### Tool : gds2rh
### RedHawk Version : 19.1.7p1 RHEL6
### Vendor : Apache Design, Inc. A Subsidiary of ANSYS, Inc. 
### Date : Mar 02 2019, 00:03:14 

### Date generated : Wed Sep 14 16:24:09 2022
 
### Command : gds2rh /nfs/an/disks/an_mos_scratch01/mos/prod/runs/c224uhdlpsprf-ext-version-r1-0-1/r641703_00_00/r641703_00_00/avm/rv_avm/gds2rh_options_powerup.txt

VERSION 5.5 ;
NAMESCASESENSITIVE ON ;
DIVIDERCHAR "/" ;
BUSBITCHARS "[]" ;
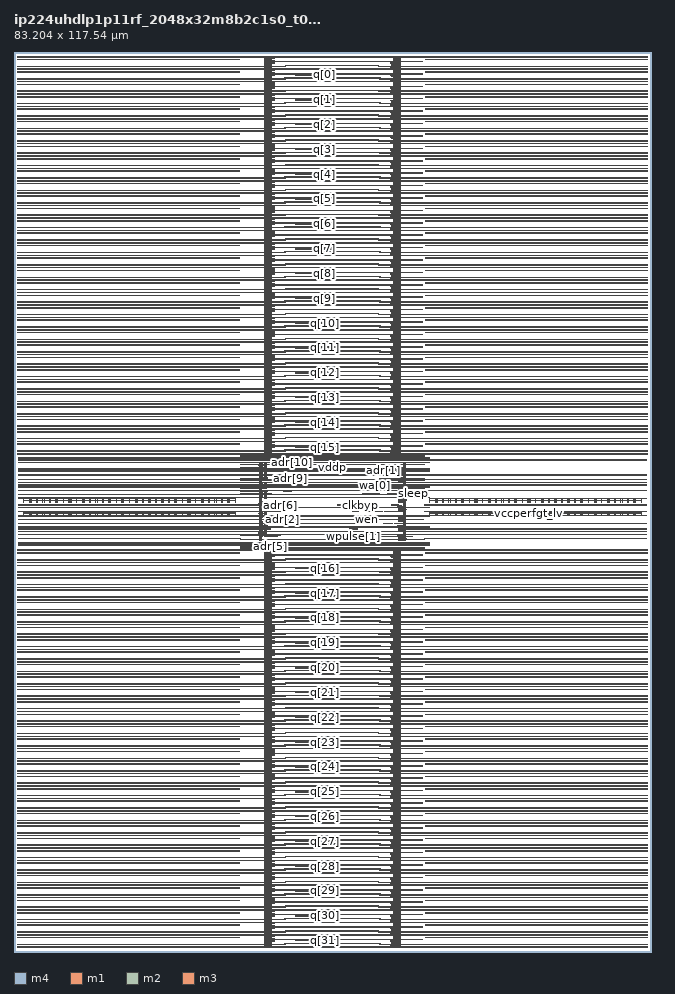
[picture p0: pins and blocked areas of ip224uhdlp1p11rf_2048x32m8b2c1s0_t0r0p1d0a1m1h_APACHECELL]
MACRO ip224uhdlp1p11rf_2048x32m8b2c1s0_t0r0p1d0a1m1h_APACHECELL
 ORIGIN 0.000000 0.000000 ;
 SIZE 83.204000 BY 117.540000 ;
 PIN adr[0]
 DIRECTION INPUT ;
 USE SIGNAL ;
 PORT
 LAYER m4 ;
 RECT 48.159500 62.924000 49.349500 63.000000 ;
 END
 END adr[0]
 PIN adr[10]
 DIRECTION INPUT ;
 USE SIGNAL ;
 PORT
 LAYER m4 ;
 RECT 35.707000 62.924000 36.837000 63.000000 ;
 END
 END adr[10]
 PIN adr[1]
 DIRECTION INPUT ;
 USE SIGNAL ;
 PORT
 LAYER m4 ;
 RECT 47.764500 61.804000 48.751500 61.880000 ;
 END
 END adr[1]
 PIN adr[2]
 DIRECTION INPUT ;
 USE SIGNAL ;
 PORT
 LAYER m4 ;
 RECT 34.445500 57.490000 35.597000 57.546000 ;
 END
 END adr[2]
 PIN adr[3]
 DIRECTION INPUT ;
 USE SIGNAL ;
 PORT
 LAYER m4 ;
 RECT 47.590000 60.848000 48.764000 60.924000 ;
 END
 END adr[3]
 PIN adr[4]
 DIRECTION INPUT ;
 USE SIGNAL ;
 PORT
 LAYER m4 ;
 RECT 48.844000 60.848000 50.006000 60.924000 ;
 END
 END adr[4]
 PIN adr[5]
 DIRECTION INPUT ;
 USE SIGNAL ;
 PORT
 LAYER m4 ;
 RECT 33.045000 52.960000 34.002000 53.036000 ;
 END
 END adr[5]
 PIN adr[6]
 DIRECTION INPUT ;
 USE SIGNAL ;
 PORT
 LAYER m4 ;
 RECT 34.326500 58.326000 35.266000 58.382000 ;
 END
 END adr[6]
 PIN adr[7]
 DIRECTION INPUT ;
 USE SIGNAL ;
 PORT
 LAYER m4 ;
 RECT 33.008000 54.226000 34.389000 54.302000 ;
 END
 END adr[7]
 PIN adr[8]
 DIRECTION INPUT ;
 USE SIGNAL ;
 PORT
 LAYER m4 ;
 RECT 33.432500 54.376000 34.741000 54.452000 ;
 END
 END adr[8]
 PIN adr[9]
 DIRECTION INPUT ;
 USE SIGNAL ;
 PORT
 LAYER m4 ;
 RECT 35.695000 61.804000 36.619500 61.880000 ;
 END
 END adr[9]
 PIN bc1
 DIRECTION INPUT ;
 USE SIGNAL ;
 PORT
 LAYER m4 ;
 RECT 47.844500 61.540000 48.908500 61.616000 ;
 END
 END bc1
 PIN bc2
 DIRECTION INPUT ;
 USE SIGNAL ;
 PORT
 LAYER m4 ;
 RECT 48.764000 59.858000 49.903500 59.914000 ;
 END
 END bc2
 PIN clkbyp
 DIRECTION INPUT ;
 USE SIGNAL ;
 PORT
 LAYER m4 ;
 RECT 44.767000 58.326000 45.619500 58.382000 ;
 END
 END clkbyp
 PIN deepslp
 DIRECTION INPUT ;
 USE SIGNAL ;
 PORT
 LAYER m4 ;
 RECT 49.268000 58.326000 50.262000 58.382000 ;
 END
 END deepslp
 PIN din[0]
 DIRECTION INPUT ;
 USE SIGNAL ;
 PORT
 LAYER m4 ;
 RECT 36.766000 114.488000 39.618000 114.596000 ;
 END
 END din[0]
 PIN din[10]
 DIRECTION INPUT ;
 USE SIGNAL ;
 PORT
 LAYER m4 ;
 RECT 36.766000 82.088000 39.618000 82.196000 ;
 END
 END din[10]
 PIN din[11]
 DIRECTION INPUT ;
 USE SIGNAL ;
 PORT
 LAYER m4 ;
 RECT 36.766000 78.848000 39.618000 78.956000 ;
 END
 END din[11]
 PIN din[12]
 DIRECTION INPUT ;
 USE SIGNAL ;
 PORT
 LAYER m4 ;
 RECT 36.766000 75.608000 39.618000 75.716000 ;
 END
 END din[12]
 PIN din[13]
 DIRECTION INPUT ;
 USE SIGNAL ;
 PORT
 LAYER m4 ;
 RECT 36.766000 72.368000 39.618000 72.476000 ;
 END
 END din[13]
 PIN din[14]
 DIRECTION INPUT ;
 USE SIGNAL ;
 PORT
 LAYER m4 ;
 RECT 36.766000 69.128000 39.618000 69.236000 ;
 END
 END din[14]
 PIN din[15]
 DIRECTION INPUT ;
 USE SIGNAL ;
 PORT
 LAYER m4 ;
 RECT 36.766000 65.888000 39.618000 65.996000 ;
 END
 END din[15]
 PIN din[16]
 DIRECTION INPUT ;
 USE SIGNAL ;
 PORT
 LAYER m4 ;
 RECT 36.766000 50.048000 39.618000 50.156000 ;
 END
 END din[16]
 PIN din[17]
 DIRECTION INPUT ;
 USE SIGNAL ;
 PORT
 LAYER m4 ;
 RECT 36.766000 46.808000 39.618000 46.916000 ;
 END
 END din[17]
 PIN din[18]
 DIRECTION INPUT ;
 USE SIGNAL ;
 PORT
 LAYER m4 ;
 RECT 36.766000 43.568000 39.618000 43.676000 ;
 END
 END din[18]
 PIN din[19]
 DIRECTION INPUT ;
 USE SIGNAL ;
 PORT
 LAYER m4 ;
 RECT 36.766000 40.328000 39.618000 40.436000 ;
 END
 END din[19]
 PIN din[1]
 DIRECTION INPUT ;
 USE SIGNAL ;
 PORT
 LAYER m4 ;
 RECT 36.766000 111.248000 39.618000 111.356000 ;
 END
 END din[1]
 PIN din[20]
 DIRECTION INPUT ;
 USE SIGNAL ;
 PORT
 LAYER m4 ;
 RECT 36.766000 37.088000 39.618000 37.196000 ;
 END
 END din[20]
 PIN din[21]
 DIRECTION INPUT ;
 USE SIGNAL ;
 PORT
 LAYER m4 ;
 RECT 36.766000 33.848000 39.618000 33.956000 ;
 END
 END din[21]
 PIN din[22]
 DIRECTION INPUT ;
 USE SIGNAL ;
 PORT
 LAYER m4 ;
 RECT 36.766000 30.608000 39.618000 30.716000 ;
 END
 END din[22]
 PIN din[23]
 DIRECTION INPUT ;
 USE SIGNAL ;
 PORT
 LAYER m4 ;
 RECT 36.766000 27.368000 39.618000 27.476000 ;
 END
 END din[23]
 PIN din[24]
 DIRECTION INPUT ;
 USE SIGNAL ;
 PORT
 LAYER m4 ;
 RECT 36.766000 24.128000 39.618000 24.236000 ;
 END
 END din[24]
 PIN din[25]
 DIRECTION INPUT ;
 USE SIGNAL ;
 PORT
 LAYER m4 ;
 RECT 36.766000 20.888000 39.618000 20.996000 ;
 END
 END din[25]
 PIN din[26]
 DIRECTION INPUT ;
 USE SIGNAL ;
 PORT
 LAYER m4 ;
 RECT 36.766000 17.648000 39.618000 17.756000 ;
 END
 END din[26]
 PIN din[27]
 DIRECTION INPUT ;
 USE SIGNAL ;
 PORT
 LAYER m4 ;
 RECT 36.766000 14.408000 39.618000 14.516000 ;
 END
 END din[27]
 PIN din[28]
 DIRECTION INPUT ;
 USE SIGNAL ;
 PORT
 LAYER m4 ;
 RECT 36.766000 11.168000 39.618000 11.276000 ;
 END
 END din[28]
 PIN din[29]
 DIRECTION INPUT ;
 USE SIGNAL ;
 PORT
 LAYER m4 ;
 RECT 36.766000 7.928000 39.618000 8.036000 ;
 END
 END din[29]
 PIN din[2]
 DIRECTION INPUT ;
 USE SIGNAL ;
 PORT
 LAYER m4 ;
 RECT 36.766000 108.008000 39.618000 108.116000 ;
 END
 END din[2]
 PIN din[30]
 DIRECTION INPUT ;
 USE SIGNAL ;
 PORT
 LAYER m4 ;
 RECT 36.766000 4.688000 39.618000 4.796000 ;
 END
 END din[30]
 PIN din[31]
 DIRECTION INPUT ;
 USE SIGNAL ;
 PORT
 LAYER m4 ;
 RECT 36.766000 1.448000 39.618000 1.556000 ;
 END
 END din[31]
 PIN din[3]
 DIRECTION INPUT ;
 USE SIGNAL ;
 PORT
 LAYER m4 ;
 RECT 36.766000 104.768000 39.618000 104.876000 ;
 END
 END din[3]
 PIN din[4]
 DIRECTION INPUT ;
 USE SIGNAL ;
 PORT
 LAYER m4 ;
 RECT 36.766000 101.528000 39.618000 101.636000 ;
 END
 END din[4]
 PIN din[5]
 DIRECTION INPUT ;
 USE SIGNAL ;
 PORT
 LAYER m4 ;
 RECT 36.766000 98.288000 39.618000 98.396000 ;
 END
 END din[5]
 PIN din[6]
 DIRECTION INPUT ;
 USE SIGNAL ;
 PORT
 LAYER m4 ;
 RECT 36.766000 95.048000 39.618000 95.156000 ;
 END
 END din[6]
 PIN din[7]
 DIRECTION INPUT ;
 USE SIGNAL ;
 PORT
 LAYER m4 ;
 RECT 36.766000 91.808000 39.618000 91.916000 ;
 END
 END din[7]
 PIN din[8]
 DIRECTION INPUT ;
 USE SIGNAL ;
 PORT
 LAYER m4 ;
 RECT 36.766000 88.568000 39.618000 88.676000 ;
 END
 END din[8]
 PIN din[9]
 DIRECTION INPUT ;
 USE SIGNAL ;
 PORT
 LAYER m4 ;
 RECT 36.766000 85.328000 39.618000 85.436000 ;
 END
 END din[9]
 PIN fwen
 DIRECTION INPUT ;
 USE SIGNAL ;
 PORT
 LAYER m4 ;
 RECT 48.419500 57.490000 49.374000 57.546000 ;
 END
 END fwen
 PIN mc[0]
 DIRECTION INPUT ;
 USE SIGNAL ;
 PORT
 LAYER m4 ;
 RECT 35.244000 60.124000 36.283000 60.200000 ;
 END
 END mc[0]
 PIN mc[1]
 DIRECTION INPUT ;
 USE SIGNAL ;
 PORT
 LAYER m4 ;
 RECT 33.024000 61.540000 34.252000 61.616000 ;
 END
 END mc[1]
 PIN mc[2]
 DIRECTION INPUT ;
 USE SIGNAL ;
 PORT
 LAYER m4 ;
 RECT 34.383000 61.540000 35.525000 61.616000 ;
 END
 END mc[2]
 PIN mcen
 DIRECTION INPUT ;
 USE SIGNAL ;
 PORT
 LAYER m4 ;
 RECT 34.480500 61.804000 35.417000 61.880000 ;
 END
 END mcen
 PIN mpr
 DIRECTION OUTPUT ;
 USE SIGNAL ;
 PORT
 LAYER m4 ;
 RECT 47.125000 57.490000 48.061000 57.546000 ;
 END
 END mpr
 PIN q[0]
 DIRECTION OUTPUT ;
 USE SIGNAL ;
 PORT
 LAYER m4 ;
 RECT 39.698000 114.488000 41.423000 114.596000 ;
 END
 END q[0]
 PIN q[10]
 DIRECTION OUTPUT ;
 USE SIGNAL ;
 PORT
 LAYER m4 ;
 RECT 39.698000 82.088000 41.423000 82.196000 ;
 END
 END q[10]
 PIN q[11]
 DIRECTION OUTPUT ;
 USE SIGNAL ;
 PORT
 LAYER m4 ;
 RECT 39.698000 78.848000 41.423000 78.956000 ;
 END
 END q[11]
 PIN q[12]
 DIRECTION OUTPUT ;
 USE SIGNAL ;
 PORT
 LAYER m4 ;
 RECT 39.698000 75.608000 41.423000 75.716000 ;
 END
 END q[12]
 PIN q[13]
 DIRECTION OUTPUT ;
 USE SIGNAL ;
 PORT
 LAYER m4 ;
 RECT 39.698000 72.368000 41.423000 72.476000 ;
 END
 END q[13]
 PIN q[14]
 DIRECTION OUTPUT ;
 USE SIGNAL ;
 PORT
 LAYER m4 ;
 RECT 39.698000 69.128000 41.423000 69.236000 ;
 END
 END q[14]
 PIN q[15]
 DIRECTION OUTPUT ;
 USE SIGNAL ;
 PORT
 LAYER m4 ;
 RECT 39.698000 65.888000 41.423000 65.996000 ;
 END
 END q[15]
 PIN q[16]
 DIRECTION OUTPUT ;
 USE SIGNAL ;
 PORT
 LAYER m4 ;
 RECT 39.698000 50.048000 41.423000 50.156000 ;
 END
 END q[16]
 PIN q[17]
 DIRECTION OUTPUT ;
 USE SIGNAL ;
 PORT
 LAYER m4 ;
 RECT 39.698000 46.808000 41.423000 46.916000 ;
 END
 END q[17]
 PIN q[18]
 DIRECTION OUTPUT ;
 USE SIGNAL ;
 PORT
 LAYER m4 ;
 RECT 39.698000 43.568000 41.423000 43.676000 ;
 END
 END q[18]
 PIN q[19]
 DIRECTION OUTPUT ;
 USE SIGNAL ;
 PORT
 LAYER m4 ;
 RECT 39.698000 40.328000 41.423000 40.436000 ;
 END
 END q[19]
 PIN q[1]
 DIRECTION OUTPUT ;
 USE SIGNAL ;
 PORT
 LAYER m4 ;
 RECT 39.698000 111.248000 41.423000 111.356000 ;
 END
 END q[1]
 PIN q[20]
 DIRECTION OUTPUT ;
 USE SIGNAL ;
 PORT
 LAYER m4 ;
 RECT 39.698000 37.088000 41.423000 37.196000 ;
 END
 END q[20]
 PIN q[21]
 DIRECTION OUTPUT ;
 USE SIGNAL ;
 PORT
 LAYER m4 ;
 RECT 39.698000 33.848000 41.423000 33.956000 ;
 END
 END q[21]
 PIN q[22]
 DIRECTION OUTPUT ;
 USE SIGNAL ;
 PORT
 LAYER m4 ;
 RECT 39.698000 30.608000 41.423000 30.716000 ;
 END
 END q[22]
 PIN q[23]
 DIRECTION OUTPUT ;
 USE SIGNAL ;
 PORT
 LAYER m4 ;
 RECT 39.698000 27.368000 41.423000 27.476000 ;
 END
 END q[23]
 PIN q[24]
 DIRECTION OUTPUT ;
 USE SIGNAL ;
 PORT
 LAYER m4 ;
 RECT 39.698000 24.128000 41.423000 24.236000 ;
 END
 END q[24]
 PIN q[25]
 DIRECTION OUTPUT ;
 USE SIGNAL ;
 PORT
 LAYER m4 ;
 RECT 39.698000 20.888000 41.423000 20.996000 ;
 END
 END q[25]
 PIN q[26]
 DIRECTION OUTPUT ;
 USE SIGNAL ;
 PORT
 LAYER m4 ;
 RECT 39.698000 17.648000 41.423000 17.756000 ;
 END
 END q[26]
 PIN q[27]
 DIRECTION OUTPUT ;
 USE SIGNAL ;
 PORT
 LAYER m4 ;
 RECT 39.698000 14.408000 41.423000 14.516000 ;
 END
 END q[27]
 PIN q[28]
 DIRECTION OUTPUT ;
 USE SIGNAL ;
 PORT
 LAYER m4 ;
 RECT 39.698000 11.168000 41.423000 11.276000 ;
 END
 END q[28]
 PIN q[29]
 DIRECTION OUTPUT ;
 USE SIGNAL ;
 PORT
 LAYER m4 ;
 RECT 39.698000 7.928000 41.423000 8.036000 ;
 END
 END q[29]
 PIN q[2]
 DIRECTION OUTPUT ;
 USE SIGNAL ;
 PORT
 LAYER m4 ;
 RECT 39.698000 108.008000 41.423000 108.116000 ;
 END
 END q[2]
 PIN q[30]
 DIRECTION OUTPUT ;
 USE SIGNAL ;
 PORT
 LAYER m4 ;
 RECT 39.698000 4.688000 41.423000 4.796000 ;
 END
 END q[30]
 PIN q[31]
 DIRECTION OUTPUT ;
 USE SIGNAL ;
 PORT
 LAYER m4 ;
 RECT 39.698000 1.448000 41.423000 1.556000 ;
 END
 END q[31]
 PIN q[3]
 DIRECTION OUTPUT ;
 USE SIGNAL ;
 PORT
 LAYER m4 ;
 RECT 39.698000 104.768000 41.423000 104.876000 ;
 END
 END q[3]
 PIN q[4]
 DIRECTION OUTPUT ;
 USE SIGNAL ;
 PORT
 LAYER m4 ;
 RECT 39.698000 101.528000 41.423000 101.636000 ;
 END
 END q[4]
 PIN q[5]
 DIRECTION OUTPUT ;
 USE SIGNAL ;
 PORT
 LAYER m4 ;
 RECT 39.698000 98.288000 41.423000 98.396000 ;
 END
 END q[5]
 PIN q[6]
 DIRECTION OUTPUT ;
 USE SIGNAL ;
 PORT
 LAYER m4 ;
 RECT 39.698000 95.048000 41.423000 95.156000 ;
 END
 END q[6]
 PIN q[7]
 DIRECTION OUTPUT ;
 USE SIGNAL ;
 PORT
 LAYER m4 ;
 RECT 39.698000 91.808000 41.423000 91.916000 ;
 END
 END q[7]
 PIN q[8]
 DIRECTION OUTPUT ;
 USE SIGNAL ;
 PORT
 LAYER m4 ;
 RECT 39.698000 88.568000 41.423000 88.676000 ;
 END
 END q[8]
 PIN q[9]
 DIRECTION OUTPUT ;
 USE SIGNAL ;
 PORT
 LAYER m4 ;
 RECT 39.698000 85.328000 41.423000 85.436000 ;
 END
 END q[9]
 PIN ren
 DIRECTION INPUT ;
 USE SIGNAL ;
 PORT
 LAYER m4 ;
 RECT 44.150000 57.490000 45.055500 57.546000 ;
 END
 END ren
 PIN shutoff
 DIRECTION INPUT ;
 USE SIGNAL ;
 PORT
 LAYER m4 ;
 RECT 49.596000 57.490000 50.517500 57.546000 ;
 END
 END shutoff
 PIN sleep
 DIRECTION INPUT ;
 USE SIGNAL ;
 PORT
 LAYER m4 ;
 RECT 51.755500 59.858000 52.678500 59.914000 ;
 END
 END sleep
 PIN wa[0]
 DIRECTION INPUT ;
 USE SIGNAL ;
 PORT
 LAYER m4 ;
 RECT 46.712000 59.858000 47.676500 59.914000 ;
 END
 END wa[0]
 PIN wa[1]
 DIRECTION INPUT ;
 USE SIGNAL ;
 PORT
 LAYER m4 ;
 RECT 45.499500 59.858000 46.530000 59.914000 ;
 END
 END wa[1]
 PIN wen
 DIRECTION INPUT ;
 USE SIGNAL ;
 PORT
 LAYER m4 ;
 RECT 45.614000 57.490000 46.502000 57.546000 ;
 END
 END wen
 PIN wpulse[0]
 DIRECTION INPUT ;
 USE SIGNAL ;
 PORT
 LAYER m4 ;
 RECT 48.239000 55.924000 49.496000 56.000000 ;
 END
 END wpulse[0]
 PIN wpulse[1]
 DIRECTION INPUT ;
 USE SIGNAL ;
 PORT
 LAYER m4 ;
 RECT 43.758500 55.200000 44.802000 55.276000 ;
 END
 END wpulse[1]
 PIN wpulseen
 DIRECTION INPUT ;
 USE SIGNAL ;
 PORT
 LAYER m4 ;
 RECT 44.564500 55.924000 45.451000 56.000000 ;
 END
 END wpulseen
 PIN clk
 DIRECTION INPUT ;
 USE CLOCK ;
 PORT
 LAYER m4 ;
 RECT 42.224500 58.326000 43.256500 58.382000 ;
 END
 END clk
 PIN vddp
 DIRECTION INPUT ;
 USE POWER ;
 PORT
 LAYER m4 ;
 RECT 0.480000 0.958000 35.401000 1.034000 ;
 RECT 0.480000 1.846000 29.388000 1.922000 ;
 RECT 0.480000 10.678000 35.401000 10.754000 ;
 RECT 0.480000 100.306000 29.388000 100.382000 ;
 RECT 0.480000 101.038000 35.401000 101.114000 ;
 RECT 0.480000 101.926000 29.388000 102.002000 ;
 RECT 0.480000 102.658000 35.487000 102.734000 ;
 RECT 0.480000 103.546000 29.388000 103.622000 ;
 RECT 0.480000 104.278000 35.401000 104.354000 ;
 RECT 0.480000 105.166000 29.388000 105.242000 ;
 RECT 0.480000 105.898000 35.487000 105.974000 ;
 RECT 0.480000 106.786000 29.388000 106.862000 ;
 RECT 0.480000 107.518000 35.401000 107.594000 ;
 RECT 0.480000 108.406000 29.388000 108.482000 ;
 RECT 0.480000 109.138000 35.487000 109.214000 ;
 RECT 0.480000 11.566000 29.388000 11.642000 ;
 RECT 0.480000 110.026000 29.388000 110.102000 ;
 RECT 0.480000 110.758000 35.401000 110.834000 ;
 RECT 0.480000 111.646000 29.388000 111.722000 ;
 RECT 0.480000 112.378000 35.487000 112.454000 ;
 RECT 0.480000 113.266000 29.388000 113.342000 ;
 RECT 0.480000 113.998000 35.401000 114.074000 ;
 RECT 0.480000 114.886000 29.388000 114.962000 ;
 RECT 0.480000 115.618000 35.487000 115.694000 ;
 RECT 0.480000 116.506000 29.388000 116.582000 ;
 RECT 0.480000 12.298000 35.487000 12.374000 ;
 RECT 0.480000 13.186000 29.388000 13.262000 ;
 RECT 0.480000 13.918000 35.401000 13.994000 ;
 RECT 0.480000 14.806000 29.388000 14.882000 ;
 RECT 0.480000 15.538000 35.487000 15.614000 ;
 RECT 0.480000 16.426000 29.388000 16.502000 ;
 RECT 0.480000 17.158000 35.401000 17.234000 ;
 RECT 0.480000 18.046000 29.388000 18.122000 ;
 RECT 0.480000 18.778000 35.487000 18.854000 ;
 RECT 0.480000 19.666000 29.388000 19.742000 ;
 RECT 0.480000 2.578000 35.487000 2.654000 ;
 RECT 0.480000 20.398000 35.401000 20.474000 ;
 RECT 0.480000 21.286000 29.388000 21.362000 ;
 RECT 0.480000 22.018000 35.487000 22.094000 ;
 RECT 0.480000 22.906000 29.388000 22.982000 ;
 RECT 0.480000 23.638000 35.401000 23.714000 ;
 RECT 0.480000 24.526000 29.388000 24.602000 ;
 RECT 0.480000 25.258000 35.487000 25.334000 ;
 RECT 0.480000 26.146000 29.388000 26.222000 ;
 RECT 0.480000 26.878000 35.401000 26.954000 ;
 RECT 0.480000 27.766000 29.388000 27.842000 ;
 RECT 0.480000 28.498000 35.487000 28.574000 ;
 RECT 0.480000 29.386000 29.388000 29.462000 ;
 RECT 0.480000 3.466000 29.388000 3.542000 ;
 RECT 0.480000 30.118000 35.401000 30.194000 ;
 RECT 0.480000 31.006000 29.388000 31.082000 ;
 RECT 0.480000 31.738000 35.487000 31.814000 ;
 RECT 0.480000 32.626000 29.388000 32.702000 ;
 RECT 0.480000 33.358000 35.401000 33.434000 ;
 RECT 0.480000 34.246000 29.388000 34.322000 ;
 RECT 0.480000 34.978000 35.487000 35.054000 ;
 RECT 0.480000 35.866000 29.388000 35.942000 ;
 RECT 0.480000 36.598000 35.401000 36.674000 ;
 RECT 0.480000 37.486000 29.388000 37.562000 ;
 RECT 0.480000 38.218000 35.487000 38.294000 ;
 RECT 0.480000 39.106000 29.388000 39.182000 ;
 RECT 0.480000 39.838000 35.401000 39.914000 ;
 RECT 0.480000 4.198000 35.401000 4.274000 ;
 RECT 0.480000 40.726000 29.388000 40.802000 ;
 RECT 0.480000 41.458000 35.487000 41.534000 ;
 RECT 0.480000 42.346000 29.388000 42.422000 ;
 RECT 0.480000 43.078000 35.401000 43.154000 ;
 RECT 0.480000 43.966000 29.388000 44.042000 ;
 RECT 0.480000 44.698000 35.487000 44.774000 ;
 RECT 0.480000 45.586000 29.388000 45.662000 ;
 RECT 0.480000 46.318000 35.401000 46.394000 ;
 RECT 0.480000 47.206000 29.388000 47.282000 ;
 RECT 0.480000 47.938000 35.487000 48.014000 ;
 RECT 0.480000 48.826000 29.388000 48.902000 ;
 RECT 0.480000 49.558000 35.401000 49.634000 ;
 RECT 0.480000 5.086000 29.388000 5.162000 ;
 RECT 0.480000 5.818000 35.487000 5.894000 ;
 RECT 0.480000 50.446000 29.388000 50.522000 ;
 RECT 0.480000 51.178000 35.487000 51.254000 ;
 RECT 0.480000 52.066000 29.388000 52.142000 ;
 RECT 0.480000 6.706000 29.388000 6.782000 ;
 RECT 0.480000 65.398000 35.401000 65.474000 ;
 RECT 0.480000 66.286000 29.388000 66.362000 ;
 RECT 0.480000 67.018000 35.487000 67.094000 ;
 RECT 0.480000 67.906000 29.388000 67.982000 ;
 RECT 0.480000 68.638000 35.401000 68.714000 ;
 RECT 0.480000 69.526000 29.388000 69.602000 ;
 RECT 0.480000 7.438000 35.401000 7.514000 ;
 RECT 0.480000 70.258000 35.487000 70.334000 ;
 RECT 0.480000 71.146000 29.388000 71.222000 ;
 RECT 0.480000 71.878000 35.401000 71.954000 ;
 RECT 0.480000 72.766000 29.388000 72.842000 ;
 RECT 0.480000 73.498000 35.487000 73.574000 ;
 RECT 0.480000 74.386000 29.388000 74.462000 ;
 RECT 0.480000 75.118000 35.401000 75.194000 ;
 RECT 0.480000 76.006000 29.388000 76.082000 ;
 RECT 0.480000 76.738000 35.487000 76.814000 ;
 RECT 0.480000 77.626000 29.388000 77.702000 ;
 RECT 0.480000 78.358000 35.401000 78.434000 ;
 RECT 0.480000 79.246000 29.388000 79.322000 ;
 RECT 0.480000 79.978000 35.487000 80.054000 ;
 RECT 0.480000 8.326000 29.388000 8.402000 ;
 RECT 0.480000 80.866000 29.388000 80.942000 ;
 RECT 0.480000 81.598000 35.401000 81.674000 ;
 RECT 0.480000 82.486000 29.388000 82.562000 ;
 RECT 0.480000 83.218000 35.487000 83.294000 ;
 RECT 0.480000 84.106000 29.388000 84.182000 ;
 RECT 0.480000 84.838000 35.401000 84.914000 ;
 RECT 0.480000 85.726000 29.388000 85.802000 ;
 RECT 0.480000 86.458000 35.487000 86.534000 ;
 RECT 0.480000 87.346000 29.388000 87.422000 ;
 RECT 0.480000 88.078000 35.401000 88.154000 ;
 RECT 0.480000 88.966000 29.388000 89.042000 ;
 RECT 0.480000 89.698000 35.487000 89.774000 ;
 RECT 0.480000 9.058000 35.487000 9.134000 ;
 RECT 0.480000 9.946000 29.388000 10.022000 ;
 RECT 0.480000 90.586000 29.388000 90.662000 ;
 RECT 0.480000 91.318000 35.401000 91.394000 ;
 RECT 0.480000 92.206000 29.388000 92.282000 ;
 RECT 0.480000 92.938000 35.487000 93.014000 ;
 RECT 0.480000 93.826000 29.388000 93.902000 ;
 RECT 0.480000 94.558000 35.401000 94.634000 ;
 RECT 0.480000 95.446000 29.388000 95.522000 ;
 RECT 0.480000 96.178000 35.487000 96.254000 ;
 RECT 0.480000 97.066000 29.388000 97.142000 ;
 RECT 0.480000 97.798000 35.401000 97.874000 ;
 RECT 0.480000 98.686000 29.388000 98.762000 ;
 RECT 0.480000 99.418000 35.487000 99.494000 ;
 RECT 0.616000 53.948000 29.560000 54.024000 ;
 RECT 0.616000 54.508000 82.588000 54.584000 ;
 RECT 0.616000 54.904000 82.588000 54.980000 ;
 RECT 0.616000 55.200000 29.560000 55.276000 ;
 RECT 0.616000 55.924000 29.560000 56.000000 ;
 RECT 0.616000 56.992000 28.912000 57.036000 ;
 RECT 0.616000 57.490000 29.560000 57.546000 ;
 RECT 0.616000 58.326000 29.560000 58.382000 ;
 RECT 0.616000 59.244000 28.912000 59.288000 ;
 RECT 0.616000 60.256000 82.588000 60.332000 ;
 RECT 0.616000 60.980000 82.588000 61.056000 ;
 RECT 0.616000 61.276000 82.588000 61.352000 ;
 RECT 0.616000 61.672000 82.588000 61.748000 ;
 RECT 0.616000 62.232000 82.588000 62.308000 ;
 RECT 0.616000 64.176000 82.588000 64.284000 ;
 RECT 29.600000 52.564000 53.604000 52.640000 ;
 RECT 29.600000 52.696000 53.604000 52.772000 ;
 RECT 29.600000 52.960000 32.965000 53.036000 ;
 RECT 29.600000 53.816000 53.604000 53.892000 ;
 RECT 29.600000 54.376000 33.352500 54.452000 ;
 RECT 29.600000 63.616000 53.604000 63.692000 ;
 RECT 29.600000 64.636000 53.604000 64.712000 ;
 RECT 29.600000 64.900000 53.604000 64.976000 ;
 RECT 29.608500 59.858000 33.602500 59.914000 ;
 RECT 29.608500 60.124000 33.168500 60.200000 ;
 RECT 29.608500 60.552000 32.918500 60.628000 ;
 RECT 29.608500 61.540000 32.918500 61.616000 ;
 RECT 29.608500 61.804000 32.918500 61.880000 ;
 RECT 29.608500 62.924000 32.918500 63.000000 ;
 RECT 29.608500 63.220000 32.918500 63.296000 ;
 RECT 29.651000 58.326000 34.101500 58.382000 ;
 RECT 29.654000 57.490000 34.365500 57.546000 ;
 RECT 29.669000 55.924000 44.484500 56.000000 ;
 RECT 29.732000 55.200000 33.564000 55.276000 ;
 RECT 35.325000 1.080000 47.814000 1.156000 ;
 RECT 35.325000 10.800000 47.814000 10.876000 ;
 RECT 35.325000 101.160000 47.814000 101.236000 ;
 RECT 35.325000 104.400000 47.814000 104.476000 ;
 RECT 35.325000 107.640000 47.814000 107.716000 ;
 RECT 35.325000 110.880000 47.814000 110.956000 ;
 RECT 35.325000 114.120000 47.814000 114.196000 ;
 RECT 35.325000 14.040000 47.814000 14.116000 ;
 RECT 35.325000 17.280000 47.814000 17.356000 ;
 RECT 35.325000 20.520000 47.814000 20.596000 ;
 RECT 35.325000 23.760000 47.814000 23.836000 ;
 RECT 35.325000 27.000000 47.814000 27.076000 ;
 RECT 35.325000 30.240000 47.814000 30.316000 ;
 RECT 35.325000 33.480000 47.814000 33.556000 ;
 RECT 35.325000 36.720000 47.814000 36.796000 ;
 RECT 35.325000 39.960000 47.814000 40.036000 ;
 RECT 35.325000 4.320000 47.814000 4.396000 ;
 RECT 35.325000 43.200000 47.814000 43.276000 ;
 RECT 35.325000 46.440000 47.814000 46.516000 ;
 RECT 35.325000 49.680000 47.814000 49.756000 ;
 RECT 35.325000 65.520000 47.814000 65.596000 ;
 RECT 35.325000 68.760000 47.814000 68.836000 ;
 RECT 35.325000 7.560000 47.814000 7.636000 ;
 RECT 35.325000 72.000000 47.814000 72.076000 ;
 RECT 35.325000 75.240000 47.814000 75.316000 ;
 RECT 35.325000 78.480000 47.814000 78.556000 ;
 RECT 35.325000 81.720000 47.814000 81.796000 ;
 RECT 35.325000 84.960000 47.814000 85.036000 ;
 RECT 35.325000 88.200000 47.814000 88.276000 ;
 RECT 35.325000 91.440000 47.814000 91.516000 ;
 RECT 35.325000 94.680000 47.814000 94.756000 ;
 RECT 35.325000 97.920000 47.814000 97.996000 ;
 RECT 35.487000 102.780000 47.657500 102.856000 ;
 RECT 35.487000 106.020000 47.657500 106.096000 ;
 RECT 35.487000 109.260000 47.657500 109.336000 ;
 RECT 35.487000 112.500000 47.657500 112.576000 ;
 RECT 35.487000 115.740000 47.657500 115.816000 ;
 RECT 35.487000 12.420000 47.657500 12.496000 ;
 RECT 35.487000 15.660000 47.657500 15.736000 ;
 RECT 35.487000 18.900000 47.657500 18.976000 ;
 RECT 35.487000 2.700000 47.657500 2.776000 ;
 RECT 35.487000 22.140000 47.657500 22.216000 ;
 RECT 35.487000 25.380000 47.657500 25.456000 ;
 RECT 35.487000 28.620000 47.657500 28.696000 ;
 RECT 35.487000 31.860000 47.657500 31.936000 ;
 RECT 35.487000 35.100000 47.657500 35.176000 ;
 RECT 35.487000 38.340000 47.657500 38.416000 ;
 RECT 35.487000 41.580000 47.657500 41.656000 ;
 RECT 35.487000 44.820000 47.657500 44.896000 ;
 RECT 35.487000 48.060000 47.657500 48.136000 ;
 RECT 35.487000 5.940000 47.657500 6.016000 ;
 RECT 35.487000 51.300000 47.657500 51.376000 ;
 RECT 35.487000 67.140000 47.657500 67.216000 ;
 RECT 35.487000 70.380000 47.657500 70.456000 ;
 RECT 35.487000 73.620000 47.657500 73.696000 ;
 RECT 35.487000 76.860000 47.657500 76.936000 ;
 RECT 35.487000 80.100000 47.657500 80.176000 ;
 RECT 35.487000 83.340000 47.657500 83.416000 ;
 RECT 35.487000 86.580000 47.657500 86.656000 ;
 RECT 35.487000 89.820000 47.657500 89.896000 ;
 RECT 35.487000 9.180000 47.657500 9.256000 ;
 RECT 35.487000 93.060000 47.657500 93.136000 ;
 RECT 35.487000 96.300000 47.657500 96.376000 ;
 RECT 35.487000 99.540000 47.657500 99.616000 ;
 RECT 46.038000 60.552000 53.557500 60.608000 ;
 RECT 47.581500 102.658000 82.724000 102.734000 ;
 RECT 47.581500 105.898000 82.724000 105.974000 ;
 RECT 47.581500 109.138000 82.724000 109.214000 ;
 RECT 47.581500 112.378000 82.724000 112.454000 ;
 RECT 47.581500 115.618000 82.724000 115.694000 ;
 RECT 47.581500 12.298000 82.724000 12.374000 ;
 RECT 47.581500 15.538000 82.724000 15.614000 ;
 RECT 47.581500 18.778000 82.724000 18.854000 ;
 RECT 47.581500 2.578000 82.724000 2.654000 ;
 RECT 47.581500 22.018000 82.724000 22.094000 ;
 RECT 47.581500 25.258000 82.724000 25.334000 ;
 RECT 47.581500 28.498000 82.724000 28.574000 ;
 RECT 47.581500 31.738000 82.724000 31.814000 ;
 RECT 47.581500 34.978000 82.724000 35.054000 ;
 RECT 47.581500 38.218000 82.724000 38.294000 ;
 RECT 47.581500 41.458000 82.724000 41.534000 ;
 RECT 47.581500 44.698000 82.724000 44.774000 ;
 RECT 47.581500 47.938000 82.724000 48.014000 ;
 RECT 47.581500 5.818000 82.724000 5.894000 ;
 RECT 47.581500 51.178000 82.724000 51.254000 ;
 RECT 47.581500 67.018000 82.724000 67.094000 ;
 RECT 47.581500 70.258000 82.724000 70.334000 ;
 RECT 47.581500 73.498000 82.724000 73.574000 ;
 RECT 47.581500 76.738000 82.724000 76.814000 ;
 RECT 47.581500 79.978000 82.724000 80.054000 ;
 RECT 47.581500 83.218000 82.724000 83.294000 ;
 RECT 47.581500 86.458000 82.724000 86.534000 ;
 RECT 47.581500 89.698000 82.724000 89.774000 ;
 RECT 47.581500 9.058000 82.724000 9.134000 ;
 RECT 47.581500 92.938000 82.724000 93.014000 ;
 RECT 47.581500 96.178000 82.724000 96.254000 ;
 RECT 47.581500 99.418000 82.724000 99.494000 ;
 RECT 47.738000 0.958000 82.724000 1.034000 ;
 RECT 47.738000 10.678000 82.724000 10.754000 ;
 RECT 47.738000 101.038000 82.724000 101.114000 ;
 RECT 47.738000 104.278000 82.724000 104.354000 ;
 RECT 47.738000 107.518000 82.724000 107.594000 ;
 RECT 47.738000 110.758000 82.724000 110.834000 ;
 RECT 47.738000 113.998000 82.724000 114.074000 ;
 RECT 47.738000 13.918000 82.724000 13.994000 ;
 RECT 47.738000 17.158000 82.724000 17.234000 ;
 RECT 47.738000 20.398000 82.724000 20.474000 ;
 RECT 47.738000 23.638000 82.724000 23.714000 ;
 RECT 47.738000 26.878000 82.724000 26.954000 ;
 RECT 47.738000 30.118000 82.724000 30.194000 ;
 RECT 47.738000 33.358000 82.724000 33.434000 ;
 RECT 47.738000 36.598000 82.724000 36.674000 ;
 RECT 47.738000 39.838000 82.724000 39.914000 ;
 RECT 47.738000 4.198000 82.724000 4.274000 ;
 RECT 47.738000 43.078000 82.724000 43.154000 ;
 RECT 47.738000 46.318000 82.724000 46.394000 ;
 RECT 47.738000 49.558000 82.724000 49.634000 ;
 RECT 47.738000 65.398000 82.724000 65.474000 ;
 RECT 47.738000 68.638000 82.724000 68.714000 ;
 RECT 47.738000 7.438000 82.724000 7.514000 ;
 RECT 47.738000 71.878000 82.724000 71.954000 ;
 RECT 47.738000 75.118000 82.724000 75.194000 ;
 RECT 47.738000 78.358000 82.724000 78.434000 ;
 RECT 47.738000 81.598000 82.724000 81.674000 ;
 RECT 47.738000 84.838000 82.724000 84.914000 ;
 RECT 47.738000 88.078000 82.724000 88.154000 ;
 RECT 47.738000 91.318000 82.724000 91.394000 ;
 RECT 47.738000 94.558000 82.724000 94.634000 ;
 RECT 47.738000 97.798000 82.724000 97.874000 ;
 RECT 47.983000 54.212000 52.092000 54.320000 ;
 RECT 48.831500 61.804000 53.604000 61.880000 ;
 RECT 48.988500 61.540000 53.604000 61.616000 ;
 RECT 49.429500 62.924000 53.604000 63.000000 ;
 RECT 49.686500 55.924000 53.464500 56.000000 ;
 RECT 50.211000 55.200000 53.604000 55.276000 ;
 RECT 50.369500 60.848000 53.604500 60.924000 ;
 RECT 53.644000 53.948000 82.588000 54.024000 ;
 RECT 53.644000 55.924000 82.588000 56.000000 ;
 RECT 53.644000 57.490000 82.588000 57.546000 ;
 RECT 53.644000 58.326000 82.588000 58.382000 ;
 RECT 53.684000 55.200000 82.588000 55.276000 ;
 RECT 53.749000 1.846000 82.724000 1.922000 ;
 RECT 53.749000 100.306000 82.724000 100.382000 ;
 RECT 53.749000 101.926000 82.724000 102.002000 ;
 RECT 53.749000 103.546000 82.724000 103.622000 ;
 RECT 53.749000 105.166000 82.724000 105.242000 ;
 RECT 53.749000 106.786000 82.724000 106.862000 ;
 RECT 53.749000 108.406000 82.724000 108.482000 ;
 RECT 53.749000 11.566000 82.724000 11.642000 ;
 RECT 53.749000 110.026000 82.724000 110.102000 ;
 RECT 53.749000 111.646000 82.724000 111.722000 ;
 RECT 53.749000 113.266000 82.724000 113.342000 ;
 RECT 53.749000 114.886000 82.724000 114.962000 ;
 RECT 53.749000 116.506000 82.724000 116.582000 ;
 RECT 53.749000 13.186000 82.724000 13.262000 ;
 RECT 53.749000 14.806000 82.724000 14.882000 ;
 RECT 53.749000 16.426000 82.724000 16.502000 ;
 RECT 53.749000 18.046000 82.724000 18.122000 ;
 RECT 53.749000 19.666000 82.724000 19.742000 ;
 RECT 53.749000 21.286000 82.724000 21.362000 ;
 RECT 53.749000 22.906000 82.724000 22.982000 ;
 RECT 53.749000 24.526000 82.724000 24.602000 ;
 RECT 53.749000 26.146000 82.724000 26.222000 ;
 RECT 53.749000 27.766000 82.724000 27.842000 ;
 RECT 53.749000 29.386000 82.724000 29.462000 ;
 RECT 53.749000 3.466000 82.724000 3.542000 ;
 RECT 53.749000 31.006000 82.724000 31.082000 ;
 RECT 53.749000 32.626000 82.724000 32.702000 ;
 RECT 53.749000 34.246000 82.724000 34.322000 ;
 RECT 53.749000 35.866000 82.724000 35.942000 ;
 RECT 53.749000 37.486000 82.724000 37.562000 ;
 RECT 53.749000 39.106000 82.724000 39.182000 ;
 RECT 53.749000 40.726000 82.724000 40.802000 ;
 RECT 53.749000 42.346000 82.724000 42.422000 ;
 RECT 53.749000 43.966000 82.724000 44.042000 ;
 RECT 53.749000 45.586000 82.724000 45.662000 ;
 RECT 53.749000 47.206000 82.724000 47.282000 ;
 RECT 53.749000 48.826000 82.724000 48.902000 ;
 RECT 53.749000 5.086000 82.724000 5.162000 ;
 RECT 53.749000 50.446000 82.724000 50.522000 ;
 RECT 53.749000 52.066000 82.724000 52.142000 ;
 RECT 53.749000 6.706000 82.724000 6.782000 ;
 RECT 53.749000 66.286000 82.724000 66.362000 ;
 RECT 53.749000 67.906000 82.724000 67.982000 ;
 RECT 53.749000 69.526000 82.724000 69.602000 ;
 RECT 53.749000 71.146000 82.724000 71.222000 ;
 RECT 53.749000 72.766000 82.724000 72.842000 ;
 RECT 53.749000 74.386000 82.724000 74.462000 ;
 RECT 53.749000 76.006000 82.724000 76.082000 ;
 RECT 53.749000 77.626000 82.724000 77.702000 ;
 RECT 53.749000 79.246000 82.724000 79.322000 ;
 RECT 53.749000 8.326000 82.724000 8.402000 ;
 RECT 53.749000 80.866000 82.724000 80.942000 ;
 RECT 53.749000 82.486000 82.724000 82.562000 ;
 RECT 53.749000 84.106000 82.724000 84.182000 ;
 RECT 53.749000 85.726000 82.724000 85.802000 ;
 RECT 53.749000 87.346000 82.724000 87.422000 ;
 RECT 53.749000 88.966000 82.724000 89.042000 ;
 RECT 53.749000 9.946000 82.724000 10.022000 ;
 RECT 53.749000 90.586000 82.724000 90.662000 ;
 RECT 53.749000 92.206000 82.724000 92.282000 ;
 RECT 53.749000 93.826000 82.724000 93.902000 ;
 RECT 53.749000 95.446000 82.724000 95.522000 ;
 RECT 53.749000 97.066000 82.724000 97.142000 ;
 RECT 53.749000 98.686000 82.724000 98.762000 ;
 RECT 54.292000 56.992000 82.588000 57.036000 ;
 RECT 54.292000 59.244000 82.588000 59.288000 ;
 END
 END vddp
 PIN vss
 DIRECTION INOUT ;
 USE GROUND ;
 PORT
 LAYER m4 ;
 RECT 0.480000 0.592000 82.724000 0.668000 ;
 RECT 0.480000 10.312000 82.724000 10.388000 ;
 RECT 0.480000 100.672000 82.724000 100.748000 ;
 RECT 0.480000 102.292000 82.724000 102.368000 ;
 RECT 0.480000 103.912000 82.724000 103.988000 ;
 RECT 0.480000 105.532000 82.724000 105.608000 ;
 RECT 0.480000 107.152000 82.724000 107.228000 ;
 RECT 0.480000 108.772000 82.724000 108.848000 ;
 RECT 0.480000 11.932000 82.724000 12.008000 ;
 RECT 0.480000 110.392000 82.724000 110.468000 ;
 RECT 0.480000 112.012000 82.724000 112.088000 ;
 RECT 0.480000 113.632000 82.724000 113.708000 ;
 RECT 0.480000 115.252000 82.724000 115.328000 ;
 RECT 0.480000 116.872000 82.724000 116.948000 ;
 RECT 0.480000 13.552000 82.724000 13.628000 ;
 RECT 0.480000 15.172000 82.724000 15.248000 ;
 RECT 0.480000 16.792000 82.724000 16.868000 ;
 RECT 0.480000 18.412000 82.724000 18.488000 ;
 RECT 0.480000 2.212000 82.724000 2.288000 ;
 RECT 0.480000 20.032000 82.724000 20.108000 ;
 RECT 0.480000 21.652000 82.724000 21.728000 ;
 RECT 0.480000 23.272000 82.724000 23.348000 ;
 RECT 0.480000 24.892000 82.724000 24.968000 ;
 RECT 0.480000 26.512000 82.724000 26.588000 ;
 RECT 0.480000 28.132000 82.724000 28.208000 ;
 RECT 0.480000 29.752000 82.724000 29.828000 ;
 RECT 0.480000 3.832000 82.724000 3.908000 ;
 RECT 0.480000 31.372000 82.724000 31.448000 ;
 RECT 0.480000 32.992000 82.724000 33.068000 ;
 RECT 0.480000 34.612000 82.724000 34.688000 ;
 RECT 0.480000 36.232000 82.724000 36.308000 ;
 RECT 0.480000 37.852000 82.724000 37.928000 ;
 RECT 0.480000 39.472000 82.724000 39.548000 ;
 RECT 0.480000 41.092000 82.724000 41.168000 ;
 RECT 0.480000 42.712000 82.724000 42.788000 ;
 RECT 0.480000 44.332000 82.724000 44.408000 ;
 RECT 0.480000 45.952000 82.724000 46.028000 ;
 RECT 0.480000 47.572000 82.724000 47.648000 ;
 RECT 0.480000 49.192000 82.724000 49.268000 ;
 RECT 0.480000 5.452000 82.724000 5.528000 ;
 RECT 0.480000 50.812000 82.724000 50.888000 ;
 RECT 0.480000 52.432000 82.724000 52.508000 ;
 RECT 0.480000 65.032000 82.724000 65.108000 ;
 RECT 0.480000 66.652000 82.724000 66.728000 ;
 RECT 0.480000 68.272000 82.724000 68.348000 ;
 RECT 0.480000 69.892000 82.724000 69.968000 ;
 RECT 0.480000 7.072000 82.724000 7.148000 ;
 RECT 0.480000 71.512000 82.724000 71.588000 ;
 RECT 0.480000 73.132000 82.724000 73.208000 ;
 RECT 0.480000 74.752000 82.724000 74.828000 ;
 RECT 0.480000 76.372000 82.724000 76.448000 ;
 RECT 0.480000 77.992000 82.724000 78.068000 ;
 RECT 0.480000 79.612000 82.724000 79.688000 ;
 RECT 0.480000 8.692000 82.724000 8.768000 ;
 RECT 0.480000 81.232000 82.724000 81.308000 ;
 RECT 0.480000 82.852000 82.724000 82.928000 ;
 RECT 0.480000 84.472000 82.724000 84.548000 ;
 RECT 0.480000 86.092000 82.724000 86.168000 ;
 RECT 0.480000 87.712000 82.724000 87.788000 ;
 RECT 0.480000 89.332000 82.724000 89.408000 ;
 RECT 0.480000 90.952000 82.724000 91.028000 ;
 RECT 0.480000 92.572000 82.724000 92.648000 ;
 RECT 0.480000 94.192000 82.724000 94.268000 ;
 RECT 0.480000 95.812000 82.724000 95.888000 ;
 RECT 0.480000 97.432000 82.724000 97.508000 ;
 RECT 0.480000 99.052000 82.724000 99.128000 ;
 RECT 0.616000 53.092000 54.292000 53.200000 ;
 RECT 0.616000 53.388000 54.292000 53.496000 ;
 RECT 0.616000 55.464000 54.292000 55.572000 ;
 RECT 0.616000 56.486000 29.560000 56.530000 ;
 RECT 0.616000 56.902000 54.292000 56.946000 ;
 RECT 0.616000 58.000000 54.292000 58.076000 ;
 RECT 0.616000 59.334000 54.292000 59.378000 ;
 RECT 0.616000 59.750000 29.560000 59.794000 ;
 RECT 0.616000 60.684000 54.292000 60.792000 ;
 RECT 0.616000 62.760000 54.292000 62.868000 ;
 RECT 0.616000 63.056000 54.292000 63.164000 ;
 RECT 0.616000 63.880000 54.292000 63.988000 ;
 RECT 0.616000 64.472000 54.292000 64.580000 ;
 RECT 29.687500 56.474000 53.479500 56.530000 ;
 RECT 29.718500 59.756000 53.563500 59.812000 ;
 RECT 32.813500 1.602000 53.388000 1.678000 ;
 RECT 32.813500 100.062000 53.360000 100.138000 ;
 RECT 32.813500 101.682000 53.388000 101.758000 ;
 RECT 32.813500 103.302000 53.360000 103.378000 ;
 RECT 32.813500 104.922000 53.388000 104.998000 ;
 RECT 32.813500 106.542000 53.360000 106.618000 ;
 RECT 32.813500 108.162000 53.388000 108.238000 ;
 RECT 32.813500 109.782000 53.360000 109.858000 ;
 RECT 32.813500 11.322000 53.388000 11.398000 ;
 RECT 32.813500 111.402000 53.388000 111.478000 ;
 RECT 32.813500 113.022000 53.360000 113.098000 ;
 RECT 32.813500 114.642000 53.388000 114.718000 ;
 RECT 32.813500 116.262000 53.360000 116.338000 ;
 RECT 32.813500 12.942000 53.360000 13.018000 ;
 RECT 32.813500 14.562000 53.388000 14.638000 ;
 RECT 32.813500 16.182000 53.360000 16.258000 ;
 RECT 32.813500 17.802000 53.388000 17.878000 ;
 RECT 32.813500 19.422000 53.360000 19.498000 ;
 RECT 32.813500 21.042000 53.388000 21.118000 ;
 RECT 32.813500 22.662000 53.360000 22.738000 ;
 RECT 32.813500 24.282000 53.388000 24.358000 ;
 RECT 32.813500 25.902000 53.360000 25.978000 ;
 RECT 32.813500 27.522000 53.388000 27.598000 ;
 RECT 32.813500 29.142000 53.360000 29.218000 ;
 RECT 32.813500 3.222000 53.360000 3.298000 ;
 RECT 32.813500 30.762000 53.388000 30.838000 ;
 RECT 32.813500 32.382000 53.360000 32.458000 ;
 RECT 32.813500 34.002000 53.388000 34.078000 ;
 RECT 32.813500 35.622000 53.360000 35.698000 ;
 RECT 32.813500 37.242000 53.388000 37.318000 ;
 RECT 32.813500 38.862000 53.360000 38.938000 ;
 RECT 32.813500 4.842000 53.388000 4.918000 ;
 RECT 32.813500 40.482000 53.388000 40.558000 ;
 RECT 32.813500 42.102000 53.360000 42.178000 ;
 RECT 32.813500 43.722000 53.388000 43.798000 ;
 RECT 32.813500 45.342000 53.360000 45.418000 ;
 RECT 32.813500 46.962000 53.388000 47.038000 ;
 RECT 32.813500 48.582000 53.360000 48.658000 ;
 RECT 32.813500 50.202000 53.388000 50.278000 ;
 RECT 32.813500 51.822000 53.360000 51.898000 ;
 RECT 32.813500 6.462000 53.360000 6.538000 ;
 RECT 32.813500 66.042000 53.388000 66.118000 ;
 RECT 32.813500 67.662000 53.360000 67.738000 ;
 RECT 32.813500 69.282000 53.388000 69.358000 ;
 RECT 32.813500 70.902000 53.360000 70.978000 ;
 RECT 32.813500 72.522000 53.388000 72.598000 ;
 RECT 32.813500 74.142000 53.360000 74.218000 ;
 RECT 32.813500 75.762000 53.388000 75.838000 ;
 RECT 32.813500 77.382000 53.360000 77.458000 ;
 RECT 32.813500 79.002000 53.388000 79.078000 ;
 RECT 32.813500 8.082000 53.388000 8.158000 ;
 RECT 32.813500 80.622000 53.360000 80.698000 ;
 RECT 32.813500 82.242000 53.388000 82.318000 ;
 RECT 32.813500 83.862000 53.360000 83.938000 ;
 RECT 32.813500 85.482000 53.388000 85.558000 ;
 RECT 32.813500 87.102000 53.360000 87.178000 ;
 RECT 32.813500 88.722000 53.388000 88.798000 ;
 RECT 32.813500 9.702000 53.360000 9.778000 ;
 RECT 32.813500 90.342000 53.360000 90.418000 ;
 RECT 32.813500 91.962000 53.388000 92.038000 ;
 RECT 32.813500 93.582000 53.360000 93.658000 ;
 RECT 32.813500 95.202000 53.388000 95.278000 ;
 RECT 32.813500 96.822000 53.360000 96.898000 ;
 RECT 32.813500 98.442000 53.388000 98.518000 ;
 END
 END vss
 PIN vccperfgt_lv
 DIRECTION INOUT ;
 USE POWER ;
 PORT
 LAYER m1 ;
 RECT 32.874000 13.658000 32.942000 15.142000 ;
 RECT 33.090000 13.658000 33.158000 15.142000 ;
 RECT 33.306000 14.288000 33.374000 15.142000 ;
 RECT 33.522000 14.288000 33.590000 15.142000 ;
 RECT 49.614000 68.378000 49.682000 69.232000 ;
 RECT 49.830000 68.378000 49.898000 69.232000 ;
 RECT 50.046000 68.378000 50.114000 69.862000 ;
 RECT 50.262000 68.378000 50.330000 69.862000 ;
 RECT 49.614000 69.998000 49.682000 70.852000 ;
 RECT 49.830000 69.998000 49.898000 70.852000 ;
 RECT 50.046000 69.998000 50.114000 71.482000 ;
 RECT 50.262000 69.998000 50.330000 71.482000 ;
 RECT 49.614000 71.618000 49.682000 72.472000 ;
 RECT 49.830000 71.618000 49.898000 72.472000 ;
 RECT 50.046000 71.618000 50.114000 73.102000 ;
 RECT 50.262000 71.618000 50.330000 73.102000 ;
 RECT 49.614000 73.238000 49.682000 74.092000 ;
 RECT 49.830000 73.238000 49.898000 74.092000 ;
 RECT 50.046000 73.238000 50.114000 74.722000 ;
 RECT 50.262000 73.238000 50.330000 74.722000 ;
 RECT 49.614000 74.858000 49.682000 75.712000 ;
 RECT 49.830000 74.858000 49.898000 75.712000 ;
 RECT 50.046000 74.858000 50.114000 76.342000 ;
 RECT 50.262000 74.858000 50.330000 76.342000 ;
 RECT 49.614000 76.478000 49.682000 77.332000 ;
 RECT 49.830000 76.478000 49.898000 77.332000 ;
 RECT 50.046000 76.478000 50.114000 77.962000 ;
 RECT 50.262000 76.478000 50.330000 77.962000 ;
 RECT 49.614000 78.098000 49.682000 78.952000 ;
 RECT 49.830000 78.098000 49.898000 78.952000 ;
 RECT 50.046000 78.098000 50.114000 79.582000 ;
 RECT 50.262000 78.098000 50.330000 79.582000 ;
 RECT 49.614000 79.718000 49.682000 80.572000 ;
 RECT 49.830000 79.718000 49.898000 80.572000 ;
 RECT 50.046000 79.718000 50.114000 81.202000 ;
 RECT 50.262000 79.718000 50.330000 81.202000 ;
 RECT 49.614000 81.338000 49.682000 82.192000 ;
 RECT 49.830000 81.338000 49.898000 82.192000 ;
 RECT 50.046000 81.338000 50.114000 82.822000 ;
 RECT 50.262000 81.338000 50.330000 82.822000 ;
 RECT 49.614000 82.958000 49.682000 83.812000 ;
 RECT 49.830000 82.958000 49.898000 83.812000 ;
 RECT 50.046000 82.958000 50.114000 84.442000 ;
 RECT 50.262000 82.958000 50.330000 84.442000 ;
 RECT 32.874000 15.278000 32.942000 16.762000 ;
 RECT 33.090000 15.278000 33.158000 16.762000 ;
 RECT 33.306000 15.908000 33.374000 16.762000 ;
 RECT 33.522000 15.908000 33.590000 16.762000 ;
 RECT 49.614000 84.578000 49.682000 85.432000 ;
 RECT 49.830000 84.578000 49.898000 85.432000 ;
 RECT 50.046000 84.578000 50.114000 86.062000 ;
 RECT 50.262000 84.578000 50.330000 86.062000 ;
 RECT 49.614000 86.198000 49.682000 87.052000 ;
 RECT 49.830000 86.198000 49.898000 87.052000 ;
 RECT 50.046000 86.198000 50.114000 87.682000 ;
 RECT 50.262000 86.198000 50.330000 87.682000 ;
 RECT 49.614000 87.818000 49.682000 88.672000 ;
 RECT 49.830000 87.818000 49.898000 88.672000 ;
 RECT 50.046000 87.818000 50.114000 89.302000 ;
 RECT 50.262000 87.818000 50.330000 89.302000 ;
 RECT 49.614000 89.438000 49.682000 90.292000 ;
 RECT 49.830000 89.438000 49.898000 90.292000 ;
 RECT 50.046000 89.438000 50.114000 90.922000 ;
 RECT 50.262000 89.438000 50.330000 90.922000 ;
 RECT 49.614000 91.058000 49.682000 91.912000 ;
 RECT 49.830000 91.058000 49.898000 91.912000 ;
 RECT 50.046000 91.058000 50.114000 92.542000 ;
 RECT 50.262000 91.058000 50.330000 92.542000 ;
 RECT 49.614000 92.678000 49.682000 93.532000 ;
 RECT 49.830000 92.678000 49.898000 93.532000 ;
 RECT 50.046000 92.678000 50.114000 94.162000 ;
 RECT 50.262000 92.678000 50.330000 94.162000 ;
 RECT 49.614000 94.298000 49.682000 95.152000 ;
 RECT 49.830000 94.298000 49.898000 95.152000 ;
 RECT 50.046000 94.298000 50.114000 95.782000 ;
 RECT 50.262000 94.298000 50.330000 95.782000 ;
 RECT 49.614000 95.918000 49.682000 96.772000 ;
 RECT 49.830000 95.918000 49.898000 96.772000 ;
 RECT 50.046000 95.918000 50.114000 97.402000 ;
 RECT 50.262000 95.918000 50.330000 97.402000 ;
 RECT 49.614000 97.538000 49.682000 98.392000 ;
 RECT 49.830000 97.538000 49.898000 98.392000 ;
 RECT 50.046000 97.538000 50.114000 99.022000 ;
 RECT 50.262000 97.538000 50.330000 99.022000 ;
 RECT 49.614000 99.158000 49.682000 100.012000 ;
 RECT 49.830000 99.158000 49.898000 100.012000 ;
 RECT 50.046000 99.158000 50.114000 100.642000 ;
 RECT 50.262000 99.158000 50.330000 100.642000 ;
 RECT 32.874000 16.898000 32.942000 18.382000 ;
 RECT 33.090000 16.898000 33.158000 18.382000 ;
 RECT 33.306000 17.528000 33.374000 18.382000 ;
 RECT 33.522000 17.528000 33.590000 18.382000 ;
 RECT 49.614000 100.778000 49.682000 101.632000 ;
 RECT 49.830000 100.778000 49.898000 101.632000 ;
 RECT 50.046000 100.778000 50.114000 102.262000 ;
 RECT 50.262000 100.778000 50.330000 102.262000 ;
 RECT 49.614000 102.398000 49.682000 103.252000 ;
 RECT 49.830000 102.398000 49.898000 103.252000 ;
 RECT 50.046000 102.398000 50.114000 103.882000 ;
 RECT 50.262000 102.398000 50.330000 103.882000 ;
 RECT 49.614000 104.018000 49.682000 104.872000 ;
 RECT 49.830000 104.018000 49.898000 104.872000 ;
 RECT 50.046000 104.018000 50.114000 105.502000 ;
 RECT 50.262000 104.018000 50.330000 105.502000 ;
 RECT 49.614000 105.638000 49.682000 106.492000 ;
 RECT 49.830000 105.638000 49.898000 106.492000 ;
 RECT 50.046000 105.638000 50.114000 107.122000 ;
 RECT 50.262000 105.638000 50.330000 107.122000 ;
 RECT 49.614000 107.258000 49.682000 108.112000 ;
 RECT 49.830000 107.258000 49.898000 108.112000 ;
 RECT 50.046000 107.258000 50.114000 108.742000 ;
 RECT 50.262000 107.258000 50.330000 108.742000 ;
 RECT 49.614000 108.878000 49.682000 109.732000 ;
 RECT 49.830000 108.878000 49.898000 109.732000 ;
 RECT 50.046000 108.878000 50.114000 110.362000 ;
 RECT 50.262000 108.878000 50.330000 110.362000 ;
 RECT 49.614000 110.498000 49.682000 111.352000 ;
 RECT 49.830000 110.498000 49.898000 111.352000 ;
 RECT 50.046000 110.498000 50.114000 111.982000 ;
 RECT 50.262000 110.498000 50.330000 111.982000 ;
 RECT 49.614000 112.118000 49.682000 112.972000 ;
 RECT 49.830000 112.118000 49.898000 112.972000 ;
 RECT 50.046000 112.118000 50.114000 113.602000 ;
 RECT 50.262000 112.118000 50.330000 113.602000 ;
 RECT 49.614000 113.738000 49.682000 114.592000 ;
 RECT 49.830000 113.738000 49.898000 114.592000 ;
 RECT 50.046000 113.738000 50.114000 115.222000 ;
 RECT 50.262000 113.738000 50.330000 115.222000 ;
 RECT 49.614000 115.358000 49.682000 116.212000 ;
 RECT 49.830000 115.358000 49.898000 116.212000 ;
 RECT 50.046000 115.358000 50.114000 116.842000 ;
 RECT 50.262000 115.358000 50.330000 116.842000 ;
 RECT 32.874000 18.518000 32.942000 20.002000 ;
 RECT 33.090000 18.518000 33.158000 20.002000 ;
 RECT 33.306000 19.148000 33.374000 20.002000 ;
 RECT 33.522000 19.148000 33.590000 20.002000 ;
 RECT 1.230000 57.037000 1.298000 57.555000 ;
 RECT 1.986000 57.083000 2.054000 57.577000 ;
 RECT 2.202000 57.083000 2.270000 57.577000 ;
 RECT 2.958000 57.037000 3.026000 57.555000 ;
 RECT 1.230000 58.725000 1.298000 59.243000 ;
 RECT 1.986000 58.703000 2.054000 59.197000 ;
 RECT 2.202000 58.703000 2.270000 59.197000 ;
 RECT 2.958000 58.725000 3.026000 59.243000 ;
 RECT 2.958000 57.037000 3.026000 57.555000 ;
 RECT 3.714000 57.083000 3.782000 57.577000 ;
 RECT 3.930000 57.083000 3.998000 57.577000 ;
 RECT 4.686000 57.037000 4.754000 57.555000 ;
 RECT 2.958000 58.725000 3.026000 59.243000 ;
 RECT 3.714000 58.703000 3.782000 59.197000 ;
 RECT 3.930000 58.703000 3.998000 59.197000 ;
 RECT 4.686000 58.725000 4.754000 59.243000 ;
 RECT 4.686000 57.037000 4.754000 57.555000 ;
 RECT 5.442000 57.083000 5.510000 57.577000 ;
 RECT 5.658000 57.083000 5.726000 57.577000 ;
 RECT 6.414000 57.037000 6.482000 57.555000 ;
 RECT 4.686000 58.725000 4.754000 59.243000 ;
 RECT 5.442000 58.703000 5.510000 59.197000 ;
 RECT 5.658000 58.703000 5.726000 59.197000 ;
 RECT 6.414000 58.725000 6.482000 59.243000 ;
 RECT 6.414000 57.037000 6.482000 57.555000 ;
 RECT 7.170000 57.083000 7.238000 57.577000 ;
 RECT 7.386000 57.083000 7.454000 57.577000 ;
 RECT 8.142000 57.037000 8.210000 57.555000 ;
 RECT 6.414000 58.725000 6.482000 59.243000 ;
 RECT 7.170000 58.703000 7.238000 59.197000 ;
 RECT 7.386000 58.703000 7.454000 59.197000 ;
 RECT 8.142000 58.725000 8.210000 59.243000 ;
 RECT 8.142000 57.037000 8.210000 57.555000 ;
 RECT 8.898000 57.083000 8.966000 57.577000 ;
 RECT 9.114000 57.083000 9.182000 57.577000 ;
 RECT 9.870000 57.037000 9.938000 57.555000 ;
 RECT 8.142000 58.725000 8.210000 59.243000 ;
 RECT 8.898000 58.703000 8.966000 59.197000 ;
 RECT 9.114000 58.703000 9.182000 59.197000 ;
 RECT 9.870000 58.725000 9.938000 59.243000 ;
 RECT 32.874000 20.138000 32.942000 21.622000 ;
 RECT 33.090000 20.138000 33.158000 21.622000 ;
 RECT 33.306000 20.768000 33.374000 21.622000 ;
 RECT 33.522000 20.768000 33.590000 21.622000 ;
 RECT 9.870000 57.037000 9.938000 57.555000 ;
 RECT 10.626000 57.083000 10.694000 57.577000 ;
 RECT 10.842000 57.083000 10.910000 57.577000 ;
 RECT 11.598000 57.037000 11.666000 57.555000 ;
 RECT 9.870000 58.725000 9.938000 59.243000 ;
 RECT 10.626000 58.703000 10.694000 59.197000 ;
 RECT 10.842000 58.703000 10.910000 59.197000 ;
 RECT 11.598000 58.725000 11.666000 59.243000 ;
 RECT 11.598000 57.037000 11.666000 57.555000 ;
 RECT 12.354000 57.083000 12.422000 57.577000 ;
 RECT 12.570000 57.083000 12.638000 57.577000 ;
 RECT 13.326000 57.037000 13.394000 57.555000 ;
 RECT 11.598000 58.725000 11.666000 59.243000 ;
 RECT 12.354000 58.703000 12.422000 59.197000 ;
 RECT 12.570000 58.703000 12.638000 59.197000 ;
 RECT 13.326000 58.725000 13.394000 59.243000 ;
 RECT 13.326000 57.037000 13.394000 57.555000 ;
 RECT 14.082000 57.083000 14.150000 57.577000 ;
 RECT 14.298000 57.083000 14.366000 57.577000 ;
 RECT 15.054000 57.037000 15.122000 57.555000 ;
 RECT 13.326000 58.725000 13.394000 59.243000 ;
 RECT 14.082000 58.703000 14.150000 59.197000 ;
 RECT 14.298000 58.703000 14.366000 59.197000 ;
 RECT 15.054000 58.725000 15.122000 59.243000 ;
 RECT 15.054000 57.037000 15.122000 57.555000 ;
 RECT 15.810000 57.083000 15.878000 57.577000 ;
 RECT 16.026000 57.083000 16.094000 57.577000 ;
 RECT 16.782000 57.037000 16.850000 57.555000 ;
 RECT 15.054000 58.725000 15.122000 59.243000 ;
 RECT 15.810000 58.703000 15.878000 59.197000 ;
 RECT 16.026000 58.703000 16.094000 59.197000 ;
 RECT 16.782000 58.725000 16.850000 59.243000 ;
 RECT 16.782000 57.037000 16.850000 57.555000 ;
 RECT 17.538000 57.083000 17.606000 57.577000 ;
 RECT 17.754000 57.083000 17.822000 57.577000 ;
 RECT 18.510000 57.037000 18.578000 57.555000 ;
 RECT 16.782000 58.725000 16.850000 59.243000 ;
 RECT 17.538000 58.703000 17.606000 59.197000 ;
 RECT 17.754000 58.703000 17.822000 59.197000 ;
 RECT 18.510000 58.725000 18.578000 59.243000 ;
 RECT 32.874000 21.758000 32.942000 23.242000 ;
 RECT 33.090000 21.758000 33.158000 23.242000 ;
 RECT 33.306000 22.388000 33.374000 23.242000 ;
 RECT 33.522000 22.388000 33.590000 23.242000 ;
 RECT 18.510000 57.037000 18.578000 57.555000 ;
 RECT 19.266000 57.083000 19.334000 57.577000 ;
 RECT 19.482000 57.083000 19.550000 57.577000 ;
 RECT 20.238000 57.037000 20.306000 57.555000 ;
 RECT 18.510000 58.725000 18.578000 59.243000 ;
 RECT 19.266000 58.703000 19.334000 59.197000 ;
 RECT 19.482000 58.703000 19.550000 59.197000 ;
 RECT 20.238000 58.725000 20.306000 59.243000 ;
 RECT 20.238000 57.037000 20.306000 57.555000 ;
 RECT 20.994000 57.083000 21.062000 57.577000 ;
 RECT 21.210000 57.083000 21.278000 57.577000 ;
 RECT 21.966000 57.037000 22.034000 57.555000 ;
 RECT 20.238000 58.725000 20.306000 59.243000 ;
 RECT 20.994000 58.703000 21.062000 59.197000 ;
 RECT 21.210000 58.703000 21.278000 59.197000 ;
 RECT 21.966000 58.725000 22.034000 59.243000 ;
 RECT 21.966000 57.037000 22.034000 57.555000 ;
 RECT 22.722000 57.083000 22.790000 57.577000 ;
 RECT 22.938000 57.083000 23.006000 57.577000 ;
 RECT 23.694000 57.037000 23.762000 57.555000 ;
 RECT 21.966000 58.725000 22.034000 59.243000 ;
 RECT 22.722000 58.703000 22.790000 59.197000 ;
 RECT 22.938000 58.703000 23.006000 59.197000 ;
 RECT 23.694000 58.725000 23.762000 59.243000 ;
 RECT 23.694000 57.037000 23.762000 57.555000 ;
 RECT 24.450000 57.083000 24.518000 57.577000 ;
 RECT 24.666000 57.083000 24.734000 57.577000 ;
 RECT 25.422000 57.037000 25.490000 57.555000 ;
 RECT 23.694000 58.725000 23.762000 59.243000 ;
 RECT 24.450000 58.703000 24.518000 59.197000 ;
 RECT 24.666000 58.703000 24.734000 59.197000 ;
 RECT 25.422000 58.725000 25.490000 59.243000 ;
 RECT 25.422000 57.037000 25.490000 57.555000 ;
 RECT 26.178000 57.083000 26.246000 57.577000 ;
 RECT 26.394000 57.083000 26.462000 57.577000 ;
 RECT 27.150000 57.037000 27.218000 57.555000 ;
 RECT 25.422000 58.725000 25.490000 59.243000 ;
 RECT 26.178000 58.703000 26.246000 59.197000 ;
 RECT 26.394000 58.703000 26.462000 59.197000 ;
 RECT 27.150000 58.725000 27.218000 59.243000 ;
 RECT 32.874000 23.378000 32.942000 24.862000 ;
 RECT 33.090000 23.378000 33.158000 24.862000 ;
 RECT 33.306000 24.008000 33.374000 24.862000 ;
 RECT 33.522000 24.008000 33.590000 24.862000 ;
 RECT 27.150000 57.037000 27.218000 57.555000 ;
 RECT 27.906000 57.083000 27.974000 57.577000 ;
 RECT 28.122000 57.083000 28.190000 57.577000 ;
 RECT 28.878000 57.037000 28.946000 57.555000 ;
 RECT 27.150000 58.725000 27.218000 59.243000 ;
 RECT 27.906000 58.703000 27.974000 59.197000 ;
 RECT 28.122000 58.703000 28.190000 59.197000 ;
 RECT 28.878000 58.725000 28.946000 59.243000 ;
 RECT 55.986000 57.037000 56.054000 57.555000 ;
 RECT 55.230000 57.083000 55.298000 57.577000 ;
 RECT 55.014000 57.083000 55.082000 57.577000 ;
 RECT 54.258000 57.037000 54.326000 57.555000 ;
 RECT 55.986000 58.725000 56.054000 59.243000 ;
 RECT 55.230000 58.703000 55.298000 59.197000 ;
 RECT 55.014000 58.703000 55.082000 59.197000 ;
 RECT 54.258000 58.725000 54.326000 59.243000 ;
 RECT 57.714000 57.037000 57.782000 57.555000 ;
 RECT 56.958000 57.083000 57.026000 57.577000 ;
 RECT 56.742000 57.083000 56.810000 57.577000 ;
 RECT 55.986000 57.037000 56.054000 57.555000 ;
 RECT 57.714000 58.725000 57.782000 59.243000 ;
 RECT 56.958000 58.703000 57.026000 59.197000 ;
 RECT 56.742000 58.703000 56.810000 59.197000 ;
 RECT 55.986000 58.725000 56.054000 59.243000 ;
 RECT 59.442000 57.037000 59.510000 57.555000 ;
 RECT 58.686000 57.083000 58.754000 57.577000 ;
 RECT 58.470000 57.083000 58.538000 57.577000 ;
 RECT 57.714000 57.037000 57.782000 57.555000 ;
 RECT 59.442000 58.725000 59.510000 59.243000 ;
 RECT 58.686000 58.703000 58.754000 59.197000 ;
 RECT 58.470000 58.703000 58.538000 59.197000 ;
 RECT 57.714000 58.725000 57.782000 59.243000 ;
 RECT 61.170000 57.037000 61.238000 57.555000 ;
 RECT 60.414000 57.083000 60.482000 57.577000 ;
 RECT 60.198000 57.083000 60.266000 57.577000 ;
 RECT 59.442000 57.037000 59.510000 57.555000 ;
 RECT 61.170000 58.725000 61.238000 59.243000 ;
 RECT 60.414000 58.703000 60.482000 59.197000 ;
 RECT 60.198000 58.703000 60.266000 59.197000 ;
 RECT 59.442000 58.725000 59.510000 59.243000 ;
 RECT 32.874000 24.998000 32.942000 26.482000 ;
 RECT 33.090000 24.998000 33.158000 26.482000 ;
 RECT 33.306000 25.628000 33.374000 26.482000 ;
 RECT 33.522000 25.628000 33.590000 26.482000 ;
 RECT 62.898000 57.037000 62.966000 57.555000 ;
 RECT 62.142000 57.083000 62.210000 57.577000 ;
 RECT 61.926000 57.083000 61.994000 57.577000 ;
 RECT 61.170000 57.037000 61.238000 57.555000 ;
 RECT 62.898000 58.725000 62.966000 59.243000 ;
 RECT 62.142000 58.703000 62.210000 59.197000 ;
 RECT 61.926000 58.703000 61.994000 59.197000 ;
 RECT 61.170000 58.725000 61.238000 59.243000 ;
 RECT 64.626000 57.037000 64.694000 57.555000 ;
 RECT 63.870000 57.083000 63.938000 57.577000 ;
 RECT 63.654000 57.083000 63.722000 57.577000 ;
 RECT 62.898000 57.037000 62.966000 57.555000 ;
 RECT 64.626000 58.725000 64.694000 59.243000 ;
 RECT 63.870000 58.703000 63.938000 59.197000 ;
 RECT 63.654000 58.703000 63.722000 59.197000 ;
 RECT 62.898000 58.725000 62.966000 59.243000 ;
 RECT 66.354000 57.037000 66.422000 57.555000 ;
 RECT 65.598000 57.083000 65.666000 57.577000 ;
 RECT 65.382000 57.083000 65.450000 57.577000 ;
 RECT 64.626000 57.037000 64.694000 57.555000 ;
 RECT 66.354000 58.725000 66.422000 59.243000 ;
 RECT 65.598000 58.703000 65.666000 59.197000 ;
 RECT 65.382000 58.703000 65.450000 59.197000 ;
 RECT 64.626000 58.725000 64.694000 59.243000 ;
 RECT 68.082000 57.037000 68.150000 57.555000 ;
 RECT 67.326000 57.083000 67.394000 57.577000 ;
 RECT 67.110000 57.083000 67.178000 57.577000 ;
 RECT 66.354000 57.037000 66.422000 57.555000 ;
 RECT 68.082000 58.725000 68.150000 59.243000 ;
 RECT 67.326000 58.703000 67.394000 59.197000 ;
 RECT 67.110000 58.703000 67.178000 59.197000 ;
 RECT 66.354000 58.725000 66.422000 59.243000 ;
 RECT 69.810000 57.037000 69.878000 57.555000 ;
 RECT 69.054000 57.083000 69.122000 57.577000 ;
 RECT 68.838000 57.083000 68.906000 57.577000 ;
 RECT 68.082000 57.037000 68.150000 57.555000 ;
 RECT 69.810000 58.725000 69.878000 59.243000 ;
 RECT 69.054000 58.703000 69.122000 59.197000 ;
 RECT 68.838000 58.703000 68.906000 59.197000 ;
 RECT 68.082000 58.725000 68.150000 59.243000 ;
 RECT 32.874000 26.618000 32.942000 28.102000 ;
 RECT 33.090000 26.618000 33.158000 28.102000 ;
 RECT 33.306000 27.248000 33.374000 28.102000 ;
 RECT 33.522000 27.248000 33.590000 28.102000 ;
 RECT 71.538000 57.037000 71.606000 57.555000 ;
 RECT 70.782000 57.083000 70.850000 57.577000 ;
 RECT 70.566000 57.083000 70.634000 57.577000 ;
 RECT 69.810000 57.037000 69.878000 57.555000 ;
 RECT 71.538000 58.725000 71.606000 59.243000 ;
 RECT 70.782000 58.703000 70.850000 59.197000 ;
 RECT 70.566000 58.703000 70.634000 59.197000 ;
 RECT 69.810000 58.725000 69.878000 59.243000 ;
 RECT 73.266000 57.037000 73.334000 57.555000 ;
 RECT 72.510000 57.083000 72.578000 57.577000 ;
 RECT 72.294000 57.083000 72.362000 57.577000 ;
 RECT 71.538000 57.037000 71.606000 57.555000 ;
 RECT 73.266000 58.725000 73.334000 59.243000 ;
 RECT 72.510000 58.703000 72.578000 59.197000 ;
 RECT 72.294000 58.703000 72.362000 59.197000 ;
 RECT 71.538000 58.725000 71.606000 59.243000 ;
 RECT 74.994000 57.037000 75.062000 57.555000 ;
 RECT 74.238000 57.083000 74.306000 57.577000 ;
 RECT 74.022000 57.083000 74.090000 57.577000 ;
 RECT 73.266000 57.037000 73.334000 57.555000 ;
 RECT 74.994000 58.725000 75.062000 59.243000 ;
 RECT 74.238000 58.703000 74.306000 59.197000 ;
 RECT 74.022000 58.703000 74.090000 59.197000 ;
 RECT 73.266000 58.725000 73.334000 59.243000 ;
 RECT 76.722000 57.037000 76.790000 57.555000 ;
 RECT 75.966000 57.083000 76.034000 57.577000 ;
 RECT 75.750000 57.083000 75.818000 57.577000 ;
 RECT 74.994000 57.037000 75.062000 57.555000 ;
 RECT 76.722000 58.725000 76.790000 59.243000 ;
 RECT 75.966000 58.703000 76.034000 59.197000 ;
 RECT 75.750000 58.703000 75.818000 59.197000 ;
 RECT 74.994000 58.725000 75.062000 59.243000 ;
 RECT 78.450000 57.037000 78.518000 57.555000 ;
 RECT 77.694000 57.083000 77.762000 57.577000 ;
 RECT 77.478000 57.083000 77.546000 57.577000 ;
 RECT 76.722000 57.037000 76.790000 57.555000 ;
 RECT 78.450000 58.725000 78.518000 59.243000 ;
 RECT 77.694000 58.703000 77.762000 59.197000 ;
 RECT 77.478000 58.703000 77.546000 59.197000 ;
 RECT 76.722000 58.725000 76.790000 59.243000 ;
 RECT 32.874000 28.238000 32.942000 29.722000 ;
 RECT 33.090000 28.238000 33.158000 29.722000 ;
 RECT 33.306000 28.868000 33.374000 29.722000 ;
 RECT 33.522000 28.868000 33.590000 29.722000 ;
 RECT 80.178000 57.037000 80.246000 57.555000 ;
 RECT 79.422000 57.083000 79.490000 57.577000 ;
 RECT 79.206000 57.083000 79.274000 57.577000 ;
 RECT 78.450000 57.037000 78.518000 57.555000 ;
 RECT 80.178000 58.725000 80.246000 59.243000 ;
 RECT 79.422000 58.703000 79.490000 59.197000 ;
 RECT 79.206000 58.703000 79.274000 59.197000 ;
 RECT 78.450000 58.725000 78.518000 59.243000 ;
 RECT 81.906000 57.037000 81.974000 57.555000 ;
 RECT 81.150000 57.083000 81.218000 57.577000 ;
 RECT 80.934000 57.083000 81.002000 57.577000 ;
 RECT 80.178000 57.037000 80.246000 57.555000 ;
 RECT 81.906000 58.725000 81.974000 59.243000 ;
 RECT 81.150000 58.703000 81.218000 59.197000 ;
 RECT 80.934000 58.703000 81.002000 59.197000 ;
 RECT 80.178000 58.725000 80.246000 59.243000 ;
 RECT 32.010000 53.798000 32.078000 55.012000 ;
 RECT 32.226000 53.798000 32.294000 55.012000 ;
 RECT 32.442000 54.280000 32.510000 55.012000 ;
 RECT 32.658000 54.248000 32.726000 55.012000 ;
 RECT 32.874000 54.248000 32.942000 55.012000 ;
 RECT 32.010000 55.058000 32.078000 56.272000 ;
 RECT 32.226000 55.058000 32.294000 56.272000 ;
 RECT 32.442000 55.540000 32.510000 56.272000 ;
 RECT 32.658000 55.508000 32.726000 56.272000 ;
 RECT 32.874000 55.508000 32.942000 56.272000 ;
 RECT 32.010000 56.318000 32.078000 57.532000 ;
 RECT 32.226000 56.318000 32.294000 57.532000 ;
 RECT 32.442000 56.800000 32.510000 57.532000 ;
 RECT 32.658000 56.768000 32.726000 57.532000 ;
 RECT 32.874000 56.768000 32.942000 57.532000 ;
 RECT 32.010000 57.578000 32.078000 58.792000 ;
 RECT 32.226000 57.578000 32.294000 58.792000 ;
 RECT 32.442000 58.060000 32.510000 58.792000 ;
 RECT 32.658000 58.028000 32.726000 58.792000 ;
 RECT 32.874000 58.028000 32.942000 58.792000 ;
 RECT 32.010000 58.838000 32.078000 60.052000 ;
 RECT 32.226000 58.838000 32.294000 60.052000 ;
 RECT 32.442000 59.320000 32.510000 60.052000 ;
 RECT 32.658000 59.288000 32.726000 60.052000 ;
 RECT 32.874000 59.288000 32.942000 60.052000 ;
 RECT 32.010000 60.098000 32.078000 61.312000 ;
 RECT 32.226000 60.098000 32.294000 61.312000 ;
 RECT 32.442000 60.580000 32.510000 61.312000 ;
 RECT 32.658000 60.548000 32.726000 61.312000 ;
 RECT 32.874000 60.548000 32.942000 61.312000 ;
 RECT 32.874000 0.698000 32.942000 2.182000 ;
 RECT 33.090000 0.698000 33.158000 2.182000 ;
 RECT 33.306000 1.328000 33.374000 2.182000 ;
 RECT 33.522000 1.328000 33.590000 2.182000 ;
 RECT 32.874000 29.858000 32.942000 31.342000 ;
 RECT 33.090000 29.858000 33.158000 31.342000 ;
 RECT 33.306000 30.488000 33.374000 31.342000 ;
 RECT 33.522000 30.488000 33.590000 31.342000 ;
 RECT 32.010000 61.358000 32.078000 62.572000 ;
 RECT 32.226000 61.358000 32.294000 62.572000 ;
 RECT 32.442000 61.840000 32.510000 62.572000 ;
 RECT 32.658000 61.808000 32.726000 62.572000 ;
 RECT 32.874000 61.808000 32.942000 62.572000 ;
 RECT 32.010000 62.618000 32.078000 63.832000 ;
 RECT 32.226000 62.618000 32.294000 63.832000 ;
 RECT 32.442000 63.100000 32.510000 63.832000 ;
 RECT 32.658000 63.068000 32.726000 63.832000 ;
 RECT 32.874000 63.068000 32.942000 63.832000 ;
 RECT 51.126000 53.708000 51.194000 54.922000 ;
 RECT 50.910000 53.708000 50.978000 54.922000 ;
 RECT 50.694000 53.708000 50.762000 54.440000 ;
 RECT 50.478000 53.708000 50.546000 54.472000 ;
 RECT 50.262000 53.708000 50.330000 54.472000 ;
 RECT 51.126000 54.968000 51.194000 56.182000 ;
 RECT 50.910000 54.968000 50.978000 56.182000 ;
 RECT 50.694000 54.968000 50.762000 55.700000 ;
 RECT 50.478000 54.968000 50.546000 55.732000 ;
 RECT 50.262000 54.968000 50.330000 55.732000 ;
 RECT 51.126000 56.228000 51.194000 57.442000 ;
 RECT 50.910000 56.228000 50.978000 57.442000 ;
 RECT 50.694000 56.228000 50.762000 56.960000 ;
 RECT 50.478000 56.228000 50.546000 56.992000 ;
 RECT 50.262000 56.228000 50.330000 56.992000 ;
 RECT 51.126000 57.488000 51.194000 58.702000 ;
 RECT 50.910000 57.488000 50.978000 58.702000 ;
 RECT 50.694000 57.488000 50.762000 58.220000 ;
 RECT 50.478000 57.488000 50.546000 58.252000 ;
 RECT 50.262000 57.488000 50.330000 58.252000 ;
 RECT 51.126000 58.748000 51.194000 59.962000 ;
 RECT 50.910000 58.748000 50.978000 59.962000 ;
 RECT 50.694000 58.748000 50.762000 59.480000 ;
 RECT 50.478000 58.748000 50.546000 59.512000 ;
 RECT 50.262000 58.748000 50.330000 59.512000 ;
 RECT 51.126000 60.008000 51.194000 61.222000 ;
 RECT 50.910000 60.008000 50.978000 61.222000 ;
 RECT 50.694000 60.008000 50.762000 60.740000 ;
 RECT 50.478000 60.008000 50.546000 60.772000 ;
 RECT 50.262000 60.008000 50.330000 60.772000 ;
 RECT 51.126000 61.268000 51.194000 62.482000 ;
 RECT 50.910000 61.268000 50.978000 62.482000 ;
 RECT 50.694000 61.268000 50.762000 62.000000 ;
 RECT 50.478000 61.268000 50.546000 62.032000 ;
 RECT 50.262000 61.268000 50.330000 62.032000 ;
 RECT 51.126000 62.528000 51.194000 63.742000 ;
 RECT 50.910000 62.528000 50.978000 63.742000 ;
 RECT 50.694000 62.528000 50.762000 63.260000 ;
 RECT 50.478000 62.528000 50.546000 63.292000 ;
 RECT 50.262000 62.528000 50.330000 63.292000 ;
 RECT 32.874000 31.478000 32.942000 32.962000 ;
 RECT 33.090000 31.478000 33.158000 32.962000 ;
 RECT 33.306000 32.108000 33.374000 32.962000 ;
 RECT 33.522000 32.108000 33.590000 32.962000 ;
 RECT 32.874000 33.098000 32.942000 34.582000 ;
 RECT 33.090000 33.098000 33.158000 34.582000 ;
 RECT 33.306000 33.728000 33.374000 34.582000 ;
 RECT 33.522000 33.728000 33.590000 34.582000 ;
 RECT 32.874000 34.718000 32.942000 36.202000 ;
 RECT 33.090000 34.718000 33.158000 36.202000 ;
 RECT 33.306000 35.348000 33.374000 36.202000 ;
 RECT 33.522000 35.348000 33.590000 36.202000 ;
 RECT 32.874000 36.338000 32.942000 37.822000 ;
 RECT 33.090000 36.338000 33.158000 37.822000 ;
 RECT 33.306000 36.968000 33.374000 37.822000 ;
 RECT 33.522000 36.968000 33.590000 37.822000 ;
 RECT 32.874000 37.958000 32.942000 39.442000 ;
 RECT 33.090000 37.958000 33.158000 39.442000 ;
 RECT 33.306000 38.588000 33.374000 39.442000 ;
 RECT 33.522000 38.588000 33.590000 39.442000 ;
 RECT 32.874000 39.578000 32.942000 41.062000 ;
 RECT 33.090000 39.578000 33.158000 41.062000 ;
 RECT 33.306000 40.208000 33.374000 41.062000 ;
 RECT 33.522000 40.208000 33.590000 41.062000 ;
 RECT 32.874000 41.198000 32.942000 42.682000 ;
 RECT 33.090000 41.198000 33.158000 42.682000 ;
 RECT 33.306000 41.828000 33.374000 42.682000 ;
 RECT 33.522000 41.828000 33.590000 42.682000 ;
 RECT 32.874000 42.818000 32.942000 44.302000 ;
 RECT 33.090000 42.818000 33.158000 44.302000 ;
 RECT 33.306000 43.448000 33.374000 44.302000 ;
 RECT 33.522000 43.448000 33.590000 44.302000 ;
 RECT 32.874000 44.438000 32.942000 45.922000 ;
 RECT 33.090000 44.438000 33.158000 45.922000 ;
 RECT 33.306000 45.068000 33.374000 45.922000 ;
 RECT 33.522000 45.068000 33.590000 45.922000 ;
 RECT 32.874000 2.318000 32.942000 3.802000 ;
 RECT 33.090000 2.318000 33.158000 3.802000 ;
 RECT 33.306000 2.948000 33.374000 3.802000 ;
 RECT 33.522000 2.948000 33.590000 3.802000 ;
 RECT 32.874000 46.058000 32.942000 47.542000 ;
 RECT 33.090000 46.058000 33.158000 47.542000 ;
 RECT 33.306000 46.688000 33.374000 47.542000 ;
 RECT 33.522000 46.688000 33.590000 47.542000 ;
 RECT 32.874000 47.678000 32.942000 49.162000 ;
 RECT 33.090000 47.678000 33.158000 49.162000 ;
 RECT 33.306000 48.308000 33.374000 49.162000 ;
 RECT 33.522000 48.308000 33.590000 49.162000 ;
 RECT 32.874000 49.298000 32.942000 50.782000 ;
 RECT 33.090000 49.298000 33.158000 50.782000 ;
 RECT 33.306000 49.928000 33.374000 50.782000 ;
 RECT 33.522000 49.928000 33.590000 50.782000 ;
 RECT 32.874000 50.918000 32.942000 52.402000 ;
 RECT 33.090000 50.918000 33.158000 52.402000 ;
 RECT 33.306000 51.548000 33.374000 52.402000 ;
 RECT 33.522000 51.548000 33.590000 52.402000 ;
 RECT 32.874000 65.138000 32.942000 66.622000 ;
 RECT 33.090000 65.138000 33.158000 66.622000 ;
 RECT 33.306000 65.768000 33.374000 66.622000 ;
 RECT 33.522000 65.768000 33.590000 66.622000 ;
 RECT 32.874000 66.758000 32.942000 68.242000 ;
 RECT 33.090000 66.758000 33.158000 68.242000 ;
 RECT 33.306000 67.388000 33.374000 68.242000 ;
 RECT 33.522000 67.388000 33.590000 68.242000 ;
 RECT 32.874000 68.378000 32.942000 69.862000 ;
 RECT 33.090000 68.378000 33.158000 69.862000 ;
 RECT 33.306000 69.008000 33.374000 69.862000 ;
 RECT 33.522000 69.008000 33.590000 69.862000 ;
 RECT 32.874000 69.998000 32.942000 71.482000 ;
 RECT 33.090000 69.998000 33.158000 71.482000 ;
 RECT 33.306000 70.628000 33.374000 71.482000 ;
 RECT 33.522000 70.628000 33.590000 71.482000 ;
 RECT 32.874000 71.618000 32.942000 73.102000 ;
 RECT 33.090000 71.618000 33.158000 73.102000 ;
 RECT 33.306000 72.248000 33.374000 73.102000 ;
 RECT 33.522000 72.248000 33.590000 73.102000 ;
 RECT 32.874000 73.238000 32.942000 74.722000 ;
 RECT 33.090000 73.238000 33.158000 74.722000 ;
 RECT 33.306000 73.868000 33.374000 74.722000 ;
 RECT 33.522000 73.868000 33.590000 74.722000 ;
 RECT 32.874000 3.938000 32.942000 5.422000 ;
 RECT 33.090000 3.938000 33.158000 5.422000 ;
 RECT 33.306000 4.568000 33.374000 5.422000 ;
 RECT 33.522000 4.568000 33.590000 5.422000 ;
 RECT 32.874000 74.858000 32.942000 76.342000 ;
 RECT 33.090000 74.858000 33.158000 76.342000 ;
 RECT 33.306000 75.488000 33.374000 76.342000 ;
 RECT 33.522000 75.488000 33.590000 76.342000 ;
 RECT 32.874000 76.478000 32.942000 77.962000 ;
 RECT 33.090000 76.478000 33.158000 77.962000 ;
 RECT 33.306000 77.108000 33.374000 77.962000 ;
 RECT 33.522000 77.108000 33.590000 77.962000 ;
 RECT 32.874000 78.098000 32.942000 79.582000 ;
 RECT 33.090000 78.098000 33.158000 79.582000 ;
 RECT 33.306000 78.728000 33.374000 79.582000 ;
 RECT 33.522000 78.728000 33.590000 79.582000 ;
 RECT 32.874000 79.718000 32.942000 81.202000 ;
 RECT 33.090000 79.718000 33.158000 81.202000 ;
 RECT 33.306000 80.348000 33.374000 81.202000 ;
 RECT 33.522000 80.348000 33.590000 81.202000 ;
 RECT 32.874000 81.338000 32.942000 82.822000 ;
 RECT 33.090000 81.338000 33.158000 82.822000 ;
 RECT 33.306000 81.968000 33.374000 82.822000 ;
 RECT 33.522000 81.968000 33.590000 82.822000 ;
 RECT 32.874000 82.958000 32.942000 84.442000 ;
 RECT 33.090000 82.958000 33.158000 84.442000 ;
 RECT 33.306000 83.588000 33.374000 84.442000 ;
 RECT 33.522000 83.588000 33.590000 84.442000 ;
 RECT 32.874000 84.578000 32.942000 86.062000 ;
 RECT 33.090000 84.578000 33.158000 86.062000 ;
 RECT 33.306000 85.208000 33.374000 86.062000 ;
 RECT 33.522000 85.208000 33.590000 86.062000 ;
 RECT 32.874000 86.198000 32.942000 87.682000 ;
 RECT 33.090000 86.198000 33.158000 87.682000 ;
 RECT 33.306000 86.828000 33.374000 87.682000 ;
 RECT 33.522000 86.828000 33.590000 87.682000 ;
 RECT 32.874000 87.818000 32.942000 89.302000 ;
 RECT 33.090000 87.818000 33.158000 89.302000 ;
 RECT 33.306000 88.448000 33.374000 89.302000 ;
 RECT 33.522000 88.448000 33.590000 89.302000 ;
 RECT 32.874000 89.438000 32.942000 90.922000 ;
 RECT 33.090000 89.438000 33.158000 90.922000 ;
 RECT 33.306000 90.068000 33.374000 90.922000 ;
 RECT 33.522000 90.068000 33.590000 90.922000 ;
 RECT 32.874000 5.558000 32.942000 7.042000 ;
 RECT 33.090000 5.558000 33.158000 7.042000 ;
 RECT 33.306000 6.188000 33.374000 7.042000 ;
 RECT 33.522000 6.188000 33.590000 7.042000 ;
 RECT 32.874000 91.058000 32.942000 92.542000 ;
 RECT 33.090000 91.058000 33.158000 92.542000 ;
 RECT 33.306000 91.688000 33.374000 92.542000 ;
 RECT 33.522000 91.688000 33.590000 92.542000 ;
 RECT 32.874000 92.678000 32.942000 94.162000 ;
 RECT 33.090000 92.678000 33.158000 94.162000 ;
 RECT 33.306000 93.308000 33.374000 94.162000 ;
 RECT 33.522000 93.308000 33.590000 94.162000 ;
 RECT 32.874000 94.298000 32.942000 95.782000 ;
 RECT 33.090000 94.298000 33.158000 95.782000 ;
 RECT 33.306000 94.928000 33.374000 95.782000 ;
 RECT 33.522000 94.928000 33.590000 95.782000 ;
 RECT 32.874000 95.918000 32.942000 97.402000 ;
 RECT 33.090000 95.918000 33.158000 97.402000 ;
 RECT 33.306000 96.548000 33.374000 97.402000 ;
 RECT 33.522000 96.548000 33.590000 97.402000 ;
 RECT 32.874000 97.538000 32.942000 99.022000 ;
 RECT 33.090000 97.538000 33.158000 99.022000 ;
 RECT 33.306000 98.168000 33.374000 99.022000 ;
 RECT 33.522000 98.168000 33.590000 99.022000 ;
 RECT 32.874000 99.158000 32.942000 100.642000 ;
 RECT 33.090000 99.158000 33.158000 100.642000 ;
 RECT 33.306000 99.788000 33.374000 100.642000 ;
 RECT 33.522000 99.788000 33.590000 100.642000 ;
 RECT 32.874000 100.778000 32.942000 102.262000 ;
 RECT 33.090000 100.778000 33.158000 102.262000 ;
 RECT 33.306000 101.408000 33.374000 102.262000 ;
 RECT 33.522000 101.408000 33.590000 102.262000 ;
 RECT 32.874000 102.398000 32.942000 103.882000 ;
 RECT 33.090000 102.398000 33.158000 103.882000 ;
 RECT 33.306000 103.028000 33.374000 103.882000 ;
 RECT 33.522000 103.028000 33.590000 103.882000 ;
 RECT 32.874000 104.018000 32.942000 105.502000 ;
 RECT 33.090000 104.018000 33.158000 105.502000 ;
 RECT 33.306000 104.648000 33.374000 105.502000 ;
 RECT 33.522000 104.648000 33.590000 105.502000 ;
 RECT 32.874000 105.638000 32.942000 107.122000 ;
 RECT 33.090000 105.638000 33.158000 107.122000 ;
 RECT 33.306000 106.268000 33.374000 107.122000 ;
 RECT 33.522000 106.268000 33.590000 107.122000 ;
 RECT 32.874000 7.178000 32.942000 8.662000 ;
 RECT 33.090000 7.178000 33.158000 8.662000 ;
 RECT 33.306000 7.808000 33.374000 8.662000 ;
 RECT 33.522000 7.808000 33.590000 8.662000 ;
 RECT 32.874000 107.258000 32.942000 108.742000 ;
 RECT 33.090000 107.258000 33.158000 108.742000 ;
 RECT 33.306000 107.888000 33.374000 108.742000 ;
 RECT 33.522000 107.888000 33.590000 108.742000 ;
 RECT 32.874000 108.878000 32.942000 110.362000 ;
 RECT 33.090000 108.878000 33.158000 110.362000 ;
 RECT 33.306000 109.508000 33.374000 110.362000 ;
 RECT 33.522000 109.508000 33.590000 110.362000 ;
 RECT 32.874000 110.498000 32.942000 111.982000 ;
 RECT 33.090000 110.498000 33.158000 111.982000 ;
 RECT 33.306000 111.128000 33.374000 111.982000 ;
 RECT 33.522000 111.128000 33.590000 111.982000 ;
 RECT 32.874000 112.118000 32.942000 113.602000 ;
 RECT 33.090000 112.118000 33.158000 113.602000 ;
 RECT 33.306000 112.748000 33.374000 113.602000 ;
 RECT 33.522000 112.748000 33.590000 113.602000 ;
 RECT 32.874000 113.738000 32.942000 115.222000 ;
 RECT 33.090000 113.738000 33.158000 115.222000 ;
 RECT 33.306000 114.368000 33.374000 115.222000 ;
 RECT 33.522000 114.368000 33.590000 115.222000 ;
 RECT 32.874000 115.358000 32.942000 116.842000 ;
 RECT 33.090000 115.358000 33.158000 116.842000 ;
 RECT 33.306000 115.988000 33.374000 116.842000 ;
 RECT 33.522000 115.988000 33.590000 116.842000 ;
 RECT 49.614000 0.698000 49.682000 1.552000 ;
 RECT 49.830000 0.698000 49.898000 1.552000 ;
 RECT 50.046000 0.698000 50.114000 2.182000 ;
 RECT 50.262000 0.698000 50.330000 2.182000 ;
 RECT 49.614000 2.318000 49.682000 3.172000 ;
 RECT 49.830000 2.318000 49.898000 3.172000 ;
 RECT 50.046000 2.318000 50.114000 3.802000 ;
 RECT 50.262000 2.318000 50.330000 3.802000 ;
 RECT 49.614000 3.938000 49.682000 4.792000 ;
 RECT 49.830000 3.938000 49.898000 4.792000 ;
 RECT 50.046000 3.938000 50.114000 5.422000 ;
 RECT 50.262000 3.938000 50.330000 5.422000 ;
 RECT 49.614000 5.558000 49.682000 6.412000 ;
 RECT 49.830000 5.558000 49.898000 6.412000 ;
 RECT 50.046000 5.558000 50.114000 7.042000 ;
 RECT 50.262000 5.558000 50.330000 7.042000 ;
 RECT 32.874000 8.798000 32.942000 10.282000 ;
 RECT 33.090000 8.798000 33.158000 10.282000 ;
 RECT 33.306000 9.428000 33.374000 10.282000 ;
 RECT 33.522000 9.428000 33.590000 10.282000 ;
 RECT 49.614000 7.178000 49.682000 8.032000 ;
 RECT 49.830000 7.178000 49.898000 8.032000 ;
 RECT 50.046000 7.178000 50.114000 8.662000 ;
 RECT 50.262000 7.178000 50.330000 8.662000 ;
 RECT 49.614000 8.798000 49.682000 9.652000 ;
 RECT 49.830000 8.798000 49.898000 9.652000 ;
 RECT 50.046000 8.798000 50.114000 10.282000 ;
 RECT 50.262000 8.798000 50.330000 10.282000 ;
 RECT 49.614000 10.418000 49.682000 11.272000 ;
 RECT 49.830000 10.418000 49.898000 11.272000 ;
 RECT 50.046000 10.418000 50.114000 11.902000 ;
 RECT 50.262000 10.418000 50.330000 11.902000 ;
 RECT 49.614000 12.038000 49.682000 12.892000 ;
 RECT 49.830000 12.038000 49.898000 12.892000 ;
 RECT 50.046000 12.038000 50.114000 13.522000 ;
 RECT 50.262000 12.038000 50.330000 13.522000 ;
 RECT 49.614000 13.658000 49.682000 14.512000 ;
 RECT 49.830000 13.658000 49.898000 14.512000 ;
 RECT 50.046000 13.658000 50.114000 15.142000 ;
 RECT 50.262000 13.658000 50.330000 15.142000 ;
 RECT 49.614000 15.278000 49.682000 16.132000 ;
 RECT 49.830000 15.278000 49.898000 16.132000 ;
 RECT 50.046000 15.278000 50.114000 16.762000 ;
 RECT 50.262000 15.278000 50.330000 16.762000 ;
 RECT 49.614000 16.898000 49.682000 17.752000 ;
 RECT 49.830000 16.898000 49.898000 17.752000 ;
 RECT 50.046000 16.898000 50.114000 18.382000 ;
 RECT 50.262000 16.898000 50.330000 18.382000 ;
 RECT 49.614000 18.518000 49.682000 19.372000 ;
 RECT 49.830000 18.518000 49.898000 19.372000 ;
 RECT 50.046000 18.518000 50.114000 20.002000 ;
 RECT 50.262000 18.518000 50.330000 20.002000 ;
 RECT 49.614000 20.138000 49.682000 20.992000 ;
 RECT 49.830000 20.138000 49.898000 20.992000 ;
 RECT 50.046000 20.138000 50.114000 21.622000 ;
 RECT 50.262000 20.138000 50.330000 21.622000 ;
 RECT 49.614000 21.758000 49.682000 22.612000 ;
 RECT 49.830000 21.758000 49.898000 22.612000 ;
 RECT 50.046000 21.758000 50.114000 23.242000 ;
 RECT 50.262000 21.758000 50.330000 23.242000 ;
 RECT 32.874000 10.418000 32.942000 11.902000 ;
 RECT 33.090000 10.418000 33.158000 11.902000 ;
 RECT 33.306000 11.048000 33.374000 11.902000 ;
 RECT 33.522000 11.048000 33.590000 11.902000 ;
 RECT 49.614000 23.378000 49.682000 24.232000 ;
 RECT 49.830000 23.378000 49.898000 24.232000 ;
 RECT 50.046000 23.378000 50.114000 24.862000 ;
 RECT 50.262000 23.378000 50.330000 24.862000 ;
 RECT 49.614000 24.998000 49.682000 25.852000 ;
 RECT 49.830000 24.998000 49.898000 25.852000 ;
 RECT 50.046000 24.998000 50.114000 26.482000 ;
 RECT 50.262000 24.998000 50.330000 26.482000 ;
 RECT 49.614000 26.618000 49.682000 27.472000 ;
 RECT 49.830000 26.618000 49.898000 27.472000 ;
 RECT 50.046000 26.618000 50.114000 28.102000 ;
 RECT 50.262000 26.618000 50.330000 28.102000 ;
 RECT 49.614000 28.238000 49.682000 29.092000 ;
 RECT 49.830000 28.238000 49.898000 29.092000 ;
 RECT 50.046000 28.238000 50.114000 29.722000 ;
 RECT 50.262000 28.238000 50.330000 29.722000 ;
 RECT 49.614000 29.858000 49.682000 30.712000 ;
 RECT 49.830000 29.858000 49.898000 30.712000 ;
 RECT 50.046000 29.858000 50.114000 31.342000 ;
 RECT 50.262000 29.858000 50.330000 31.342000 ;
 RECT 49.614000 31.478000 49.682000 32.332000 ;
 RECT 49.830000 31.478000 49.898000 32.332000 ;
 RECT 50.046000 31.478000 50.114000 32.962000 ;
 RECT 50.262000 31.478000 50.330000 32.962000 ;
 RECT 49.614000 33.098000 49.682000 33.952000 ;
 RECT 49.830000 33.098000 49.898000 33.952000 ;
 RECT 50.046000 33.098000 50.114000 34.582000 ;
 RECT 50.262000 33.098000 50.330000 34.582000 ;
 RECT 49.614000 34.718000 49.682000 35.572000 ;
 RECT 49.830000 34.718000 49.898000 35.572000 ;
 RECT 50.046000 34.718000 50.114000 36.202000 ;
 RECT 50.262000 34.718000 50.330000 36.202000 ;
 RECT 49.614000 36.338000 49.682000 37.192000 ;
 RECT 49.830000 36.338000 49.898000 37.192000 ;
 RECT 50.046000 36.338000 50.114000 37.822000 ;
 RECT 50.262000 36.338000 50.330000 37.822000 ;
 RECT 49.614000 37.958000 49.682000 38.812000 ;
 RECT 49.830000 37.958000 49.898000 38.812000 ;
 RECT 50.046000 37.958000 50.114000 39.442000 ;
 RECT 50.262000 37.958000 50.330000 39.442000 ;
 RECT 32.874000 12.038000 32.942000 13.522000 ;
 RECT 33.090000 12.038000 33.158000 13.522000 ;
 RECT 33.306000 12.668000 33.374000 13.522000 ;
 RECT 33.522000 12.668000 33.590000 13.522000 ;
 RECT 49.614000 39.578000 49.682000 40.432000 ;
 RECT 49.830000 39.578000 49.898000 40.432000 ;
 RECT 50.046000 39.578000 50.114000 41.062000 ;
 RECT 50.262000 39.578000 50.330000 41.062000 ;
 RECT 49.614000 41.198000 49.682000 42.052000 ;
 RECT 49.830000 41.198000 49.898000 42.052000 ;
 RECT 50.046000 41.198000 50.114000 42.682000 ;
 RECT 50.262000 41.198000 50.330000 42.682000 ;
 RECT 49.614000 42.818000 49.682000 43.672000 ;
 RECT 49.830000 42.818000 49.898000 43.672000 ;
 RECT 50.046000 42.818000 50.114000 44.302000 ;
 RECT 50.262000 42.818000 50.330000 44.302000 ;
 RECT 49.614000 44.438000 49.682000 45.292000 ;
 RECT 49.830000 44.438000 49.898000 45.292000 ;
 RECT 50.046000 44.438000 50.114000 45.922000 ;
 RECT 50.262000 44.438000 50.330000 45.922000 ;
 RECT 49.614000 46.058000 49.682000 46.912000 ;
 RECT 49.830000 46.058000 49.898000 46.912000 ;
 RECT 50.046000 46.058000 50.114000 47.542000 ;
 RECT 50.262000 46.058000 50.330000 47.542000 ;
 RECT 49.614000 47.678000 49.682000 48.532000 ;
 RECT 49.830000 47.678000 49.898000 48.532000 ;
 RECT 50.046000 47.678000 50.114000 49.162000 ;
 RECT 50.262000 47.678000 50.330000 49.162000 ;
 RECT 49.614000 49.298000 49.682000 50.152000 ;
 RECT 49.830000 49.298000 49.898000 50.152000 ;
 RECT 50.046000 49.298000 50.114000 50.782000 ;
 RECT 50.262000 49.298000 50.330000 50.782000 ;
 RECT 49.614000 50.918000 49.682000 51.772000 ;
 RECT 49.830000 50.918000 49.898000 51.772000 ;
 RECT 50.046000 50.918000 50.114000 52.402000 ;
 RECT 50.262000 50.918000 50.330000 52.402000 ;
 RECT 49.614000 65.138000 49.682000 65.992000 ;
 RECT 49.830000 65.138000 49.898000 65.992000 ;
 RECT 50.046000 65.138000 50.114000 66.622000 ;
 RECT 50.262000 65.138000 50.330000 66.622000 ;
 RECT 49.614000 66.758000 49.682000 67.612000 ;
 RECT 49.830000 66.758000 49.898000 67.612000 ;
 RECT 50.046000 66.758000 50.114000 68.242000 ;
 RECT 50.262000 66.758000 50.330000 68.242000 ;
 LAYER m2 ;
 RECT 32.692000 13.748000 33.596000 13.792000 ;
 RECT 32.692000 15.008000 33.988000 15.052000 ;
 RECT 32.764000 14.018000 33.260500 14.062000 ;
 RECT 32.764000 14.558000 33.964000 14.602000 ;
 RECT 32.764000 14.738000 33.964000 14.782000 ;
 RECT 32.824000 14.378000 33.988000 14.422000 ;
 RECT 49.216000 68.468000 50.512000 68.512000 ;
 RECT 49.216000 69.098000 50.380000 69.142000 ;
 RECT 49.240000 68.738000 50.440000 68.782000 ;
 RECT 49.240000 68.918000 50.440000 68.962000 ;
 RECT 49.608000 69.728000 50.512000 69.772000 ;
 RECT 49.943500 69.458000 50.440000 69.502000 ;
 RECT 49.216000 70.088000 50.512000 70.132000 ;
 RECT 49.216000 70.718000 50.380000 70.762000 ;
 RECT 49.240000 70.358000 50.440000 70.402000 ;
 RECT 49.240000 70.538000 50.440000 70.582000 ;
 RECT 49.608000 71.348000 50.512000 71.392000 ;
 RECT 49.943500 71.078000 50.440000 71.122000 ;
 RECT 49.216000 71.708000 50.512000 71.752000 ;
 RECT 49.216000 72.338000 50.380000 72.382000 ;
 RECT 49.240000 71.978000 50.440000 72.022000 ;
 RECT 49.240000 72.158000 50.440000 72.202000 ;
 RECT 49.608000 72.968000 50.512000 73.012000 ;
 RECT 49.943500 72.698000 50.440000 72.742000 ;
 RECT 49.216000 73.328000 50.512000 73.372000 ;
 RECT 49.216000 73.958000 50.380000 74.002000 ;
 RECT 49.240000 73.598000 50.440000 73.642000 ;
 RECT 49.240000 73.778000 50.440000 73.822000 ;
 RECT 49.608000 74.588000 50.512000 74.632000 ;
 RECT 49.943500 74.318000 50.440000 74.362000 ;
 RECT 49.216000 74.948000 50.512000 74.992000 ;
 RECT 49.216000 75.578000 50.380000 75.622000 ;
 RECT 49.240000 75.218000 50.440000 75.262000 ;
 RECT 49.240000 75.398000 50.440000 75.442000 ;
 RECT 49.608000 76.208000 50.512000 76.252000 ;
 RECT 49.943500 75.938000 50.440000 75.982000 ;
 RECT 49.216000 76.568000 50.512000 76.612000 ;
 RECT 49.216000 77.198000 50.380000 77.242000 ;
 RECT 49.240000 76.838000 50.440000 76.882000 ;
 RECT 49.240000 77.018000 50.440000 77.062000 ;
 RECT 49.608000 77.828000 50.512000 77.872000 ;
 RECT 49.943500 77.558000 50.440000 77.602000 ;
 RECT 49.216000 78.188000 50.512000 78.232000 ;
 RECT 49.216000 78.818000 50.380000 78.862000 ;
 RECT 49.240000 78.458000 50.440000 78.502000 ;
 RECT 49.240000 78.638000 50.440000 78.682000 ;
 RECT 49.608000 79.448000 50.512000 79.492000 ;
 RECT 49.943500 79.178000 50.440000 79.222000 ;
 RECT 49.216000 79.808000 50.512000 79.852000 ;
 RECT 49.216000 80.438000 50.380000 80.482000 ;
 RECT 49.240000 80.078000 50.440000 80.122000 ;
 RECT 49.240000 80.258000 50.440000 80.302000 ;
 RECT 49.608000 81.068000 50.512000 81.112000 ;
 RECT 49.943500 80.798000 50.440000 80.842000 ;
 RECT 49.216000 81.428000 50.512000 81.472000 ;
 RECT 49.216000 82.058000 50.380000 82.102000 ;
 RECT 49.240000 81.698000 50.440000 81.742000 ;
 RECT 49.240000 81.878000 50.440000 81.922000 ;
 RECT 49.608000 82.688000 50.512000 82.732000 ;
 RECT 49.943500 82.418000 50.440000 82.462000 ;
 RECT 49.216000 83.048000 50.512000 83.092000 ;
 RECT 49.216000 83.678000 50.380000 83.722000 ;
 RECT 49.240000 83.318000 50.440000 83.362000 ;
 RECT 49.240000 83.498000 50.440000 83.542000 ;
 RECT 49.608000 84.308000 50.512000 84.352000 ;
 RECT 49.943500 84.038000 50.440000 84.082000 ;
 RECT 32.692000 15.368000 33.596000 15.412000 ;
 RECT 32.692000 16.628000 33.988000 16.672000 ;
 RECT 32.764000 15.638000 33.260500 15.682000 ;
 RECT 32.764000 16.178000 33.964000 16.222000 ;
 RECT 32.764000 16.358000 33.964000 16.402000 ;
 RECT 32.824000 15.998000 33.988000 16.042000 ;
 RECT 49.216000 84.668000 50.512000 84.712000 ;
 RECT 49.216000 85.298000 50.380000 85.342000 ;
 RECT 49.240000 84.938000 50.440000 84.982000 ;
 RECT 49.240000 85.118000 50.440000 85.162000 ;
 RECT 49.608000 85.928000 50.512000 85.972000 ;
 RECT 49.943500 85.658000 50.440000 85.702000 ;
 RECT 49.216000 86.288000 50.512000 86.332000 ;
 RECT 49.216000 86.918000 50.380000 86.962000 ;
 RECT 49.240000 86.558000 50.440000 86.602000 ;
 RECT 49.240000 86.738000 50.440000 86.782000 ;
 RECT 49.608000 87.548000 50.512000 87.592000 ;
 RECT 49.943500 87.278000 50.440000 87.322000 ;
 RECT 49.216000 87.908000 50.512000 87.952000 ;
 RECT 49.216000 88.538000 50.380000 88.582000 ;
 RECT 49.240000 88.178000 50.440000 88.222000 ;
 RECT 49.240000 88.358000 50.440000 88.402000 ;
 RECT 49.608000 89.168000 50.512000 89.212000 ;
 RECT 49.943500 88.898000 50.440000 88.942000 ;
 RECT 49.216000 89.528000 50.512000 89.572000 ;
 RECT 49.216000 90.158000 50.380000 90.202000 ;
 RECT 49.240000 89.798000 50.440000 89.842000 ;
 RECT 49.240000 89.978000 50.440000 90.022000 ;
 RECT 49.608000 90.788000 50.512000 90.832000 ;
 RECT 49.943500 90.518000 50.440000 90.562000 ;
 RECT 49.216000 91.148000 50.512000 91.192000 ;
 RECT 49.216000 91.778000 50.380000 91.822000 ;
 RECT 49.240000 91.418000 50.440000 91.462000 ;
 RECT 49.240000 91.598000 50.440000 91.642000 ;
 RECT 49.608000 92.408000 50.512000 92.452000 ;
 RECT 49.943500 92.138000 50.440000 92.182000 ;
 RECT 49.216000 92.768000 50.512000 92.812000 ;
 RECT 49.216000 93.398000 50.380000 93.442000 ;
 RECT 49.240000 93.038000 50.440000 93.082000 ;
 RECT 49.240000 93.218000 50.440000 93.262000 ;
 RECT 49.608000 94.028000 50.512000 94.072000 ;
 RECT 49.943500 93.758000 50.440000 93.802000 ;
 RECT 49.216000 94.388000 50.512000 94.432000 ;
 RECT 49.216000 95.018000 50.380000 95.062000 ;
 RECT 49.240000 94.658000 50.440000 94.702000 ;
 RECT 49.240000 94.838000 50.440000 94.882000 ;
 RECT 49.608000 95.648000 50.512000 95.692000 ;
 RECT 49.943500 95.378000 50.440000 95.422000 ;
 RECT 49.216000 96.008000 50.512000 96.052000 ;
 RECT 49.216000 96.638000 50.380000 96.682000 ;
 RECT 49.240000 96.278000 50.440000 96.322000 ;
 RECT 49.240000 96.458000 50.440000 96.502000 ;
 RECT 49.608000 97.268000 50.512000 97.312000 ;
 RECT 49.943500 96.998000 50.440000 97.042000 ;
 RECT 49.216000 97.628000 50.512000 97.672000 ;
 RECT 49.216000 98.258000 50.380000 98.302000 ;
 RECT 49.240000 97.898000 50.440000 97.942000 ;
 RECT 49.240000 98.078000 50.440000 98.122000 ;
 RECT 49.608000 98.888000 50.512000 98.932000 ;
 RECT 49.943500 98.618000 50.440000 98.662000 ;
 RECT 49.216000 99.248000 50.512000 99.292000 ;
 RECT 49.216000 99.878000 50.380000 99.922000 ;
 RECT 49.240000 99.518000 50.440000 99.562000 ;
 RECT 49.240000 99.698000 50.440000 99.742000 ;
 RECT 49.608000 100.508000 50.512000 100.552000 ;
 RECT 49.943500 100.238000 50.440000 100.282000 ;
 RECT 32.692000 16.988000 33.596000 17.032000 ;
 RECT 32.692000 18.248000 33.988000 18.292000 ;
 RECT 32.764000 17.258000 33.260500 17.302000 ;
 RECT 32.764000 17.798000 33.964000 17.842000 ;
 RECT 32.764000 17.978000 33.964000 18.022000 ;
 RECT 32.824000 17.618000 33.988000 17.662000 ;
 RECT 49.216000 100.868000 50.512000 100.912000 ;
 RECT 49.216000 101.498000 50.380000 101.542000 ;
 RECT 49.240000 101.138000 50.440000 101.182000 ;
 RECT 49.240000 101.318000 50.440000 101.362000 ;
 RECT 49.608000 102.128000 50.512000 102.172000 ;
 RECT 49.943500 101.858000 50.440000 101.902000 ;
 RECT 49.216000 102.488000 50.512000 102.532000 ;
 RECT 49.216000 103.118000 50.380000 103.162000 ;
 RECT 49.240000 102.758000 50.440000 102.802000 ;
 RECT 49.240000 102.938000 50.440000 102.982000 ;
 RECT 49.608000 103.748000 50.512000 103.792000 ;
 RECT 49.943500 103.478000 50.440000 103.522000 ;
 RECT 49.216000 104.108000 50.512000 104.152000 ;
 RECT 49.216000 104.738000 50.380000 104.782000 ;
 RECT 49.240000 104.378000 50.440000 104.422000 ;
 RECT 49.240000 104.558000 50.440000 104.602000 ;
 RECT 49.608000 105.368000 50.512000 105.412000 ;
 RECT 49.943500 105.098000 50.440000 105.142000 ;
 RECT 49.216000 105.728000 50.512000 105.772000 ;
 RECT 49.216000 106.358000 50.380000 106.402000 ;
 RECT 49.240000 105.998000 50.440000 106.042000 ;
 RECT 49.240000 106.178000 50.440000 106.222000 ;
 RECT 49.608000 106.988000 50.512000 107.032000 ;
 RECT 49.943500 106.718000 50.440000 106.762000 ;
 RECT 49.216000 107.348000 50.512000 107.392000 ;
 RECT 49.216000 107.978000 50.380000 108.022000 ;
 RECT 49.240000 107.618000 50.440000 107.662000 ;
 RECT 49.240000 107.798000 50.440000 107.842000 ;
 RECT 49.608000 108.608000 50.512000 108.652000 ;
 RECT 49.943500 108.338000 50.440000 108.382000 ;
 RECT 49.216000 108.968000 50.512000 109.012000 ;
 RECT 49.216000 109.598000 50.380000 109.642000 ;
 RECT 49.240000 109.238000 50.440000 109.282000 ;
 RECT 49.240000 109.418000 50.440000 109.462000 ;
 RECT 49.608000 110.228000 50.512000 110.272000 ;
 RECT 49.943500 109.958000 50.440000 110.002000 ;
 RECT 49.216000 110.588000 50.512000 110.632000 ;
 RECT 49.216000 111.218000 50.380000 111.262000 ;
 RECT 49.240000 110.858000 50.440000 110.902000 ;
 RECT 49.240000 111.038000 50.440000 111.082000 ;
 RECT 49.608000 111.848000 50.512000 111.892000 ;
 RECT 49.943500 111.578000 50.440000 111.622000 ;
 RECT 49.216000 112.208000 50.512000 112.252000 ;
 RECT 49.216000 112.838000 50.380000 112.882000 ;
 RECT 49.240000 112.478000 50.440000 112.522000 ;
 RECT 49.240000 112.658000 50.440000 112.702000 ;
 RECT 49.608000 113.468000 50.512000 113.512000 ;
 RECT 49.943500 113.198000 50.440000 113.242000 ;
 RECT 49.216000 113.828000 50.512000 113.872000 ;
 RECT 49.216000 114.458000 50.380000 114.502000 ;
 RECT 49.240000 114.098000 50.440000 114.142000 ;
 RECT 49.240000 114.278000 50.440000 114.322000 ;
 RECT 49.608000 115.088000 50.512000 115.132000 ;
 RECT 49.943500 114.818000 50.440000 114.862000 ;
 RECT 49.216000 115.448000 50.512000 115.492000 ;
 RECT 49.216000 116.078000 50.380000 116.122000 ;
 RECT 49.240000 115.718000 50.440000 115.762000 ;
 RECT 49.240000 115.898000 50.440000 115.942000 ;
 RECT 49.608000 116.708000 50.512000 116.752000 ;
 RECT 49.943500 116.438000 50.440000 116.482000 ;
 RECT 32.692000 18.608000 33.596000 18.652000 ;
 RECT 32.692000 19.868000 33.988000 19.912000 ;
 RECT 32.764000 18.878000 33.260500 18.922000 ;
 RECT 32.764000 19.418000 33.964000 19.462000 ;
 RECT 32.764000 19.598000 33.964000 19.642000 ;
 RECT 32.824000 19.238000 33.988000 19.282000 ;
 RECT 1.212000 57.261000 3.044000 57.369000 ;
 RECT 1.212000 58.911000 3.044000 59.019000 ;
 RECT 2.940000 57.261000 4.772000 57.369000 ;
 RECT 2.940000 58.911000 4.772000 59.019000 ;
 RECT 4.668000 57.261000 6.500000 57.369000 ;
 RECT 4.668000 58.911000 6.500000 59.019000 ;
 RECT 6.396000 57.261000 8.228000 57.369000 ;
 RECT 6.396000 58.911000 8.228000 59.019000 ;
 RECT 8.124000 57.261000 9.956000 57.369000 ;
 RECT 8.124000 58.911000 9.956000 59.019000 ;
 RECT 32.692000 20.228000 33.596000 20.272000 ;
 RECT 32.692000 21.488000 33.988000 21.532000 ;
 RECT 32.764000 20.498000 33.260500 20.542000 ;
 RECT 32.764000 21.038000 33.964000 21.082000 ;
 RECT 32.764000 21.218000 33.964000 21.262000 ;
 RECT 32.824000 20.858000 33.988000 20.902000 ;
 RECT 9.852000 57.261000 11.684000 57.369000 ;
 RECT 9.852000 58.911000 11.684000 59.019000 ;
 RECT 11.580000 57.261000 13.412000 57.369000 ;
 RECT 11.580000 58.911000 13.412000 59.019000 ;
 RECT 13.308000 57.261000 15.140000 57.369000 ;
 RECT 13.308000 58.911000 15.140000 59.019000 ;
 RECT 15.036000 57.261000 16.868000 57.369000 ;
 RECT 15.036000 58.911000 16.868000 59.019000 ;
 RECT 16.764000 57.261000 18.596000 57.369000 ;
 RECT 16.764000 58.911000 18.596000 59.019000 ;
 RECT 32.692000 21.848000 33.596000 21.892000 ;
 RECT 32.692000 23.108000 33.988000 23.152000 ;
 RECT 32.764000 22.118000 33.260500 22.162000 ;
 RECT 32.764000 22.658000 33.964000 22.702000 ;
 RECT 32.764000 22.838000 33.964000 22.882000 ;
 RECT 32.824000 22.478000 33.988000 22.522000 ;
 RECT 18.492000 57.261000 20.324000 57.369000 ;
 RECT 18.492000 58.911000 20.324000 59.019000 ;
 RECT 20.220000 57.261000 22.052000 57.369000 ;
 RECT 20.220000 58.911000 22.052000 59.019000 ;
 RECT 21.948000 57.261000 23.780000 57.369000 ;
 RECT 21.948000 58.911000 23.780000 59.019000 ;
 RECT 23.676000 57.261000 25.508000 57.369000 ;
 RECT 23.676000 58.911000 25.508000 59.019000 ;
 RECT 25.404000 57.261000 27.236000 57.369000 ;
 RECT 25.404000 58.911000 27.236000 59.019000 ;
 RECT 32.692000 23.468000 33.596000 23.512000 ;
 RECT 32.692000 24.728000 33.988000 24.772000 ;
 RECT 32.764000 23.738000 33.260500 23.782000 ;
 RECT 32.764000 24.278000 33.964000 24.322000 ;
 RECT 32.764000 24.458000 33.964000 24.502000 ;
 RECT 32.824000 24.098000 33.988000 24.142000 ;
 RECT 27.132000 57.261000 28.964000 57.369000 ;
 RECT 27.132000 58.911000 28.964000 59.019000 ;
 RECT 54.240000 57.261000 56.072000 57.369000 ;
 RECT 54.240000 58.911000 56.072000 59.019000 ;
 RECT 55.968000 57.261000 57.800000 57.369000 ;
 RECT 55.968000 58.911000 57.800000 59.019000 ;
 RECT 57.696000 57.261000 59.528000 57.369000 ;
 RECT 57.696000 58.911000 59.528000 59.019000 ;
 RECT 59.424000 57.261000 61.256000 57.369000 ;
 RECT 59.424000 58.911000 61.256000 59.019000 ;
 RECT 32.692000 25.088000 33.596000 25.132000 ;
 RECT 32.692000 26.348000 33.988000 26.392000 ;
 RECT 32.764000 25.358000 33.260500 25.402000 ;
 RECT 32.764000 25.898000 33.964000 25.942000 ;
 RECT 32.764000 26.078000 33.964000 26.122000 ;
 RECT 32.824000 25.718000 33.988000 25.762000 ;
 RECT 61.152000 57.261000 62.984000 57.369000 ;
 RECT 61.152000 58.911000 62.984000 59.019000 ;
 RECT 62.880000 57.261000 64.712000 57.369000 ;
 RECT 62.880000 58.911000 64.712000 59.019000 ;
 RECT 64.608000 57.261000 66.440000 57.369000 ;
 RECT 64.608000 58.911000 66.440000 59.019000 ;
 RECT 66.336000 57.261000 68.168000 57.369000 ;
 RECT 66.336000 58.911000 68.168000 59.019000 ;
 RECT 68.064000 57.261000 69.896000 57.369000 ;
 RECT 68.064000 58.911000 69.896000 59.019000 ;
 RECT 32.692000 26.708000 33.596000 26.752000 ;
 RECT 32.692000 27.968000 33.988000 28.012000 ;
 RECT 32.764000 26.978000 33.260500 27.022000 ;
 RECT 32.764000 27.518000 33.964000 27.562000 ;
 RECT 32.764000 27.698000 33.964000 27.742000 ;
 RECT 32.824000 27.338000 33.988000 27.382000 ;
 RECT 69.792000 57.261000 71.624000 57.369000 ;
 RECT 69.792000 58.911000 71.624000 59.019000 ;
 RECT 71.520000 57.261000 73.352000 57.369000 ;
 RECT 71.520000 58.911000 73.352000 59.019000 ;
 RECT 73.248000 57.261000 75.080000 57.369000 ;
 RECT 73.248000 58.911000 75.080000 59.019000 ;
 RECT 74.976000 57.261000 76.808000 57.369000 ;
 RECT 74.976000 58.911000 76.808000 59.019000 ;
 RECT 76.704000 57.261000 78.536000 57.369000 ;
 RECT 76.704000 58.911000 78.536000 59.019000 ;
 RECT 32.692000 28.328000 33.596000 28.372000 ;
 RECT 32.692000 29.588000 33.988000 29.632000 ;
 RECT 32.764000 28.598000 33.260500 28.642000 ;
 RECT 32.764000 29.138000 33.964000 29.182000 ;
 RECT 32.764000 29.318000 33.964000 29.362000 ;
 RECT 32.824000 28.958000 33.988000 29.002000 ;
 RECT 78.432000 57.261000 80.264000 57.369000 ;
 RECT 78.432000 58.911000 80.264000 59.019000 ;
 RECT 80.160000 57.261000 81.992000 57.369000 ;
 RECT 80.160000 58.911000 81.992000 59.019000 ;
 RECT 31.992000 54.698000 32.992000 54.742000 ;
 RECT 32.208000 54.338000 33.063000 54.382000 ;
 RECT 31.992000 55.958000 32.992000 56.002000 ;
 RECT 32.208000 55.598000 33.063000 55.642000 ;
 RECT 31.992000 57.218000 32.992000 57.262000 ;
 RECT 32.208000 56.858000 33.063000 56.902000 ;
 RECT 31.992000 58.478000 32.992000 58.522000 ;
 RECT 32.208000 58.118000 33.063000 58.162000 ;
 RECT 31.992000 59.738000 32.992000 59.782000 ;
 RECT 32.208000 59.378000 33.063000 59.422000 ;
 RECT 31.992000 60.998000 32.992000 61.042000 ;
 RECT 32.208000 60.638000 33.063000 60.682000 ;
 RECT 32.692000 0.788000 33.596000 0.832000 ;
 RECT 32.692000 2.048000 33.988000 2.092000 ;
 RECT 32.764000 1.058000 33.260500 1.102000 ;
 RECT 32.764000 1.598000 33.964000 1.642000 ;
 RECT 32.764000 1.778000 33.964000 1.822000 ;
 RECT 32.824000 1.418000 33.988000 1.462000 ;
 RECT 32.692000 29.948000 33.596000 29.992000 ;
 RECT 32.692000 31.208000 33.988000 31.252000 ;
 RECT 32.764000 30.218000 33.260500 30.262000 ;
 RECT 32.764000 30.758000 33.964000 30.802000 ;
 RECT 32.764000 30.938000 33.964000 30.982000 ;
 RECT 32.824000 30.578000 33.988000 30.622000 ;
 RECT 31.992000 62.258000 32.992000 62.302000 ;
 RECT 32.208000 61.898000 33.063000 61.942000 ;
 RECT 31.992000 63.518000 32.992000 63.562000 ;
 RECT 32.208000 63.158000 33.063000 63.202000 ;
 RECT 50.212000 53.978000 51.212000 54.022000 ;
 RECT 50.141000 54.338000 50.996000 54.382000 ;
 RECT 50.212000 55.238000 51.212000 55.282000 ;
 RECT 50.141000 55.598000 50.996000 55.642000 ;
 RECT 50.212000 56.498000 51.212000 56.542000 ;
 RECT 50.141000 56.858000 50.996000 56.902000 ;
 RECT 50.212000 57.758000 51.212000 57.802000 ;
 RECT 50.141000 58.118000 50.996000 58.162000 ;
 RECT 50.212000 59.018000 51.212000 59.062000 ;
 RECT 50.141000 59.378000 50.996000 59.422000 ;
 RECT 50.212000 60.278000 51.212000 60.322000 ;
 RECT 50.141000 60.638000 50.996000 60.682000 ;
 RECT 50.212000 61.538000 51.212000 61.582000 ;
 RECT 50.141000 61.898000 50.996000 61.942000 ;
 RECT 50.212000 62.798000 51.212000 62.842000 ;
 RECT 50.141000 63.158000 50.996000 63.202000 ;
 RECT 32.692000 31.568000 33.596000 31.612000 ;
 RECT 32.692000 32.828000 33.988000 32.872000 ;
 RECT 32.764000 31.838000 33.260500 31.882000 ;
 RECT 32.764000 32.378000 33.964000 32.422000 ;
 RECT 32.764000 32.558000 33.964000 32.602000 ;
 RECT 32.824000 32.198000 33.988000 32.242000 ;
 RECT 32.692000 33.188000 33.596000 33.232000 ;
 RECT 32.692000 34.448000 33.988000 34.492000 ;
 RECT 32.764000 33.458000 33.260500 33.502000 ;
 RECT 32.764000 33.998000 33.964000 34.042000 ;
 RECT 32.764000 34.178000 33.964000 34.222000 ;
 RECT 32.824000 33.818000 33.988000 33.862000 ;
 RECT 32.692000 34.808000 33.596000 34.852000 ;
 RECT 32.692000 36.068000 33.988000 36.112000 ;
 RECT 32.764000 35.078000 33.260500 35.122000 ;
 RECT 32.764000 35.618000 33.964000 35.662000 ;
 RECT 32.764000 35.798000 33.964000 35.842000 ;
 RECT 32.824000 35.438000 33.988000 35.482000 ;
 RECT 32.692000 36.428000 33.596000 36.472000 ;
 RECT 32.692000 37.688000 33.988000 37.732000 ;
 RECT 32.764000 36.698000 33.260500 36.742000 ;
 RECT 32.764000 37.238000 33.964000 37.282000 ;
 RECT 32.764000 37.418000 33.964000 37.462000 ;
 RECT 32.824000 37.058000 33.988000 37.102000 ;
 RECT 32.692000 38.048000 33.596000 38.092000 ;
 RECT 32.692000 39.308000 33.988000 39.352000 ;
 RECT 32.764000 38.318000 33.260500 38.362000 ;
 RECT 32.764000 38.858000 33.964000 38.902000 ;
 RECT 32.764000 39.038000 33.964000 39.082000 ;
 RECT 32.824000 38.678000 33.988000 38.722000 ;
 RECT 32.692000 39.668000 33.596000 39.712000 ;
 RECT 32.692000 40.928000 33.988000 40.972000 ;
 RECT 32.764000 39.938000 33.260500 39.982000 ;
 RECT 32.764000 40.478000 33.964000 40.522000 ;
 RECT 32.764000 40.658000 33.964000 40.702000 ;
 RECT 32.824000 40.298000 33.988000 40.342000 ;
 RECT 32.692000 41.288000 33.596000 41.332000 ;
 RECT 32.692000 42.548000 33.988000 42.592000 ;
 RECT 32.764000 41.558000 33.260500 41.602000 ;
 RECT 32.764000 42.098000 33.964000 42.142000 ;
 RECT 32.764000 42.278000 33.964000 42.322000 ;
 RECT 32.824000 41.918000 33.988000 41.962000 ;
 RECT 32.692000 42.908000 33.596000 42.952000 ;
 RECT 32.692000 44.168000 33.988000 44.212000 ;
 RECT 32.764000 43.178000 33.260500 43.222000 ;
 RECT 32.764000 43.718000 33.964000 43.762000 ;
 RECT 32.764000 43.898000 33.964000 43.942000 ;
 RECT 32.824000 43.538000 33.988000 43.582000 ;
 RECT 32.692000 44.528000 33.596000 44.572000 ;
 RECT 32.692000 45.788000 33.988000 45.832000 ;
 RECT 32.764000 44.798000 33.260500 44.842000 ;
 RECT 32.764000 45.338000 33.964000 45.382000 ;
 RECT 32.764000 45.518000 33.964000 45.562000 ;
 RECT 32.824000 45.158000 33.988000 45.202000 ;
 RECT 32.692000 2.408000 33.596000 2.452000 ;
 RECT 32.692000 3.668000 33.988000 3.712000 ;
 RECT 32.764000 2.678000 33.260500 2.722000 ;
 RECT 32.764000 3.218000 33.964000 3.262000 ;
 RECT 32.764000 3.398000 33.964000 3.442000 ;
 RECT 32.824000 3.038000 33.988000 3.082000 ;
 RECT 32.692000 46.148000 33.596000 46.192000 ;
 RECT 32.692000 47.408000 33.988000 47.452000 ;
 RECT 32.764000 46.418000 33.260500 46.462000 ;
 RECT 32.764000 46.958000 33.964000 47.002000 ;
 RECT 32.764000 47.138000 33.964000 47.182000 ;
 RECT 32.824000 46.778000 33.988000 46.822000 ;
 RECT 32.692000 47.768000 33.596000 47.812000 ;
 RECT 32.692000 49.028000 33.988000 49.072000 ;
 RECT 32.764000 48.038000 33.260500 48.082000 ;
 RECT 32.764000 48.578000 33.964000 48.622000 ;
 RECT 32.764000 48.758000 33.964000 48.802000 ;
 RECT 32.824000 48.398000 33.988000 48.442000 ;
 RECT 32.692000 49.388000 33.596000 49.432000 ;
 RECT 32.692000 50.648000 33.988000 50.692000 ;
 RECT 32.764000 49.658000 33.260500 49.702000 ;
 RECT 32.764000 50.198000 33.964000 50.242000 ;
 RECT 32.764000 50.378000 33.964000 50.422000 ;
 RECT 32.824000 50.018000 33.988000 50.062000 ;
 RECT 32.692000 51.008000 33.596000 51.052000 ;
 RECT 32.692000 52.268000 33.988000 52.312000 ;
 RECT 32.764000 51.278000 33.260500 51.322000 ;
 RECT 32.764000 51.818000 33.964000 51.862000 ;
 RECT 32.764000 51.998000 33.964000 52.042000 ;
 RECT 32.824000 51.638000 33.988000 51.682000 ;
 RECT 32.692000 65.228000 33.596000 65.272000 ;
 RECT 32.692000 66.488000 33.988000 66.532000 ;
 RECT 32.764000 65.498000 33.260500 65.542000 ;
 RECT 32.764000 66.038000 33.964000 66.082000 ;
 RECT 32.764000 66.218000 33.964000 66.262000 ;
 RECT 32.824000 65.858000 33.988000 65.902000 ;
 RECT 32.692000 66.848000 33.596000 66.892000 ;
 RECT 32.692000 68.108000 33.988000 68.152000 ;
 RECT 32.764000 67.118000 33.260500 67.162000 ;
 RECT 32.764000 67.658000 33.964000 67.702000 ;
 RECT 32.764000 67.838000 33.964000 67.882000 ;
 RECT 32.824000 67.478000 33.988000 67.522000 ;
 RECT 32.692000 68.468000 33.596000 68.512000 ;
 RECT 32.692000 69.728000 33.988000 69.772000 ;
 RECT 32.764000 68.738000 33.260500 68.782000 ;
 RECT 32.764000 69.278000 33.964000 69.322000 ;
 RECT 32.764000 69.458000 33.964000 69.502000 ;
 RECT 32.824000 69.098000 33.988000 69.142000 ;
 RECT 32.692000 70.088000 33.596000 70.132000 ;
 RECT 32.692000 71.348000 33.988000 71.392000 ;
 RECT 32.764000 70.358000 33.260500 70.402000 ;
 RECT 32.764000 70.898000 33.964000 70.942000 ;
 RECT 32.764000 71.078000 33.964000 71.122000 ;
 RECT 32.824000 70.718000 33.988000 70.762000 ;
 RECT 32.692000 71.708000 33.596000 71.752000 ;
 RECT 32.692000 72.968000 33.988000 73.012000 ;
 RECT 32.764000 71.978000 33.260500 72.022000 ;
 RECT 32.764000 72.518000 33.964000 72.562000 ;
 RECT 32.764000 72.698000 33.964000 72.742000 ;
 RECT 32.824000 72.338000 33.988000 72.382000 ;
 RECT 32.692000 73.328000 33.596000 73.372000 ;
 RECT 32.692000 74.588000 33.988000 74.632000 ;
 RECT 32.764000 73.598000 33.260500 73.642000 ;
 RECT 32.764000 74.138000 33.964000 74.182000 ;
 RECT 32.764000 74.318000 33.964000 74.362000 ;
 RECT 32.824000 73.958000 33.988000 74.002000 ;
 RECT 32.692000 4.028000 33.596000 4.072000 ;
 RECT 32.692000 5.288000 33.988000 5.332000 ;
 RECT 32.764000 4.298000 33.260500 4.342000 ;
 RECT 32.764000 4.838000 33.964000 4.882000 ;
 RECT 32.764000 5.018000 33.964000 5.062000 ;
 RECT 32.824000 4.658000 33.988000 4.702000 ;
 RECT 32.692000 74.948000 33.596000 74.992000 ;
 RECT 32.692000 76.208000 33.988000 76.252000 ;
 RECT 32.764000 75.218000 33.260500 75.262000 ;
 RECT 32.764000 75.758000 33.964000 75.802000 ;
 RECT 32.764000 75.938000 33.964000 75.982000 ;
 RECT 32.824000 75.578000 33.988000 75.622000 ;
 RECT 32.692000 76.568000 33.596000 76.612000 ;
 RECT 32.692000 77.828000 33.988000 77.872000 ;
 RECT 32.764000 76.838000 33.260500 76.882000 ;
 RECT 32.764000 77.378000 33.964000 77.422000 ;
 RECT 32.764000 77.558000 33.964000 77.602000 ;
 RECT 32.824000 77.198000 33.988000 77.242000 ;
 RECT 32.692000 78.188000 33.596000 78.232000 ;
 RECT 32.692000 79.448000 33.988000 79.492000 ;
 RECT 32.764000 78.458000 33.260500 78.502000 ;
 RECT 32.764000 78.998000 33.964000 79.042000 ;
 RECT 32.764000 79.178000 33.964000 79.222000 ;
 RECT 32.824000 78.818000 33.988000 78.862000 ;
 RECT 32.692000 79.808000 33.596000 79.852000 ;
 RECT 32.692000 81.068000 33.988000 81.112000 ;
 RECT 32.764000 80.078000 33.260500 80.122000 ;
 RECT 32.764000 80.618000 33.964000 80.662000 ;
 RECT 32.764000 80.798000 33.964000 80.842000 ;
 RECT 32.824000 80.438000 33.988000 80.482000 ;
 RECT 32.692000 81.428000 33.596000 81.472000 ;
 RECT 32.692000 82.688000 33.988000 82.732000 ;
 RECT 32.764000 81.698000 33.260500 81.742000 ;
 RECT 32.764000 82.238000 33.964000 82.282000 ;
 RECT 32.764000 82.418000 33.964000 82.462000 ;
 RECT 32.824000 82.058000 33.988000 82.102000 ;
 RECT 32.692000 83.048000 33.596000 83.092000 ;
 RECT 32.692000 84.308000 33.988000 84.352000 ;
 RECT 32.764000 83.318000 33.260500 83.362000 ;
 RECT 32.764000 83.858000 33.964000 83.902000 ;
 RECT 32.764000 84.038000 33.964000 84.082000 ;
 RECT 32.824000 83.678000 33.988000 83.722000 ;
 RECT 32.692000 84.668000 33.596000 84.712000 ;
 RECT 32.692000 85.928000 33.988000 85.972000 ;
 RECT 32.764000 84.938000 33.260500 84.982000 ;
 RECT 32.764000 85.478000 33.964000 85.522000 ;
 RECT 32.764000 85.658000 33.964000 85.702000 ;
 RECT 32.824000 85.298000 33.988000 85.342000 ;
 RECT 32.692000 86.288000 33.596000 86.332000 ;
 RECT 32.692000 87.548000 33.988000 87.592000 ;
 RECT 32.764000 86.558000 33.260500 86.602000 ;
 RECT 32.764000 87.098000 33.964000 87.142000 ;
 RECT 32.764000 87.278000 33.964000 87.322000 ;
 RECT 32.824000 86.918000 33.988000 86.962000 ;
 RECT 32.692000 87.908000 33.596000 87.952000 ;
 RECT 32.692000 89.168000 33.988000 89.212000 ;
 RECT 32.764000 88.178000 33.260500 88.222000 ;
 RECT 32.764000 88.718000 33.964000 88.762000 ;
 RECT 32.764000 88.898000 33.964000 88.942000 ;
 RECT 32.824000 88.538000 33.988000 88.582000 ;
 RECT 32.692000 89.528000 33.596000 89.572000 ;
 RECT 32.692000 90.788000 33.988000 90.832000 ;
 RECT 32.764000 89.798000 33.260500 89.842000 ;
 RECT 32.764000 90.338000 33.964000 90.382000 ;
 RECT 32.764000 90.518000 33.964000 90.562000 ;
 RECT 32.824000 90.158000 33.988000 90.202000 ;
 RECT 32.692000 5.648000 33.596000 5.692000 ;
 RECT 32.692000 6.908000 33.988000 6.952000 ;
 RECT 32.764000 5.918000 33.260500 5.962000 ;
 RECT 32.764000 6.458000 33.964000 6.502000 ;
 RECT 32.764000 6.638000 33.964000 6.682000 ;
 RECT 32.824000 6.278000 33.988000 6.322000 ;
 RECT 32.692000 91.148000 33.596000 91.192000 ;
 RECT 32.692000 92.408000 33.988000 92.452000 ;
 RECT 32.764000 91.418000 33.260500 91.462000 ;
 RECT 32.764000 91.958000 33.964000 92.002000 ;
 RECT 32.764000 92.138000 33.964000 92.182000 ;
 RECT 32.824000 91.778000 33.988000 91.822000 ;
 RECT 32.692000 92.768000 33.596000 92.812000 ;
 RECT 32.692000 94.028000 33.988000 94.072000 ;
 RECT 32.764000 93.038000 33.260500 93.082000 ;
 RECT 32.764000 93.578000 33.964000 93.622000 ;
 RECT 32.764000 93.758000 33.964000 93.802000 ;
 RECT 32.824000 93.398000 33.988000 93.442000 ;
 RECT 32.692000 94.388000 33.596000 94.432000 ;
 RECT 32.692000 95.648000 33.988000 95.692000 ;
 RECT 32.764000 94.658000 33.260500 94.702000 ;
 RECT 32.764000 95.198000 33.964000 95.242000 ;
 RECT 32.764000 95.378000 33.964000 95.422000 ;
 RECT 32.824000 95.018000 33.988000 95.062000 ;
 RECT 32.692000 96.008000 33.596000 96.052000 ;
 RECT 32.692000 97.268000 33.988000 97.312000 ;
 RECT 32.764000 96.278000 33.260500 96.322000 ;
 RECT 32.764000 96.818000 33.964000 96.862000 ;
 RECT 32.764000 96.998000 33.964000 97.042000 ;
 RECT 32.824000 96.638000 33.988000 96.682000 ;
 RECT 32.692000 97.628000 33.596000 97.672000 ;
 RECT 32.692000 98.888000 33.988000 98.932000 ;
 RECT 32.764000 97.898000 33.260500 97.942000 ;
 RECT 32.764000 98.438000 33.964000 98.482000 ;
 RECT 32.764000 98.618000 33.964000 98.662000 ;
 RECT 32.824000 98.258000 33.988000 98.302000 ;
 RECT 32.692000 99.248000 33.596000 99.292000 ;
 RECT 32.692000 100.508000 33.988000 100.552000 ;
 RECT 32.764000 99.518000 33.260500 99.562000 ;
 RECT 32.764000 100.058000 33.964000 100.102000 ;
 RECT 32.764000 100.238000 33.964000 100.282000 ;
 RECT 32.824000 99.878000 33.988000 99.922000 ;
 RECT 32.692000 100.868000 33.596000 100.912000 ;
 RECT 32.692000 102.128000 33.988000 102.172000 ;
 RECT 32.764000 101.138000 33.260500 101.182000 ;
 RECT 32.764000 101.678000 33.964000 101.722000 ;
 RECT 32.764000 101.858000 33.964000 101.902000 ;
 RECT 32.824000 101.498000 33.988000 101.542000 ;
 RECT 32.692000 102.488000 33.596000 102.532000 ;
 RECT 32.692000 103.748000 33.988000 103.792000 ;
 RECT 32.764000 102.758000 33.260500 102.802000 ;
 RECT 32.764000 103.298000 33.964000 103.342000 ;
 RECT 32.764000 103.478000 33.964000 103.522000 ;
 RECT 32.824000 103.118000 33.988000 103.162000 ;
 RECT 32.692000 104.108000 33.596000 104.152000 ;
 RECT 32.692000 105.368000 33.988000 105.412000 ;
 RECT 32.764000 104.378000 33.260500 104.422000 ;
 RECT 32.764000 104.918000 33.964000 104.962000 ;
 RECT 32.764000 105.098000 33.964000 105.142000 ;
 RECT 32.824000 104.738000 33.988000 104.782000 ;
 RECT 32.692000 105.728000 33.596000 105.772000 ;
 RECT 32.692000 106.988000 33.988000 107.032000 ;
 RECT 32.764000 105.998000 33.260500 106.042000 ;
 RECT 32.764000 106.538000 33.964000 106.582000 ;
 RECT 32.764000 106.718000 33.964000 106.762000 ;
 RECT 32.824000 106.358000 33.988000 106.402000 ;
 RECT 32.692000 7.268000 33.596000 7.312000 ;
 RECT 32.692000 8.528000 33.988000 8.572000 ;
 RECT 32.764000 7.538000 33.260500 7.582000 ;
 RECT 32.764000 8.078000 33.964000 8.122000 ;
 RECT 32.764000 8.258000 33.964000 8.302000 ;
 RECT 32.824000 7.898000 33.988000 7.942000 ;
 RECT 32.692000 107.348000 33.596000 107.392000 ;
 RECT 32.692000 108.608000 33.988000 108.652000 ;
 RECT 32.764000 107.618000 33.260500 107.662000 ;
 RECT 32.764000 108.158000 33.964000 108.202000 ;
 RECT 32.764000 108.338000 33.964000 108.382000 ;
 RECT 32.824000 107.978000 33.988000 108.022000 ;
 RECT 32.692000 108.968000 33.596000 109.012000 ;
 RECT 32.692000 110.228000 33.988000 110.272000 ;
 RECT 32.764000 109.238000 33.260500 109.282000 ;
 RECT 32.764000 109.778000 33.964000 109.822000 ;
 RECT 32.764000 109.958000 33.964000 110.002000 ;
 RECT 32.824000 109.598000 33.988000 109.642000 ;
 RECT 32.692000 110.588000 33.596000 110.632000 ;
 RECT 32.692000 111.848000 33.988000 111.892000 ;
 RECT 32.764000 110.858000 33.260500 110.902000 ;
 RECT 32.764000 111.398000 33.964000 111.442000 ;
 RECT 32.764000 111.578000 33.964000 111.622000 ;
 RECT 32.824000 111.218000 33.988000 111.262000 ;
 RECT 32.692000 112.208000 33.596000 112.252000 ;
 RECT 32.692000 113.468000 33.988000 113.512000 ;
 RECT 32.764000 112.478000 33.260500 112.522000 ;
 RECT 32.764000 113.018000 33.964000 113.062000 ;
 RECT 32.764000 113.198000 33.964000 113.242000 ;
 RECT 32.824000 112.838000 33.988000 112.882000 ;
 RECT 32.692000 113.828000 33.596000 113.872000 ;
 RECT 32.692000 115.088000 33.988000 115.132000 ;
 RECT 32.764000 114.098000 33.260500 114.142000 ;
 RECT 32.764000 114.638000 33.964000 114.682000 ;
 RECT 32.764000 114.818000 33.964000 114.862000 ;
 RECT 32.824000 114.458000 33.988000 114.502000 ;
 RECT 32.692000 115.448000 33.596000 115.492000 ;
 RECT 32.692000 116.708000 33.988000 116.752000 ;
 RECT 32.764000 115.718000 33.260500 115.762000 ;
 RECT 32.764000 116.258000 33.964000 116.302000 ;
 RECT 32.764000 116.438000 33.964000 116.482000 ;
 RECT 32.824000 116.078000 33.988000 116.122000 ;
 RECT 49.216000 0.788000 50.512000 0.832000 ;
 RECT 49.216000 1.418000 50.380000 1.462000 ;
 RECT 49.240000 1.058000 50.440000 1.102000 ;
 RECT 49.240000 1.238000 50.440000 1.282000 ;
 RECT 49.608000 2.048000 50.512000 2.092000 ;
 RECT 49.943500 1.778000 50.440000 1.822000 ;
 RECT 49.216000 2.408000 50.512000 2.452000 ;
 RECT 49.216000 3.038000 50.380000 3.082000 ;
 RECT 49.240000 2.678000 50.440000 2.722000 ;
 RECT 49.240000 2.858000 50.440000 2.902000 ;
 RECT 49.608000 3.668000 50.512000 3.712000 ;
 RECT 49.943500 3.398000 50.440000 3.442000 ;
 RECT 49.216000 4.028000 50.512000 4.072000 ;
 RECT 49.216000 4.658000 50.380000 4.702000 ;
 RECT 49.240000 4.298000 50.440000 4.342000 ;
 RECT 49.240000 4.478000 50.440000 4.522000 ;
 RECT 49.608000 5.288000 50.512000 5.332000 ;
 RECT 49.943500 5.018000 50.440000 5.062000 ;
 RECT 49.216000 5.648000 50.512000 5.692000 ;
 RECT 49.216000 6.278000 50.380000 6.322000 ;
 RECT 49.240000 5.918000 50.440000 5.962000 ;
 RECT 49.240000 6.098000 50.440000 6.142000 ;
 RECT 49.608000 6.908000 50.512000 6.952000 ;
 RECT 49.943500 6.638000 50.440000 6.682000 ;
 RECT 32.692000 8.888000 33.596000 8.932000 ;
 RECT 32.692000 10.148000 33.988000 10.192000 ;
 RECT 32.764000 9.158000 33.260500 9.202000 ;
 RECT 32.764000 9.698000 33.964000 9.742000 ;
 RECT 32.764000 9.878000 33.964000 9.922000 ;
 RECT 32.824000 9.518000 33.988000 9.562000 ;
 RECT 49.216000 7.268000 50.512000 7.312000 ;
 RECT 49.216000 7.898000 50.380000 7.942000 ;
 RECT 49.240000 7.538000 50.440000 7.582000 ;
 RECT 49.240000 7.718000 50.440000 7.762000 ;
 RECT 49.608000 8.528000 50.512000 8.572000 ;
 RECT 49.943500 8.258000 50.440000 8.302000 ;
 RECT 49.216000 8.888000 50.512000 8.932000 ;
 RECT 49.216000 9.518000 50.380000 9.562000 ;
 RECT 49.240000 9.158000 50.440000 9.202000 ;
 RECT 49.240000 9.338000 50.440000 9.382000 ;
 RECT 49.608000 10.148000 50.512000 10.192000 ;
 RECT 49.943500 9.878000 50.440000 9.922000 ;
 RECT 49.216000 10.508000 50.512000 10.552000 ;
 RECT 49.216000 11.138000 50.380000 11.182000 ;
 RECT 49.240000 10.778000 50.440000 10.822000 ;
 RECT 49.240000 10.958000 50.440000 11.002000 ;
 RECT 49.608000 11.768000 50.512000 11.812000 ;
 RECT 49.943500 11.498000 50.440000 11.542000 ;
 RECT 49.216000 12.128000 50.512000 12.172000 ;
 RECT 49.216000 12.758000 50.380000 12.802000 ;
 RECT 49.240000 12.398000 50.440000 12.442000 ;
 RECT 49.240000 12.578000 50.440000 12.622000 ;
 RECT 49.608000 13.388000 50.512000 13.432000 ;
 RECT 49.943500 13.118000 50.440000 13.162000 ;
 RECT 49.216000 13.748000 50.512000 13.792000 ;
 RECT 49.216000 14.378000 50.380000 14.422000 ;
 RECT 49.240000 14.018000 50.440000 14.062000 ;
 RECT 49.240000 14.198000 50.440000 14.242000 ;
 RECT 49.608000 15.008000 50.512000 15.052000 ;
 RECT 49.943500 14.738000 50.440000 14.782000 ;
 RECT 49.216000 15.368000 50.512000 15.412000 ;
 RECT 49.216000 15.998000 50.380000 16.042000 ;
 RECT 49.240000 15.638000 50.440000 15.682000 ;
 RECT 49.240000 15.818000 50.440000 15.862000 ;
 RECT 49.608000 16.628000 50.512000 16.672000 ;
 RECT 49.943500 16.358000 50.440000 16.402000 ;
 RECT 49.216000 16.988000 50.512000 17.032000 ;
 RECT 49.216000 17.618000 50.380000 17.662000 ;
 RECT 49.240000 17.258000 50.440000 17.302000 ;
 RECT 49.240000 17.438000 50.440000 17.482000 ;
 RECT 49.608000 18.248000 50.512000 18.292000 ;
 RECT 49.943500 17.978000 50.440000 18.022000 ;
 RECT 49.216000 18.608000 50.512000 18.652000 ;
 RECT 49.216000 19.238000 50.380000 19.282000 ;
 RECT 49.240000 18.878000 50.440000 18.922000 ;
 RECT 49.240000 19.058000 50.440000 19.102000 ;
 RECT 49.608000 19.868000 50.512000 19.912000 ;
 RECT 49.943500 19.598000 50.440000 19.642000 ;
 RECT 49.216000 20.228000 50.512000 20.272000 ;
 RECT 49.216000 20.858000 50.380000 20.902000 ;
 RECT 49.240000 20.498000 50.440000 20.542000 ;
 RECT 49.240000 20.678000 50.440000 20.722000 ;
 RECT 49.608000 21.488000 50.512000 21.532000 ;
 RECT 49.943500 21.218000 50.440000 21.262000 ;
 RECT 49.216000 21.848000 50.512000 21.892000 ;
 RECT 49.216000 22.478000 50.380000 22.522000 ;
 RECT 49.240000 22.118000 50.440000 22.162000 ;
 RECT 49.240000 22.298000 50.440000 22.342000 ;
 RECT 49.608000 23.108000 50.512000 23.152000 ;
 RECT 49.943500 22.838000 50.440000 22.882000 ;
 RECT 32.692000 10.508000 33.596000 10.552000 ;
 RECT 32.692000 11.768000 33.988000 11.812000 ;
 RECT 32.764000 10.778000 33.260500 10.822000 ;
 RECT 32.764000 11.318000 33.964000 11.362000 ;
 RECT 32.764000 11.498000 33.964000 11.542000 ;
 RECT 32.824000 11.138000 33.988000 11.182000 ;
 RECT 49.216000 23.468000 50.512000 23.512000 ;
 RECT 49.216000 24.098000 50.380000 24.142000 ;
 RECT 49.240000 23.738000 50.440000 23.782000 ;
 RECT 49.240000 23.918000 50.440000 23.962000 ;
 RECT 49.608000 24.728000 50.512000 24.772000 ;
 RECT 49.943500 24.458000 50.440000 24.502000 ;
 RECT 49.216000 25.088000 50.512000 25.132000 ;
 RECT 49.216000 25.718000 50.380000 25.762000 ;
 RECT 49.240000 25.358000 50.440000 25.402000 ;
 RECT 49.240000 25.538000 50.440000 25.582000 ;
 RECT 49.608000 26.348000 50.512000 26.392000 ;
 RECT 49.943500 26.078000 50.440000 26.122000 ;
 RECT 49.216000 26.708000 50.512000 26.752000 ;
 RECT 49.216000 27.338000 50.380000 27.382000 ;
 RECT 49.240000 26.978000 50.440000 27.022000 ;
 RECT 49.240000 27.158000 50.440000 27.202000 ;
 RECT 49.608000 27.968000 50.512000 28.012000 ;
 RECT 49.943500 27.698000 50.440000 27.742000 ;
 RECT 49.216000 28.328000 50.512000 28.372000 ;
 RECT 49.216000 28.958000 50.380000 29.002000 ;
 RECT 49.240000 28.598000 50.440000 28.642000 ;
 RECT 49.240000 28.778000 50.440000 28.822000 ;
 RECT 49.608000 29.588000 50.512000 29.632000 ;
 RECT 49.943500 29.318000 50.440000 29.362000 ;
 RECT 49.216000 29.948000 50.512000 29.992000 ;
 RECT 49.216000 30.578000 50.380000 30.622000 ;
 RECT 49.240000 30.218000 50.440000 30.262000 ;
 RECT 49.240000 30.398000 50.440000 30.442000 ;
 RECT 49.608000 31.208000 50.512000 31.252000 ;
 RECT 49.943500 30.938000 50.440000 30.982000 ;
 RECT 49.216000 31.568000 50.512000 31.612000 ;
 RECT 49.216000 32.198000 50.380000 32.242000 ;
 RECT 49.240000 31.838000 50.440000 31.882000 ;
 RECT 49.240000 32.018000 50.440000 32.062000 ;
 RECT 49.608000 32.828000 50.512000 32.872000 ;
 RECT 49.943500 32.558000 50.440000 32.602000 ;
 RECT 49.216000 33.188000 50.512000 33.232000 ;
 RECT 49.216000 33.818000 50.380000 33.862000 ;
 RECT 49.240000 33.458000 50.440000 33.502000 ;
 RECT 49.240000 33.638000 50.440000 33.682000 ;
 RECT 49.608000 34.448000 50.512000 34.492000 ;
 RECT 49.943500 34.178000 50.440000 34.222000 ;
 RECT 49.216000 34.808000 50.512000 34.852000 ;
 RECT 49.216000 35.438000 50.380000 35.482000 ;
 RECT 49.240000 35.078000 50.440000 35.122000 ;
 RECT 49.240000 35.258000 50.440000 35.302000 ;
 RECT 49.608000 36.068000 50.512000 36.112000 ;
 RECT 49.943500 35.798000 50.440000 35.842000 ;
 RECT 49.216000 36.428000 50.512000 36.472000 ;
 RECT 49.216000 37.058000 50.380000 37.102000 ;
 RECT 49.240000 36.698000 50.440000 36.742000 ;
 RECT 49.240000 36.878000 50.440000 36.922000 ;
 RECT 49.608000 37.688000 50.512000 37.732000 ;
 RECT 49.943500 37.418000 50.440000 37.462000 ;
 RECT 49.216000 38.048000 50.512000 38.092000 ;
 RECT 49.216000 38.678000 50.380000 38.722000 ;
 RECT 49.240000 38.318000 50.440000 38.362000 ;
 RECT 49.240000 38.498000 50.440000 38.542000 ;
 RECT 49.608000 39.308000 50.512000 39.352000 ;
 RECT 49.943500 39.038000 50.440000 39.082000 ;
 RECT 32.692000 12.128000 33.596000 12.172000 ;
 RECT 32.692000 13.388000 33.988000 13.432000 ;
 RECT 32.764000 12.398000 33.260500 12.442000 ;
 RECT 32.764000 12.938000 33.964000 12.982000 ;
 RECT 32.764000 13.118000 33.964000 13.162000 ;
 RECT 32.824000 12.758000 33.988000 12.802000 ;
 RECT 49.216000 39.668000 50.512000 39.712000 ;
 RECT 49.216000 40.298000 50.380000 40.342000 ;
 RECT 49.240000 39.938000 50.440000 39.982000 ;
 RECT 49.240000 40.118000 50.440000 40.162000 ;
 RECT 49.608000 40.928000 50.512000 40.972000 ;
 RECT 49.943500 40.658000 50.440000 40.702000 ;
 RECT 49.216000 41.288000 50.512000 41.332000 ;
 RECT 49.216000 41.918000 50.380000 41.962000 ;
 RECT 49.240000 41.558000 50.440000 41.602000 ;
 RECT 49.240000 41.738000 50.440000 41.782000 ;
 RECT 49.608000 42.548000 50.512000 42.592000 ;
 RECT 49.943500 42.278000 50.440000 42.322000 ;
 RECT 49.216000 42.908000 50.512000 42.952000 ;
 RECT 49.216000 43.538000 50.380000 43.582000 ;
 RECT 49.240000 43.178000 50.440000 43.222000 ;
 RECT 49.240000 43.358000 50.440000 43.402000 ;
 RECT 49.608000 44.168000 50.512000 44.212000 ;
 RECT 49.943500 43.898000 50.440000 43.942000 ;
 RECT 49.216000 44.528000 50.512000 44.572000 ;
 RECT 49.216000 45.158000 50.380000 45.202000 ;
 RECT 49.240000 44.798000 50.440000 44.842000 ;
 RECT 49.240000 44.978000 50.440000 45.022000 ;
 RECT 49.608000 45.788000 50.512000 45.832000 ;
 RECT 49.943500 45.518000 50.440000 45.562000 ;
 RECT 49.216000 46.148000 50.512000 46.192000 ;
 RECT 49.216000 46.778000 50.380000 46.822000 ;
 RECT 49.240000 46.418000 50.440000 46.462000 ;
 RECT 49.240000 46.598000 50.440000 46.642000 ;
 RECT 49.608000 47.408000 50.512000 47.452000 ;
 RECT 49.943500 47.138000 50.440000 47.182000 ;
 RECT 49.216000 47.768000 50.512000 47.812000 ;
 RECT 49.216000 48.398000 50.380000 48.442000 ;
 RECT 49.240000 48.038000 50.440000 48.082000 ;
 RECT 49.240000 48.218000 50.440000 48.262000 ;
 RECT 49.608000 49.028000 50.512000 49.072000 ;
 RECT 49.943500 48.758000 50.440000 48.802000 ;
 RECT 49.216000 49.388000 50.512000 49.432000 ;
 RECT 49.216000 50.018000 50.380000 50.062000 ;
 RECT 49.240000 49.658000 50.440000 49.702000 ;
 RECT 49.240000 49.838000 50.440000 49.882000 ;
 RECT 49.608000 50.648000 50.512000 50.692000 ;
 RECT 49.943500 50.378000 50.440000 50.422000 ;
 RECT 49.216000 51.008000 50.512000 51.052000 ;
 RECT 49.216000 51.638000 50.380000 51.682000 ;
 RECT 49.240000 51.278000 50.440000 51.322000 ;
 RECT 49.240000 51.458000 50.440000 51.502000 ;
 RECT 49.608000 52.268000 50.512000 52.312000 ;
 RECT 49.943500 51.998000 50.440000 52.042000 ;
 RECT 49.216000 65.228000 50.512000 65.272000 ;
 RECT 49.216000 65.858000 50.380000 65.902000 ;
 RECT 49.240000 65.498000 50.440000 65.542000 ;
 RECT 49.240000 65.678000 50.440000 65.722000 ;
 RECT 49.608000 66.488000 50.512000 66.532000 ;
 RECT 49.943500 66.218000 50.440000 66.262000 ;
 RECT 49.216000 66.848000 50.512000 66.892000 ;
 RECT 49.216000 67.478000 50.380000 67.522000 ;
 RECT 49.240000 67.118000 50.440000 67.162000 ;
 RECT 49.240000 67.298000 50.440000 67.342000 ;
 RECT 49.608000 68.108000 50.512000 68.152000 ;
 RECT 49.943500 67.838000 50.440000 67.882000 ;
 LAYER m3 ;
 RECT 32.776000 13.590000 32.852000 15.210000 ;
 RECT 33.020000 13.590000 33.096000 15.210000 ;
 RECT 33.264000 13.590000 33.340000 15.210000 ;
 RECT 33.508000 13.590000 33.584000 15.210000 ;
 RECT 49.620000 68.310000 49.696000 69.930000 ;
 RECT 49.864000 68.310000 49.940000 69.930000 ;
 RECT 50.108000 68.310000 50.184000 69.930000 ;
 RECT 50.352000 68.310000 50.428000 69.930000 ;
 RECT 49.620000 69.930000 49.696000 71.550000 ;
 RECT 49.864000 69.930000 49.940000 71.550000 ;
 RECT 50.108000 69.930000 50.184000 71.550000 ;
 RECT 50.352000 69.930000 50.428000 71.550000 ;
 RECT 49.620000 71.550000 49.696000 73.170000 ;
 RECT 49.864000 71.550000 49.940000 73.170000 ;
 RECT 50.108000 71.550000 50.184000 73.170000 ;
 RECT 50.352000 71.550000 50.428000 73.170000 ;
 RECT 49.620000 73.170000 49.696000 74.790000 ;
 RECT 49.864000 73.170000 49.940000 74.790000 ;
 RECT 50.108000 73.170000 50.184000 74.790000 ;
 RECT 50.352000 73.170000 50.428000 74.790000 ;
 RECT 49.620000 74.790000 49.696000 76.410000 ;
 RECT 49.864000 74.790000 49.940000 76.410000 ;
 RECT 50.108000 74.790000 50.184000 76.410000 ;
 RECT 50.352000 74.790000 50.428000 76.410000 ;
 RECT 49.620000 76.410000 49.696000 78.030000 ;
 RECT 49.864000 76.410000 49.940000 78.030000 ;
 RECT 50.108000 76.410000 50.184000 78.030000 ;
 RECT 50.352000 76.410000 50.428000 78.030000 ;
 RECT 49.620000 78.030000 49.696000 79.650000 ;
 RECT 49.864000 78.030000 49.940000 79.650000 ;
 RECT 50.108000 78.030000 50.184000 79.650000 ;
 RECT 50.352000 78.030000 50.428000 79.650000 ;
 RECT 49.620000 79.650000 49.696000 81.270000 ;
 RECT 49.864000 79.650000 49.940000 81.270000 ;
 RECT 50.108000 79.650000 50.184000 81.270000 ;
 RECT 50.352000 79.650000 50.428000 81.270000 ;
 RECT 49.620000 81.270000 49.696000 82.890000 ;
 RECT 49.864000 81.270000 49.940000 82.890000 ;
 RECT 50.108000 81.270000 50.184000 82.890000 ;
 RECT 50.352000 81.270000 50.428000 82.890000 ;
 RECT 49.620000 82.890000 49.696000 84.510000 ;
 RECT 49.864000 82.890000 49.940000 84.510000 ;
 RECT 50.108000 82.890000 50.184000 84.510000 ;
 RECT 50.352000 82.890000 50.428000 84.510000 ;
 RECT 32.776000 15.210000 32.852000 16.830000 ;
 RECT 33.020000 15.210000 33.096000 16.830000 ;
 RECT 33.264000 15.210000 33.340000 16.830000 ;
 RECT 33.508000 15.210000 33.584000 16.830000 ;
 RECT 49.620000 84.510000 49.696000 86.130000 ;
 RECT 49.864000 84.510000 49.940000 86.130000 ;
 RECT 50.108000 84.510000 50.184000 86.130000 ;
 RECT 50.352000 84.510000 50.428000 86.130000 ;
 RECT 49.620000 86.130000 49.696000 87.750000 ;
 RECT 49.864000 86.130000 49.940000 87.750000 ;
 RECT 50.108000 86.130000 50.184000 87.750000 ;
 RECT 50.352000 86.130000 50.428000 87.750000 ;
 RECT 49.620000 87.750000 49.696000 89.370000 ;
 RECT 49.864000 87.750000 49.940000 89.370000 ;
 RECT 50.108000 87.750000 50.184000 89.370000 ;
 RECT 50.352000 87.750000 50.428000 89.370000 ;
 RECT 49.620000 89.370000 49.696000 90.990000 ;
 RECT 49.864000 89.370000 49.940000 90.990000 ;
 RECT 50.108000 89.370000 50.184000 90.990000 ;
 RECT 50.352000 89.370000 50.428000 90.990000 ;
 RECT 49.620000 90.990000 49.696000 92.610000 ;
 RECT 49.864000 90.990000 49.940000 92.610000 ;
 RECT 50.108000 90.990000 50.184000 92.610000 ;
 RECT 50.352000 90.990000 50.428000 92.610000 ;
 RECT 49.620000 92.610000 49.696000 94.230000 ;
 RECT 49.864000 92.610000 49.940000 94.230000 ;
 RECT 50.108000 92.610000 50.184000 94.230000 ;
 RECT 50.352000 92.610000 50.428000 94.230000 ;
 RECT 49.620000 94.230000 49.696000 95.850000 ;
 RECT 49.864000 94.230000 49.940000 95.850000 ;
 RECT 50.108000 94.230000 50.184000 95.850000 ;
 RECT 50.352000 94.230000 50.428000 95.850000 ;
 RECT 49.620000 95.850000 49.696000 97.470000 ;
 RECT 49.864000 95.850000 49.940000 97.470000 ;
 RECT 50.108000 95.850000 50.184000 97.470000 ;
 RECT 50.352000 95.850000 50.428000 97.470000 ;
 RECT 49.620000 97.470000 49.696000 99.090000 ;
 RECT 49.864000 97.470000 49.940000 99.090000 ;
 RECT 50.108000 97.470000 50.184000 99.090000 ;
 RECT 50.352000 97.470000 50.428000 99.090000 ;
 RECT 49.620000 99.090000 49.696000 100.710000 ;
 RECT 49.864000 99.090000 49.940000 100.710000 ;
 RECT 50.108000 99.090000 50.184000 100.710000 ;
 RECT 50.352000 99.090000 50.428000 100.710000 ;
 RECT 32.776000 16.830000 32.852000 18.450000 ;
 RECT 33.020000 16.830000 33.096000 18.450000 ;
 RECT 33.264000 16.830000 33.340000 18.450000 ;
 RECT 33.508000 16.830000 33.584000 18.450000 ;
 RECT 49.620000 100.710000 49.696000 102.330000 ;
 RECT 49.864000 100.710000 49.940000 102.330000 ;
 RECT 50.108000 100.710000 50.184000 102.330000 ;
 RECT 50.352000 100.710000 50.428000 102.330000 ;
 RECT 49.620000 102.330000 49.696000 103.950000 ;
 RECT 49.864000 102.330000 49.940000 103.950000 ;
 RECT 50.108000 102.330000 50.184000 103.950000 ;
 RECT 50.352000 102.330000 50.428000 103.950000 ;
 RECT 49.620000 103.950000 49.696000 105.570000 ;
 RECT 49.864000 103.950000 49.940000 105.570000 ;
 RECT 50.108000 103.950000 50.184000 105.570000 ;
 RECT 50.352000 103.950000 50.428000 105.570000 ;
 RECT 49.620000 105.570000 49.696000 107.190000 ;
 RECT 49.864000 105.570000 49.940000 107.190000 ;
 RECT 50.108000 105.570000 50.184000 107.190000 ;
 RECT 50.352000 105.570000 50.428000 107.190000 ;
 RECT 49.620000 107.190000 49.696000 108.810000 ;
 RECT 49.864000 107.190000 49.940000 108.810000 ;
 RECT 50.108000 107.190000 50.184000 108.810000 ;
 RECT 50.352000 107.190000 50.428000 108.810000 ;
 RECT 49.620000 108.810000 49.696000 110.430000 ;
 RECT 49.864000 108.810000 49.940000 110.430000 ;
 RECT 50.108000 108.810000 50.184000 110.430000 ;
 RECT 50.352000 108.810000 50.428000 110.430000 ;
 RECT 49.620000 110.430000 49.696000 112.050000 ;
 RECT 49.864000 110.430000 49.940000 112.050000 ;
 RECT 50.108000 110.430000 50.184000 112.050000 ;
 RECT 50.352000 110.430000 50.428000 112.050000 ;
 RECT 49.620000 112.050000 49.696000 113.670000 ;
 RECT 49.864000 112.050000 49.940000 113.670000 ;
 RECT 50.108000 112.050000 50.184000 113.670000 ;
 RECT 50.352000 112.050000 50.428000 113.670000 ;
 RECT 49.620000 113.670000 49.696000 115.290000 ;
 RECT 49.864000 113.670000 49.940000 115.290000 ;
 RECT 50.108000 113.670000 50.184000 115.290000 ;
 RECT 50.352000 113.670000 50.428000 115.290000 ;
 RECT 49.620000 115.290000 49.696000 116.910000 ;
 RECT 49.864000 115.290000 49.940000 116.910000 ;
 RECT 50.108000 115.290000 50.184000 116.910000 ;
 RECT 50.352000 115.290000 50.428000 116.910000 ;
 RECT 32.776000 18.450000 32.852000 20.070000 ;
 RECT 33.020000 18.450000 33.096000 20.070000 ;
 RECT 33.264000 18.450000 33.340000 20.070000 ;
 RECT 33.508000 18.450000 33.584000 20.070000 ;
 RECT 32.776000 20.070000 32.852000 21.690000 ;
 RECT 33.020000 20.070000 33.096000 21.690000 ;
 RECT 33.264000 20.070000 33.340000 21.690000 ;
 RECT 33.508000 20.070000 33.584000 21.690000 ;
 RECT 32.776000 21.690000 32.852000 23.310000 ;
 RECT 33.020000 21.690000 33.096000 23.310000 ;
 RECT 33.264000 21.690000 33.340000 23.310000 ;
 RECT 33.508000 21.690000 33.584000 23.310000 ;
 RECT 32.776000 23.310000 32.852000 24.930000 ;
 RECT 33.020000 23.310000 33.096000 24.930000 ;
 RECT 33.264000 23.310000 33.340000 24.930000 ;
 RECT 33.508000 23.310000 33.584000 24.930000 ;
 RECT 32.776000 24.930000 32.852000 26.550000 ;
 RECT 33.020000 24.930000 33.096000 26.550000 ;
 RECT 33.264000 24.930000 33.340000 26.550000 ;
 RECT 33.508000 24.930000 33.584000 26.550000 ;
 RECT 32.776000 26.550000 32.852000 28.170000 ;
 RECT 33.020000 26.550000 33.096000 28.170000 ;
 RECT 33.264000 26.550000 33.340000 28.170000 ;
 RECT 33.508000 26.550000 33.584000 28.170000 ;
 RECT 32.776000 28.170000 32.852000 29.790000 ;
 RECT 33.020000 28.170000 33.096000 29.790000 ;
 RECT 33.264000 28.170000 33.340000 29.790000 ;
 RECT 33.508000 28.170000 33.584000 29.790000 ;
 RECT 32.776000 0.630000 32.852000 2.250000 ;
 RECT 33.020000 0.630000 33.096000 2.250000 ;
 RECT 33.264000 0.630000 33.340000 2.250000 ;
 RECT 33.508000 0.630000 33.584000 2.250000 ;
 RECT 32.776000 29.790000 32.852000 31.410000 ;
 RECT 33.020000 29.790000 33.096000 31.410000 ;
 RECT 33.264000 29.790000 33.340000 31.410000 ;
 RECT 33.508000 29.790000 33.584000 31.410000 ;
 RECT 32.776000 31.410000 32.852000 33.030000 ;
 RECT 33.020000 31.410000 33.096000 33.030000 ;
 RECT 33.264000 31.410000 33.340000 33.030000 ;
 RECT 33.508000 31.410000 33.584000 33.030000 ;
 RECT 32.776000 33.030000 32.852000 34.650000 ;
 RECT 33.020000 33.030000 33.096000 34.650000 ;
 RECT 33.264000 33.030000 33.340000 34.650000 ;
 RECT 33.508000 33.030000 33.584000 34.650000 ;
 RECT 32.776000 34.650000 32.852000 36.270000 ;
 RECT 33.020000 34.650000 33.096000 36.270000 ;
 RECT 33.264000 34.650000 33.340000 36.270000 ;
 RECT 33.508000 34.650000 33.584000 36.270000 ;
 RECT 32.776000 36.270000 32.852000 37.890000 ;
 RECT 33.020000 36.270000 33.096000 37.890000 ;
 RECT 33.264000 36.270000 33.340000 37.890000 ;
 RECT 33.508000 36.270000 33.584000 37.890000 ;
 RECT 32.776000 37.890000 32.852000 39.510000 ;
 RECT 33.020000 37.890000 33.096000 39.510000 ;
 RECT 33.264000 37.890000 33.340000 39.510000 ;
 RECT 33.508000 37.890000 33.584000 39.510000 ;
 RECT 32.776000 39.510000 32.852000 41.130000 ;
 RECT 33.020000 39.510000 33.096000 41.130000 ;
 RECT 33.264000 39.510000 33.340000 41.130000 ;
 RECT 33.508000 39.510000 33.584000 41.130000 ;
 RECT 32.776000 41.130000 32.852000 42.750000 ;
 RECT 33.020000 41.130000 33.096000 42.750000 ;
 RECT 33.264000 41.130000 33.340000 42.750000 ;
 RECT 33.508000 41.130000 33.584000 42.750000 ;
 RECT 32.776000 42.750000 32.852000 44.370000 ;
 RECT 33.020000 42.750000 33.096000 44.370000 ;
 RECT 33.264000 42.750000 33.340000 44.370000 ;
 RECT 33.508000 42.750000 33.584000 44.370000 ;
 RECT 32.776000 44.370000 32.852000 45.990000 ;
 RECT 33.020000 44.370000 33.096000 45.990000 ;
 RECT 33.264000 44.370000 33.340000 45.990000 ;
 RECT 33.508000 44.370000 33.584000 45.990000 ;
 RECT 32.776000 2.250000 32.852000 3.870000 ;
 RECT 33.020000 2.250000 33.096000 3.870000 ;
 RECT 33.264000 2.250000 33.340000 3.870000 ;
 RECT 33.508000 2.250000 33.584000 3.870000 ;
 RECT 32.776000 45.990000 32.852000 47.610000 ;
 RECT 33.020000 45.990000 33.096000 47.610000 ;
 RECT 33.264000 45.990000 33.340000 47.610000 ;
 RECT 33.508000 45.990000 33.584000 47.610000 ;
 RECT 32.776000 47.610000 32.852000 49.230000 ;
 RECT 33.020000 47.610000 33.096000 49.230000 ;
 RECT 33.264000 47.610000 33.340000 49.230000 ;
 RECT 33.508000 47.610000 33.584000 49.230000 ;
 RECT 32.776000 49.230000 32.852000 50.850000 ;
 RECT 33.020000 49.230000 33.096000 50.850000 ;
 RECT 33.264000 49.230000 33.340000 50.850000 ;
 RECT 33.508000 49.230000 33.584000 50.850000 ;
 RECT 32.776000 50.850000 32.852000 52.470000 ;
 RECT 33.020000 50.850000 33.096000 52.470000 ;
 RECT 33.264000 50.850000 33.340000 52.470000 ;
 RECT 33.508000 50.850000 33.584000 52.470000 ;
 RECT 32.776000 65.070000 32.852000 66.690000 ;
 RECT 33.020000 65.070000 33.096000 66.690000 ;
 RECT 33.264000 65.070000 33.340000 66.690000 ;
 RECT 33.508000 65.070000 33.584000 66.690000 ;
 RECT 32.776000 66.690000 32.852000 68.310000 ;
 RECT 33.020000 66.690000 33.096000 68.310000 ;
 RECT 33.264000 66.690000 33.340000 68.310000 ;
 RECT 33.508000 66.690000 33.584000 68.310000 ;
 RECT 32.776000 68.310000 32.852000 69.930000 ;
 RECT 33.020000 68.310000 33.096000 69.930000 ;
 RECT 33.264000 68.310000 33.340000 69.930000 ;
 RECT 33.508000 68.310000 33.584000 69.930000 ;
 RECT 32.776000 69.930000 32.852000 71.550000 ;
 RECT 33.020000 69.930000 33.096000 71.550000 ;
 RECT 33.264000 69.930000 33.340000 71.550000 ;
 RECT 33.508000 69.930000 33.584000 71.550000 ;
 RECT 32.776000 71.550000 32.852000 73.170000 ;
 RECT 33.020000 71.550000 33.096000 73.170000 ;
 RECT 33.264000 71.550000 33.340000 73.170000 ;
 RECT 33.508000 71.550000 33.584000 73.170000 ;
 RECT 32.776000 73.170000 32.852000 74.790000 ;
 RECT 33.020000 73.170000 33.096000 74.790000 ;
 RECT 33.264000 73.170000 33.340000 74.790000 ;
 RECT 33.508000 73.170000 33.584000 74.790000 ;
 RECT 32.776000 3.870000 32.852000 5.490000 ;
 RECT 33.020000 3.870000 33.096000 5.490000 ;
 RECT 33.264000 3.870000 33.340000 5.490000 ;
 RECT 33.508000 3.870000 33.584000 5.490000 ;
 RECT 32.776000 74.790000 32.852000 76.410000 ;
 RECT 33.020000 74.790000 33.096000 76.410000 ;
 RECT 33.264000 74.790000 33.340000 76.410000 ;
 RECT 33.508000 74.790000 33.584000 76.410000 ;
 RECT 32.776000 76.410000 32.852000 78.030000 ;
 RECT 33.020000 76.410000 33.096000 78.030000 ;
 RECT 33.264000 76.410000 33.340000 78.030000 ;
 RECT 33.508000 76.410000 33.584000 78.030000 ;
 RECT 32.776000 78.030000 32.852000 79.650000 ;
 RECT 33.020000 78.030000 33.096000 79.650000 ;
 RECT 33.264000 78.030000 33.340000 79.650000 ;
 RECT 33.508000 78.030000 33.584000 79.650000 ;
 RECT 32.776000 79.650000 32.852000 81.270000 ;
 RECT 33.020000 79.650000 33.096000 81.270000 ;
 RECT 33.264000 79.650000 33.340000 81.270000 ;
 RECT 33.508000 79.650000 33.584000 81.270000 ;
 RECT 32.776000 81.270000 32.852000 82.890000 ;
 RECT 33.020000 81.270000 33.096000 82.890000 ;
 RECT 33.264000 81.270000 33.340000 82.890000 ;
 RECT 33.508000 81.270000 33.584000 82.890000 ;
 RECT 32.776000 82.890000 32.852000 84.510000 ;
 RECT 33.020000 82.890000 33.096000 84.510000 ;
 RECT 33.264000 82.890000 33.340000 84.510000 ;
 RECT 33.508000 82.890000 33.584000 84.510000 ;
 RECT 32.776000 84.510000 32.852000 86.130000 ;
 RECT 33.020000 84.510000 33.096000 86.130000 ;
 RECT 33.264000 84.510000 33.340000 86.130000 ;
 RECT 33.508000 84.510000 33.584000 86.130000 ;
 RECT 32.776000 86.130000 32.852000 87.750000 ;
 RECT 33.020000 86.130000 33.096000 87.750000 ;
 RECT 33.264000 86.130000 33.340000 87.750000 ;
 RECT 33.508000 86.130000 33.584000 87.750000 ;
 RECT 32.776000 87.750000 32.852000 89.370000 ;
 RECT 33.020000 87.750000 33.096000 89.370000 ;
 RECT 33.264000 87.750000 33.340000 89.370000 ;
 RECT 33.508000 87.750000 33.584000 89.370000 ;
 RECT 32.776000 89.370000 32.852000 90.990000 ;
 RECT 33.020000 89.370000 33.096000 90.990000 ;
 RECT 33.264000 89.370000 33.340000 90.990000 ;
 RECT 33.508000 89.370000 33.584000 90.990000 ;
 RECT 32.776000 5.490000 32.852000 7.110000 ;
 RECT 33.020000 5.490000 33.096000 7.110000 ;
 RECT 33.264000 5.490000 33.340000 7.110000 ;
 RECT 33.508000 5.490000 33.584000 7.110000 ;
 RECT 32.776000 90.990000 32.852000 92.610000 ;
 RECT 33.020000 90.990000 33.096000 92.610000 ;
 RECT 33.264000 90.990000 33.340000 92.610000 ;
 RECT 33.508000 90.990000 33.584000 92.610000 ;
 RECT 32.776000 92.610000 32.852000 94.230000 ;
 RECT 33.020000 92.610000 33.096000 94.230000 ;
 RECT 33.264000 92.610000 33.340000 94.230000 ;
 RECT 33.508000 92.610000 33.584000 94.230000 ;
 RECT 32.776000 94.230000 32.852000 95.850000 ;
 RECT 33.020000 94.230000 33.096000 95.850000 ;
 RECT 33.264000 94.230000 33.340000 95.850000 ;
 RECT 33.508000 94.230000 33.584000 95.850000 ;
 RECT 32.776000 95.850000 32.852000 97.470000 ;
 RECT 33.020000 95.850000 33.096000 97.470000 ;
 RECT 33.264000 95.850000 33.340000 97.470000 ;
 RECT 33.508000 95.850000 33.584000 97.470000 ;
 RECT 32.776000 97.470000 32.852000 99.090000 ;
 RECT 33.020000 97.470000 33.096000 99.090000 ;
 RECT 33.264000 97.470000 33.340000 99.090000 ;
 RECT 33.508000 97.470000 33.584000 99.090000 ;
 RECT 32.776000 99.090000 32.852000 100.710000 ;
 RECT 33.020000 99.090000 33.096000 100.710000 ;
 RECT 33.264000 99.090000 33.340000 100.710000 ;
 RECT 33.508000 99.090000 33.584000 100.710000 ;
 RECT 32.776000 100.710000 32.852000 102.330000 ;
 RECT 33.020000 100.710000 33.096000 102.330000 ;
 RECT 33.264000 100.710000 33.340000 102.330000 ;
 RECT 33.508000 100.710000 33.584000 102.330000 ;
 RECT 32.776000 102.330000 32.852000 103.950000 ;
 RECT 33.020000 102.330000 33.096000 103.950000 ;
 RECT 33.264000 102.330000 33.340000 103.950000 ;
 RECT 33.508000 102.330000 33.584000 103.950000 ;
 RECT 32.776000 103.950000 32.852000 105.570000 ;
 RECT 33.020000 103.950000 33.096000 105.570000 ;
 RECT 33.264000 103.950000 33.340000 105.570000 ;
 RECT 33.508000 103.950000 33.584000 105.570000 ;
 RECT 32.776000 105.570000 32.852000 107.190000 ;
 RECT 33.020000 105.570000 33.096000 107.190000 ;
 RECT 33.264000 105.570000 33.340000 107.190000 ;
 RECT 33.508000 105.570000 33.584000 107.190000 ;
 RECT 32.776000 7.110000 32.852000 8.730000 ;
 RECT 33.020000 7.110000 33.096000 8.730000 ;
 RECT 33.264000 7.110000 33.340000 8.730000 ;
 RECT 33.508000 7.110000 33.584000 8.730000 ;
 RECT 32.776000 107.190000 32.852000 108.810000 ;
 RECT 33.020000 107.190000 33.096000 108.810000 ;
 RECT 33.264000 107.190000 33.340000 108.810000 ;
 RECT 33.508000 107.190000 33.584000 108.810000 ;
 RECT 32.776000 108.810000 32.852000 110.430000 ;
 RECT 33.020000 108.810000 33.096000 110.430000 ;
 RECT 33.264000 108.810000 33.340000 110.430000 ;
 RECT 33.508000 108.810000 33.584000 110.430000 ;
 RECT 32.776000 110.430000 32.852000 112.050000 ;
 RECT 33.020000 110.430000 33.096000 112.050000 ;
 RECT 33.264000 110.430000 33.340000 112.050000 ;
 RECT 33.508000 110.430000 33.584000 112.050000 ;
 RECT 32.776000 112.050000 32.852000 113.670000 ;
 RECT 33.020000 112.050000 33.096000 113.670000 ;
 RECT 33.264000 112.050000 33.340000 113.670000 ;
 RECT 33.508000 112.050000 33.584000 113.670000 ;
 RECT 32.776000 113.670000 32.852000 115.290000 ;
 RECT 33.020000 113.670000 33.096000 115.290000 ;
 RECT 33.264000 113.670000 33.340000 115.290000 ;
 RECT 33.508000 113.670000 33.584000 115.290000 ;
 RECT 32.776000 115.290000 32.852000 116.910000 ;
 RECT 33.020000 115.290000 33.096000 116.910000 ;
 RECT 33.264000 115.290000 33.340000 116.910000 ;
 RECT 33.508000 115.290000 33.584000 116.910000 ;
 RECT 49.620000 0.630000 49.696000 2.250000 ;
 RECT 49.864000 0.630000 49.940000 2.250000 ;
 RECT 50.108000 0.630000 50.184000 2.250000 ;
 RECT 50.352000 0.630000 50.428000 2.250000 ;
 RECT 49.620000 2.250000 49.696000 3.870000 ;
 RECT 49.864000 2.250000 49.940000 3.870000 ;
 RECT 50.108000 2.250000 50.184000 3.870000 ;
 RECT 50.352000 2.250000 50.428000 3.870000 ;
 RECT 49.620000 3.870000 49.696000 5.490000 ;
 RECT 49.864000 3.870000 49.940000 5.490000 ;
 RECT 50.108000 3.870000 50.184000 5.490000 ;
 RECT 50.352000 3.870000 50.428000 5.490000 ;
 RECT 49.620000 5.490000 49.696000 7.110000 ;
 RECT 49.864000 5.490000 49.940000 7.110000 ;
 RECT 50.108000 5.490000 50.184000 7.110000 ;
 RECT 50.352000 5.490000 50.428000 7.110000 ;
 RECT 32.776000 8.730000 32.852000 10.350000 ;
 RECT 33.020000 8.730000 33.096000 10.350000 ;
 RECT 33.264000 8.730000 33.340000 10.350000 ;
 RECT 33.508000 8.730000 33.584000 10.350000 ;
 RECT 49.620000 7.110000 49.696000 8.730000 ;
 RECT 49.864000 7.110000 49.940000 8.730000 ;
 RECT 50.108000 7.110000 50.184000 8.730000 ;
 RECT 50.352000 7.110000 50.428000 8.730000 ;
 RECT 49.620000 8.730000 49.696000 10.350000 ;
 RECT 49.864000 8.730000 49.940000 10.350000 ;
 RECT 50.108000 8.730000 50.184000 10.350000 ;
 RECT 50.352000 8.730000 50.428000 10.350000 ;
 RECT 49.620000 10.350000 49.696000 11.970000 ;
 RECT 49.864000 10.350000 49.940000 11.970000 ;
 RECT 50.108000 10.350000 50.184000 11.970000 ;
 RECT 50.352000 10.350000 50.428000 11.970000 ;
 RECT 49.620000 11.970000 49.696000 13.590000 ;
 RECT 49.864000 11.970000 49.940000 13.590000 ;
 RECT 50.108000 11.970000 50.184000 13.590000 ;
 RECT 50.352000 11.970000 50.428000 13.590000 ;
 RECT 49.620000 13.590000 49.696000 15.210000 ;
 RECT 49.864000 13.590000 49.940000 15.210000 ;
 RECT 50.108000 13.590000 50.184000 15.210000 ;
 RECT 50.352000 13.590000 50.428000 15.210000 ;
 RECT 49.620000 15.210000 49.696000 16.830000 ;
 RECT 49.864000 15.210000 49.940000 16.830000 ;
 RECT 50.108000 15.210000 50.184000 16.830000 ;
 RECT 50.352000 15.210000 50.428000 16.830000 ;
 RECT 49.620000 16.830000 49.696000 18.450000 ;
 RECT 49.864000 16.830000 49.940000 18.450000 ;
 RECT 50.108000 16.830000 50.184000 18.450000 ;
 RECT 50.352000 16.830000 50.428000 18.450000 ;
 RECT 49.620000 18.450000 49.696000 20.070000 ;
 RECT 49.864000 18.450000 49.940000 20.070000 ;
 RECT 50.108000 18.450000 50.184000 20.070000 ;
 RECT 50.352000 18.450000 50.428000 20.070000 ;
 RECT 49.620000 20.070000 49.696000 21.690000 ;
 RECT 49.864000 20.070000 49.940000 21.690000 ;
 RECT 50.108000 20.070000 50.184000 21.690000 ;
 RECT 50.352000 20.070000 50.428000 21.690000 ;
 RECT 49.620000 21.690000 49.696000 23.310000 ;
 RECT 49.864000 21.690000 49.940000 23.310000 ;
 RECT 50.108000 21.690000 50.184000 23.310000 ;
 RECT 50.352000 21.690000 50.428000 23.310000 ;
 RECT 32.776000 10.350000 32.852000 11.970000 ;
 RECT 33.020000 10.350000 33.096000 11.970000 ;
 RECT 33.264000 10.350000 33.340000 11.970000 ;
 RECT 33.508000 10.350000 33.584000 11.970000 ;
 RECT 49.620000 23.310000 49.696000 24.930000 ;
 RECT 49.864000 23.310000 49.940000 24.930000 ;
 RECT 50.108000 23.310000 50.184000 24.930000 ;
 RECT 50.352000 23.310000 50.428000 24.930000 ;
 RECT 49.620000 24.930000 49.696000 26.550000 ;
 RECT 49.864000 24.930000 49.940000 26.550000 ;
 RECT 50.108000 24.930000 50.184000 26.550000 ;
 RECT 50.352000 24.930000 50.428000 26.550000 ;
 RECT 49.620000 26.550000 49.696000 28.170000 ;
 RECT 49.864000 26.550000 49.940000 28.170000 ;
 RECT 50.108000 26.550000 50.184000 28.170000 ;
 RECT 50.352000 26.550000 50.428000 28.170000 ;
 RECT 49.620000 28.170000 49.696000 29.790000 ;
 RECT 49.864000 28.170000 49.940000 29.790000 ;
 RECT 50.108000 28.170000 50.184000 29.790000 ;
 RECT 50.352000 28.170000 50.428000 29.790000 ;
 RECT 49.620000 29.790000 49.696000 31.410000 ;
 RECT 49.864000 29.790000 49.940000 31.410000 ;
 RECT 50.108000 29.790000 50.184000 31.410000 ;
 RECT 50.352000 29.790000 50.428000 31.410000 ;
 RECT 49.620000 31.410000 49.696000 33.030000 ;
 RECT 49.864000 31.410000 49.940000 33.030000 ;
 RECT 50.108000 31.410000 50.184000 33.030000 ;
 RECT 50.352000 31.410000 50.428000 33.030000 ;
 RECT 49.620000 33.030000 49.696000 34.650000 ;
 RECT 49.864000 33.030000 49.940000 34.650000 ;
 RECT 50.108000 33.030000 50.184000 34.650000 ;
 RECT 50.352000 33.030000 50.428000 34.650000 ;
 RECT 49.620000 34.650000 49.696000 36.270000 ;
 RECT 49.864000 34.650000 49.940000 36.270000 ;
 RECT 50.108000 34.650000 50.184000 36.270000 ;
 RECT 50.352000 34.650000 50.428000 36.270000 ;
 RECT 49.620000 36.270000 49.696000 37.890000 ;
 RECT 49.864000 36.270000 49.940000 37.890000 ;
 RECT 50.108000 36.270000 50.184000 37.890000 ;
 RECT 50.352000 36.270000 50.428000 37.890000 ;
 RECT 49.620000 37.890000 49.696000 39.510000 ;
 RECT 49.864000 37.890000 49.940000 39.510000 ;
 RECT 50.108000 37.890000 50.184000 39.510000 ;
 RECT 50.352000 37.890000 50.428000 39.510000 ;
 RECT 32.776000 11.970000 32.852000 13.590000 ;
 RECT 33.020000 11.970000 33.096000 13.590000 ;
 RECT 33.264000 11.970000 33.340000 13.590000 ;
 RECT 33.508000 11.970000 33.584000 13.590000 ;
 RECT 49.620000 39.510000 49.696000 41.130000 ;
 RECT 49.864000 39.510000 49.940000 41.130000 ;
 RECT 50.108000 39.510000 50.184000 41.130000 ;
 RECT 50.352000 39.510000 50.428000 41.130000 ;
 RECT 49.620000 41.130000 49.696000 42.750000 ;
 RECT 49.864000 41.130000 49.940000 42.750000 ;
 RECT 50.108000 41.130000 50.184000 42.750000 ;
 RECT 50.352000 41.130000 50.428000 42.750000 ;
 RECT 49.620000 42.750000 49.696000 44.370000 ;
 RECT 49.864000 42.750000 49.940000 44.370000 ;
 RECT 50.108000 42.750000 50.184000 44.370000 ;
 RECT 50.352000 42.750000 50.428000 44.370000 ;
 RECT 49.620000 44.370000 49.696000 45.990000 ;
 RECT 49.864000 44.370000 49.940000 45.990000 ;
 RECT 50.108000 44.370000 50.184000 45.990000 ;
 RECT 50.352000 44.370000 50.428000 45.990000 ;
 RECT 49.620000 45.990000 49.696000 47.610000 ;
 RECT 49.864000 45.990000 49.940000 47.610000 ;
 RECT 50.108000 45.990000 50.184000 47.610000 ;
 RECT 50.352000 45.990000 50.428000 47.610000 ;
 RECT 49.620000 47.610000 49.696000 49.230000 ;
 RECT 49.864000 47.610000 49.940000 49.230000 ;
 RECT 50.108000 47.610000 50.184000 49.230000 ;
 RECT 50.352000 47.610000 50.428000 49.230000 ;
 RECT 49.620000 49.230000 49.696000 50.850000 ;
 RECT 49.864000 49.230000 49.940000 50.850000 ;
 RECT 50.108000 49.230000 50.184000 50.850000 ;
 RECT 50.352000 49.230000 50.428000 50.850000 ;
 RECT 49.620000 50.850000 49.696000 52.470000 ;
 RECT 49.864000 50.850000 49.940000 52.470000 ;
 RECT 50.108000 50.850000 50.184000 52.470000 ;
 RECT 50.352000 50.850000 50.428000 52.470000 ;
 RECT 49.620000 65.070000 49.696000 66.690000 ;
 RECT 49.864000 65.070000 49.940000 66.690000 ;
 RECT 50.108000 65.070000 50.184000 66.690000 ;
 RECT 50.352000 65.070000 50.428000 66.690000 ;
 RECT 49.620000 66.690000 49.696000 68.310000 ;
 RECT 49.864000 66.690000 49.940000 68.310000 ;
 RECT 50.108000 66.690000 50.184000 68.310000 ;
 RECT 50.352000 66.690000 50.428000 68.310000 ;
 END
 END vccperfgt_lv
END ip224uhdlp1p11rf_2048x32m8b2c1s0_t0r0p1d0a1m1h_APACHECELL
END LIBRARY
